VERSION 5.8 ;
BUSBITCHARS "[]" ;
DIVIDERCHAR "/" ;
UNITS
    DATABASE MICRONS 1000 ;
END UNITS

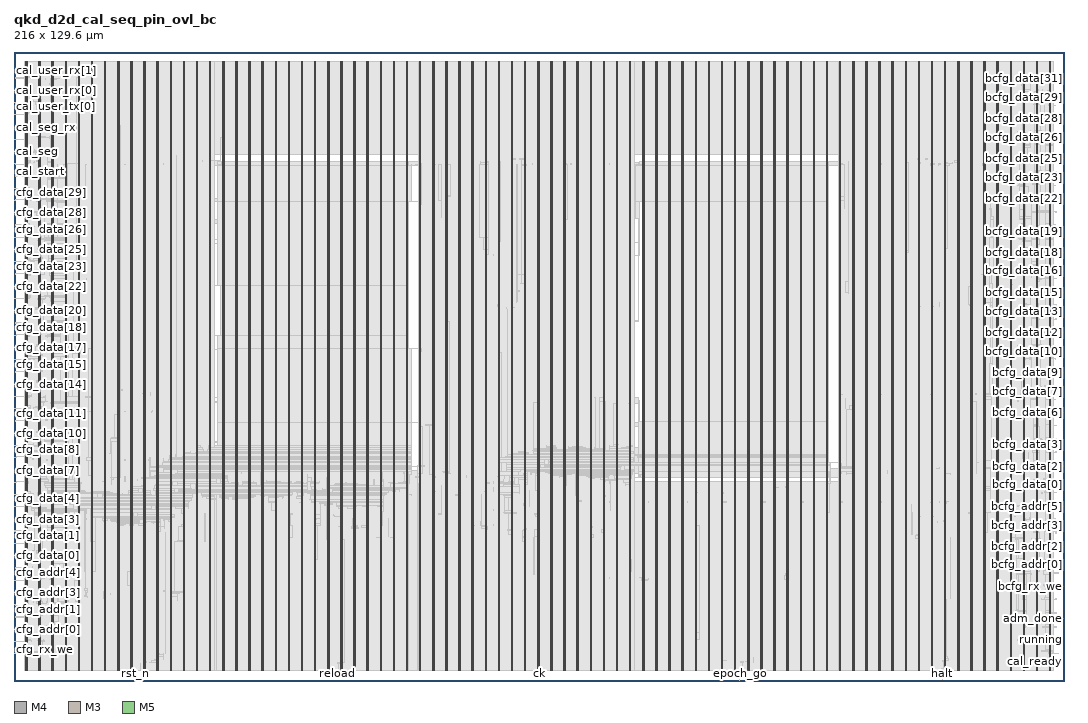
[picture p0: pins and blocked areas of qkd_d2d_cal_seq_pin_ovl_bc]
MACRO qkd_d2d_cal_seq_pin_ovl_bc
  FOREIGN qkd_d2d_cal_seq_pin_ovl_bc 0 0 ;
  CLASS BLOCK ;
  SIZE 216 BY 129.6 ;
  PIN adm_done
    DIRECTION OUTPUT ;
    USE SIGNAL ;
    PORT
      LAYER M4 ;
        RECT  215.808 11.184 216 11.208 ;
    END
  END adm_done
  PIN bcfg_addr[0]
    DIRECTION INPUT ;
    USE SIGNAL ;
    PORT
      LAYER M4 ;
        RECT  215.808 22.224 216 22.248 ;
    END
  END bcfg_addr[0]
  PIN bcfg_addr[1]
    DIRECTION INPUT ;
    USE SIGNAL ;
    PORT
      LAYER M4 ;
        RECT  215.808 24.96 216 24.984 ;
    END
  END bcfg_addr[1]
  PIN bcfg_addr[2]
    DIRECTION INPUT ;
    USE SIGNAL ;
    PORT
      LAYER M4 ;
        RECT  215.808 27.696 216 27.72 ;
    END
  END bcfg_addr[2]
  PIN bcfg_addr[3]
    DIRECTION INPUT ;
    USE SIGNAL ;
    PORT
      LAYER M4 ;
        RECT  215.808 30.432 216 30.456 ;
    END
  END bcfg_addr[3]
  PIN bcfg_addr[4]
    DIRECTION INPUT ;
    USE SIGNAL ;
    PORT
      LAYER M4 ;
        RECT  215.808 33.216 216 33.24 ;
    END
  END bcfg_addr[4]
  PIN bcfg_addr[5]
    DIRECTION INPUT ;
    USE SIGNAL ;
    PORT
      LAYER M4 ;
        RECT  215.808 35.952 216 35.976 ;
    END
  END bcfg_addr[5]
  PIN bcfg_data[0]
    DIRECTION INPUT ;
    USE SIGNAL ;
    PORT
      LAYER M4 ;
        RECT  215.808 38.688 216 38.712 ;
    END
  END bcfg_data[0]
  PIN bcfg_data[10]
    DIRECTION INPUT ;
    USE SIGNAL ;
    PORT
      LAYER M4 ;
        RECT  215.808 66.192 216 66.216 ;
    END
  END bcfg_data[10]
  PIN bcfg_data[11]
    DIRECTION INPUT ;
    USE SIGNAL ;
    PORT
      LAYER M4 ;
        RECT  215.808 68.928 216 68.952 ;
    END
  END bcfg_data[11]
  PIN bcfg_data[12]
    DIRECTION INPUT ;
    USE SIGNAL ;
    PORT
      LAYER M4 ;
        RECT  215.808 71.664 216 71.688 ;
    END
  END bcfg_data[12]
  PIN bcfg_data[13]
    DIRECTION INPUT ;
    USE SIGNAL ;
    PORT
      LAYER M4 ;
        RECT  215.808 74.448 216 74.472 ;
    END
  END bcfg_data[13]
  PIN bcfg_data[14]
    DIRECTION INPUT ;
    USE SIGNAL ;
    PORT
      LAYER M4 ;
        RECT  215.808 77.184 216 77.208 ;
    END
  END bcfg_data[14]
  PIN bcfg_data[15]
    DIRECTION INPUT ;
    USE SIGNAL ;
    PORT
      LAYER M4 ;
        RECT  215.808 79.92 216 79.944 ;
    END
  END bcfg_data[15]
  PIN bcfg_data[16]
    DIRECTION INPUT ;
    USE SIGNAL ;
    PORT
      LAYER M4 ;
        RECT  215.808 82.704 216 82.728 ;
    END
  END bcfg_data[16]
  PIN bcfg_data[17]
    DIRECTION INPUT ;
    USE SIGNAL ;
    PORT
      LAYER M4 ;
        RECT  215.808 85.44 216 85.464 ;
    END
  END bcfg_data[17]
  PIN bcfg_data[18]
    DIRECTION INPUT ;
    USE SIGNAL ;
    PORT
      LAYER M4 ;
        RECT  215.808 88.176 216 88.2 ;
    END
  END bcfg_data[18]
  PIN bcfg_data[19]
    DIRECTION INPUT ;
    USE SIGNAL ;
    PORT
      LAYER M4 ;
        RECT  215.808 90.912 216 90.936 ;
    END
  END bcfg_data[19]
  PIN bcfg_data[1]
    DIRECTION INPUT ;
    USE SIGNAL ;
    PORT
      LAYER M4 ;
        RECT  215.808 41.424 216 41.448 ;
    END
  END bcfg_data[1]
  PIN bcfg_data[20]
    DIRECTION INPUT ;
    USE SIGNAL ;
    PORT
      LAYER M4 ;
        RECT  215.808 93.696 216 93.72 ;
    END
  END bcfg_data[20]
  PIN bcfg_data[21]
    DIRECTION INPUT ;
    USE SIGNAL ;
    PORT
      LAYER M4 ;
        RECT  215.808 96.432 216 96.456 ;
    END
  END bcfg_data[21]
  PIN bcfg_data[22]
    DIRECTION INPUT ;
    USE SIGNAL ;
    PORT
      LAYER M4 ;
        RECT  215.808 99.168 216 99.192 ;
    END
  END bcfg_data[22]
  PIN bcfg_data[23]
    DIRECTION INPUT ;
    USE SIGNAL ;
    PORT
      LAYER M4 ;
        RECT  215.808 101.904 216 101.928 ;
    END
  END bcfg_data[23]
  PIN bcfg_data[24]
    DIRECTION INPUT ;
    USE SIGNAL ;
    PORT
      LAYER M4 ;
        RECT  215.808 104.688 216 104.712 ;
    END
  END bcfg_data[24]
  PIN bcfg_data[25]
    DIRECTION INPUT ;
    USE SIGNAL ;
    PORT
      LAYER M4 ;
        RECT  215.808 107.424 216 107.448 ;
    END
  END bcfg_data[25]
  PIN bcfg_data[26]
    DIRECTION INPUT ;
    USE SIGNAL ;
    PORT
      LAYER M4 ;
        RECT  215.808 110.16 216 110.184 ;
    END
  END bcfg_data[26]
  PIN bcfg_data[27]
    DIRECTION INPUT ;
    USE SIGNAL ;
    PORT
      LAYER M4 ;
        RECT  215.808 112.944 216 112.968 ;
    END
  END bcfg_data[27]
  PIN bcfg_data[28]
    DIRECTION INPUT ;
    USE SIGNAL ;
    PORT
      LAYER M4 ;
        RECT  215.808 115.68 216 115.704 ;
    END
  END bcfg_data[28]
  PIN bcfg_data[29]
    DIRECTION INPUT ;
    USE SIGNAL ;
    PORT
      LAYER M4 ;
        RECT  215.808 118.416 216 118.44 ;
    END
  END bcfg_data[29]
  PIN bcfg_data[2]
    DIRECTION INPUT ;
    USE SIGNAL ;
    PORT
      LAYER M4 ;
        RECT  215.808 44.208 216 44.232 ;
    END
  END bcfg_data[2]
  PIN bcfg_data[30]
    DIRECTION INPUT ;
    USE SIGNAL ;
    PORT
      LAYER M4 ;
        RECT  215.808 121.152 216 121.176 ;
    END
  END bcfg_data[30]
  PIN bcfg_data[31]
    DIRECTION INPUT ;
    USE SIGNAL ;
    PORT
      LAYER M4 ;
        RECT  215.808 123.936 216 123.96 ;
    END
  END bcfg_data[31]
  PIN bcfg_data[3]
    DIRECTION INPUT ;
    USE SIGNAL ;
    PORT
      LAYER M4 ;
        RECT  215.808 46.944 216 46.968 ;
    END
  END bcfg_data[3]
  PIN bcfg_data[4]
    DIRECTION INPUT ;
    USE SIGNAL ;
    PORT
      LAYER M4 ;
        RECT  215.808 49.68 216 49.704 ;
    END
  END bcfg_data[4]
  PIN bcfg_data[5]
    DIRECTION INPUT ;
    USE SIGNAL ;
    PORT
      LAYER M4 ;
        RECT  215.808 52.464 216 52.488 ;
    END
  END bcfg_data[5]
  PIN bcfg_data[6]
    DIRECTION INPUT ;
    USE SIGNAL ;
    PORT
      LAYER M4 ;
        RECT  215.808 55.2 216 55.224 ;
    END
  END bcfg_data[6]
  PIN bcfg_data[7]
    DIRECTION INPUT ;
    USE SIGNAL ;
    PORT
      LAYER M4 ;
        RECT  215.808 57.936 216 57.96 ;
    END
  END bcfg_data[7]
  PIN bcfg_data[8]
    DIRECTION INPUT ;
    USE SIGNAL ;
    PORT
      LAYER M4 ;
        RECT  215.808 60.672 216 60.696 ;
    END
  END bcfg_data[8]
  PIN bcfg_data[9]
    DIRECTION INPUT ;
    USE SIGNAL ;
    PORT
      LAYER M4 ;
        RECT  215.808 63.456 216 63.48 ;
    END
  END bcfg_data[9]
  PIN bcfg_rx_we
    DIRECTION INPUT ;
    USE SIGNAL ;
    PORT
      LAYER M4 ;
        RECT  215.808 19.44 216 19.464 ;
    END
  END bcfg_rx_we
  PIN bcfg_tx_we
    DIRECTION INPUT ;
    USE SIGNAL ;
    PORT
      LAYER M4 ;
        RECT  215.808 16.704 216 16.728 ;
    END
  END bcfg_tx_we
  PIN cal_ready
    DIRECTION OUTPUT ;
    USE SIGNAL ;
    PORT
      LAYER M4 ;
        RECT  215.808 5.712 216 5.736 ;
    END
  END cal_ready
  PIN cal_seg
    DIRECTION OUTPUT ;
    USE SIGNAL ;
    PORT
      LAYER M4 ;
        RECT  0 108.912 0.192 108.936 ;
    END
  END cal_seg
  PIN cal_seg_rx
    DIRECTION OUTPUT ;
    USE SIGNAL ;
    PORT
      LAYER M4 ;
        RECT  0 113.952 0.192 113.976 ;
    END
  END cal_seg_rx
  PIN cal_start
    DIRECTION OUTPUT ;
    USE SIGNAL ;
    PORT
      LAYER M4 ;
        RECT  0 106.416 0.192 106.44 ;
    END
  END cal_start
  PIN cal_start_rx
    DIRECTION OUTPUT ;
    USE SIGNAL ;
    PORT
      LAYER M4 ;
        RECT  0 111.408 0.192 111.432 ;
    END
  END cal_start_rx
  PIN cal_user_rx[0]
    DIRECTION OUTPUT ;
    USE SIGNAL ;
    PORT
      LAYER M4 ;
        RECT  0 121.488 0.192 121.512 ;
    END
  END cal_user_rx[0]
  PIN cal_user_rx[1]
    DIRECTION OUTPUT ;
    USE SIGNAL ;
    PORT
      LAYER M4 ;
        RECT  0 124.032 0.192 124.056 ;
    END
  END cal_user_rx[1]
  PIN cal_user_tx[0]
    DIRECTION OUTPUT ;
    USE SIGNAL ;
    PORT
      LAYER M4 ;
        RECT  0 116.496 0.192 116.52 ;
    END
  END cal_user_tx[0]
  PIN cal_user_tx[1]
    DIRECTION OUTPUT ;
    USE SIGNAL ;
    PORT
      LAYER M4 ;
        RECT  0 118.992 0.192 119.016 ;
    END
  END cal_user_tx[1]
  PIN cfg_addr[0]
    DIRECTION OUTPUT ;
    USE SIGNAL ;
    PORT
      LAYER M4 ;
        RECT  0 10.656 0.192 10.68 ;
    END
  END cfg_addr[0]
  PIN cfg_addr[1]
    DIRECTION OUTPUT ;
    USE SIGNAL ;
    PORT
      LAYER M4 ;
        RECT  0 13.152 0.192 13.176 ;
    END
  END cfg_addr[1]
  PIN cfg_addr[2]
    DIRECTION OUTPUT ;
    USE SIGNAL ;
    PORT
      LAYER M4 ;
        RECT  0 15.696 0.192 15.72 ;
    END
  END cfg_addr[2]
  PIN cfg_addr[3]
    DIRECTION OUTPUT ;
    USE SIGNAL ;
    PORT
      LAYER M4 ;
        RECT  0 18.192 0.192 18.216 ;
    END
  END cfg_addr[3]
  PIN cfg_addr[4]
    DIRECTION OUTPUT ;
    USE SIGNAL ;
    PORT
      LAYER M4 ;
        RECT  0 20.688 0.192 20.712 ;
    END
  END cfg_addr[4]
  PIN cfg_addr[5]
    DIRECTION OUTPUT ;
    USE SIGNAL ;
    PORT
      LAYER M4 ;
        RECT  0 23.232 0.192 23.256 ;
    END
  END cfg_addr[5]
  PIN cfg_data[0]
    DIRECTION OUTPUT ;
    USE SIGNAL ;
    PORT
      LAYER M4 ;
        RECT  0 25.776 0.192 25.8 ;
    END
  END cfg_data[0]
  PIN cfg_data[10]
    DIRECTION OUTPUT ;
    USE SIGNAL ;
    PORT
      LAYER M4 ;
        RECT  0 50.928 0.192 50.952 ;
    END
  END cfg_data[10]
  PIN cfg_data[11]
    DIRECTION OUTPUT ;
    USE SIGNAL ;
    PORT
      LAYER M4 ;
        RECT  0 53.472 0.192 53.496 ;
    END
  END cfg_data[11]
  PIN cfg_data[12]
    DIRECTION OUTPUT ;
    USE SIGNAL ;
    PORT
      LAYER M4 ;
        RECT  0 56.016 0.192 56.04 ;
    END
  END cfg_data[12]
  PIN cfg_data[13]
    DIRECTION OUTPUT ;
    USE SIGNAL ;
    PORT
      LAYER M4 ;
        RECT  0 58.512 0.192 58.536 ;
    END
  END cfg_data[13]
  PIN cfg_data[14]
    DIRECTION OUTPUT ;
    USE SIGNAL ;
    PORT
      LAYER M4 ;
        RECT  0 61.008 0.192 61.032 ;
    END
  END cfg_data[14]
  PIN cfg_data[15]
    DIRECTION OUTPUT ;
    USE SIGNAL ;
    PORT
      LAYER M4 ;
        RECT  0 63.552 0.192 63.576 ;
    END
  END cfg_data[15]
  PIN cfg_data[16]
    DIRECTION OUTPUT ;
    USE SIGNAL ;
    PORT
      LAYER M4 ;
        RECT  0 66.096 0.192 66.12 ;
    END
  END cfg_data[16]
  PIN cfg_data[17]
    DIRECTION OUTPUT ;
    USE SIGNAL ;
    PORT
      LAYER M4 ;
        RECT  0 68.592 0.192 68.616 ;
    END
  END cfg_data[17]
  PIN cfg_data[18]
    DIRECTION OUTPUT ;
    USE SIGNAL ;
    PORT
      LAYER M4 ;
        RECT  0 71.088 0.192 71.112 ;
    END
  END cfg_data[18]
  PIN cfg_data[19]
    DIRECTION OUTPUT ;
    USE SIGNAL ;
    PORT
      LAYER M4 ;
        RECT  0 73.632 0.192 73.656 ;
    END
  END cfg_data[19]
  PIN cfg_data[1]
    DIRECTION OUTPUT ;
    USE SIGNAL ;
    PORT
      LAYER M4 ;
        RECT  0 28.272 0.192 28.296 ;
    END
  END cfg_data[1]
  PIN cfg_data[20]
    DIRECTION OUTPUT ;
    USE SIGNAL ;
    PORT
      LAYER M4 ;
        RECT  0 76.176 0.192 76.2 ;
    END
  END cfg_data[20]
  PIN cfg_data[21]
    DIRECTION OUTPUT ;
    USE SIGNAL ;
    PORT
      LAYER M4 ;
        RECT  0 78.672 0.192 78.696 ;
    END
  END cfg_data[21]
  PIN cfg_data[22]
    DIRECTION OUTPUT ;
    USE SIGNAL ;
    PORT
      LAYER M4 ;
        RECT  0 81.168 0.192 81.192 ;
    END
  END cfg_data[22]
  PIN cfg_data[23]
    DIRECTION OUTPUT ;
    USE SIGNAL ;
    PORT
      LAYER M4 ;
        RECT  0 83.712 0.192 83.736 ;
    END
  END cfg_data[23]
  PIN cfg_data[24]
    DIRECTION OUTPUT ;
    USE SIGNAL ;
    PORT
      LAYER M4 ;
        RECT  0 86.256 0.192 86.28 ;
    END
  END cfg_data[24]
  PIN cfg_data[25]
    DIRECTION OUTPUT ;
    USE SIGNAL ;
    PORT
      LAYER M4 ;
        RECT  0 88.752 0.192 88.776 ;
    END
  END cfg_data[25]
  PIN cfg_data[26]
    DIRECTION OUTPUT ;
    USE SIGNAL ;
    PORT
      LAYER M4 ;
        RECT  0 91.248 0.192 91.272 ;
    END
  END cfg_data[26]
  PIN cfg_data[27]
    DIRECTION OUTPUT ;
    USE SIGNAL ;
    PORT
      LAYER M4 ;
        RECT  0 93.792 0.192 93.816 ;
    END
  END cfg_data[27]
  PIN cfg_data[28]
    DIRECTION OUTPUT ;
    USE SIGNAL ;
    PORT
      LAYER M4 ;
        RECT  0 96.336 0.192 96.36 ;
    END
  END cfg_data[28]
  PIN cfg_data[29]
    DIRECTION OUTPUT ;
    USE SIGNAL ;
    PORT
      LAYER M4 ;
        RECT  0 98.832 0.192 98.856 ;
    END
  END cfg_data[29]
  PIN cfg_data[2]
    DIRECTION OUTPUT ;
    USE SIGNAL ;
    PORT
      LAYER M4 ;
        RECT  0 30.768 0.192 30.792 ;
    END
  END cfg_data[2]
  PIN cfg_data[30]
    DIRECTION OUTPUT ;
    USE SIGNAL ;
    PORT
      LAYER M4 ;
        RECT  0 101.328 0.192 101.352 ;
    END
  END cfg_data[30]
  PIN cfg_data[31]
    DIRECTION OUTPUT ;
    USE SIGNAL ;
    PORT
      LAYER M4 ;
        RECT  0 103.872 0.192 103.896 ;
    END
  END cfg_data[31]
  PIN cfg_data[3]
    DIRECTION OUTPUT ;
    USE SIGNAL ;
    PORT
      LAYER M4 ;
        RECT  0 33.312 0.192 33.336 ;
    END
  END cfg_data[3]
  PIN cfg_data[4]
    DIRECTION OUTPUT ;
    USE SIGNAL ;
    PORT
      LAYER M4 ;
        RECT  0 35.856 0.192 35.88 ;
    END
  END cfg_data[4]
  PIN cfg_data[5]
    DIRECTION OUTPUT ;
    USE SIGNAL ;
    PORT
      LAYER M4 ;
        RECT  0 38.352 0.192 38.376 ;
    END
  END cfg_data[5]
  PIN cfg_data[6]
    DIRECTION OUTPUT ;
    USE SIGNAL ;
    PORT
      LAYER M4 ;
        RECT  0 40.848 0.192 40.872 ;
    END
  END cfg_data[6]
  PIN cfg_data[7]
    DIRECTION OUTPUT ;
    USE SIGNAL ;
    PORT
      LAYER M4 ;
        RECT  0 43.392 0.192 43.416 ;
    END
  END cfg_data[7]
  PIN cfg_data[8]
    DIRECTION OUTPUT ;
    USE SIGNAL ;
    PORT
      LAYER M4 ;
        RECT  0 45.888 0.192 45.912 ;
    END
  END cfg_data[8]
  PIN cfg_data[9]
    DIRECTION OUTPUT ;
    USE SIGNAL ;
    PORT
      LAYER M4 ;
        RECT  0 48.432 0.192 48.456 ;
    END
  END cfg_data[9]
  PIN cfg_rx_we
    DIRECTION OUTPUT ;
    USE SIGNAL ;
    PORT
      LAYER M4 ;
        RECT  0 8.112 0.192 8.136 ;
    END
  END cfg_rx_we
  PIN cfg_tx_we
    DIRECTION OUTPUT ;
    USE SIGNAL ;
    PORT
      LAYER M4 ;
        RECT  0 5.616 0.192 5.64 ;
    END
  END cfg_tx_we
  PIN ck
    DIRECTION INPUT ;
    USE SIGNAL ;
    PORT
      LAYER M3 ;
        RECT  108 0 108.018 0.144 ;
    END
  END ck
  PIN epoch_go
    DIRECTION INPUT ;
    USE SIGNAL ;
    PORT
      LAYER M5 ;
        RECT  149.472 0 149.496 0.192 ;
    END
  END epoch_go
  PIN fault
    DIRECTION OUTPUT ;
    USE SIGNAL ;
    PORT
      LAYER M4 ;
        RECT  215.808 13.968 216 13.992 ;
    END
  END fault
  PIN halt
    DIRECTION INPUT ;
    USE SIGNAL ;
    PORT
      LAYER M3 ;
        RECT  190.944 0 190.962 0.144 ;
    END
  END halt
  PIN reload
    DIRECTION INPUT ;
    USE SIGNAL ;
    PORT
      LAYER M5 ;
        RECT  66.528 0 66.552 0.192 ;
    END
  END reload
  PIN rst_n
    DIRECTION INPUT ;
    USE SIGNAL ;
    PORT
      LAYER M3 ;
        RECT  25.056 0 25.074 0.144 ;
    END
  END rst_n
  PIN running
    DIRECTION OUTPUT ;
    USE SIGNAL ;
    PORT
      LAYER M4 ;
        RECT  215.808 8.448 216 8.472 ;
    END
  END running
  PIN VDD
    DIRECTION INOUT ;
    USE POWER ;
    PORT
      LAYER M5 ;
        RECT  213.192 2.151 213.312 127.449 ;
        RECT  210.492 2.151 210.612 127.449 ;
        RECT  207.792 2.151 207.912 127.449 ;
        RECT  205.092 2.151 205.212 127.449 ;
        RECT  202.392 2.151 202.512 127.449 ;
        RECT  199.692 2.151 199.812 127.449 ;
        RECT  196.992 2.151 197.112 127.449 ;
        RECT  194.292 2.151 194.412 127.449 ;
        RECT  191.592 2.151 191.712 127.449 ;
        RECT  188.892 2.151 189.012 127.449 ;
        RECT  186.192 2.151 186.312 127.449 ;
        RECT  183.492 2.151 183.612 127.449 ;
        RECT  180.792 2.151 180.912 127.449 ;
        RECT  178.092 2.151 178.212 127.449 ;
        RECT  175.392 2.151 175.512 127.449 ;
        RECT  172.692 2.151 172.812 127.449 ;
        RECT  169.992 2.151 170.112 127.449 ;
        RECT  167.292 2.151 167.412 127.449 ;
        RECT  164.592 2.151 164.712 127.449 ;
        RECT  161.892 2.151 162.012 127.449 ;
        RECT  159.192 2.151 159.312 127.449 ;
        RECT  156.492 2.151 156.612 127.449 ;
        RECT  153.792 2.151 153.912 127.449 ;
        RECT  151.092 2.151 151.212 127.449 ;
        RECT  148.392 2.151 148.512 127.449 ;
        RECT  145.692 2.151 145.812 127.449 ;
        RECT  142.992 2.151 143.112 127.449 ;
        RECT  140.292 2.151 140.412 127.449 ;
        RECT  137.592 2.151 137.712 127.449 ;
        RECT  134.892 2.151 135.012 127.449 ;
        RECT  132.192 2.151 132.312 127.449 ;
        RECT  129.492 2.151 129.612 127.449 ;
        RECT  126.792 2.151 126.912 127.449 ;
        RECT  124.092 2.151 124.212 127.449 ;
        RECT  121.392 2.151 121.512 127.449 ;
        RECT  118.692 2.151 118.812 127.449 ;
        RECT  115.992 2.151 116.112 127.449 ;
        RECT  113.292 2.151 113.412 127.449 ;
        RECT  110.592 2.151 110.712 127.449 ;
        RECT  107.892 2.151 108.012 127.449 ;
        RECT  105.192 2.151 105.312 127.449 ;
        RECT  102.492 2.151 102.612 127.449 ;
        RECT  99.792 2.151 99.912 127.449 ;
        RECT  97.092 2.151 97.212 127.449 ;
        RECT  94.392 2.151 94.512 127.449 ;
        RECT  91.692 2.151 91.812 127.449 ;
        RECT  88.992 2.151 89.112 127.449 ;
        RECT  86.292 2.151 86.412 127.449 ;
        RECT  83.592 2.151 83.712 127.449 ;
        RECT  80.892 2.151 81.012 127.449 ;
        RECT  78.192 2.151 78.312 127.449 ;
        RECT  75.492 2.151 75.612 127.449 ;
        RECT  72.792 2.151 72.912 127.449 ;
        RECT  70.092 2.151 70.212 127.449 ;
        RECT  67.392 2.151 67.512 127.449 ;
        RECT  64.692 2.151 64.812 127.449 ;
        RECT  61.992 2.151 62.112 127.449 ;
        RECT  59.292 2.151 59.412 127.449 ;
        RECT  56.592 2.151 56.712 127.449 ;
        RECT  53.892 2.151 54.012 127.449 ;
        RECT  51.192 2.151 51.312 127.449 ;
        RECT  48.492 2.151 48.612 127.449 ;
        RECT  45.792 2.151 45.912 127.449 ;
        RECT  43.092 2.151 43.212 127.449 ;
        RECT  40.392 2.151 40.512 127.449 ;
        RECT  37.692 2.151 37.812 127.449 ;
        RECT  34.992 2.151 35.112 127.449 ;
        RECT  32.292 2.151 32.412 127.449 ;
        RECT  29.592 2.151 29.712 127.449 ;
        RECT  26.892 2.151 27.012 127.449 ;
        RECT  24.192 2.151 24.312 127.449 ;
        RECT  21.492 2.151 21.612 127.449 ;
        RECT  18.792 2.151 18.912 127.449 ;
        RECT  16.092 2.151 16.212 127.449 ;
        RECT  13.392 2.151 13.512 127.449 ;
        RECT  10.692 2.151 10.812 127.449 ;
        RECT  7.992 2.151 8.112 127.449 ;
        RECT  5.292 2.151 5.412 127.449 ;
        RECT  2.592 2.151 2.712 127.449 ;
    END
  END VDD
  PIN VSS
    DIRECTION INOUT ;
    USE GROUND ;
    PORT
      LAYER M5 ;
        RECT  213 2.137 213.12 127.463 ;
        RECT  210.3 2.137 210.42 127.463 ;
        RECT  207.6 2.137 207.72 127.463 ;
        RECT  204.9 2.137 205.02 127.463 ;
        RECT  202.2 2.137 202.32 127.463 ;
        RECT  199.5 2.137 199.62 127.463 ;
        RECT  196.8 2.137 196.92 127.463 ;
        RECT  194.1 2.137 194.22 127.463 ;
        RECT  191.4 2.137 191.52 127.463 ;
        RECT  188.7 2.137 188.82 127.463 ;
        RECT  186 2.137 186.12 127.463 ;
        RECT  183.3 2.137 183.42 127.463 ;
        RECT  180.6 2.137 180.72 127.463 ;
        RECT  177.9 2.137 178.02 127.463 ;
        RECT  175.2 2.137 175.32 127.463 ;
        RECT  172.5 2.137 172.62 127.463 ;
        RECT  169.8 2.137 169.92 127.463 ;
        RECT  167.1 2.137 167.22 127.463 ;
        RECT  164.4 2.137 164.52 127.463 ;
        RECT  161.7 2.137 161.82 127.463 ;
        RECT  159 2.137 159.12 127.463 ;
        RECT  156.3 2.137 156.42 127.463 ;
        RECT  153.6 2.137 153.72 127.463 ;
        RECT  150.9 2.137 151.02 127.463 ;
        RECT  148.2 2.137 148.32 127.463 ;
        RECT  145.5 2.137 145.62 127.463 ;
        RECT  142.8 2.137 142.92 127.463 ;
        RECT  140.1 2.137 140.22 127.463 ;
        RECT  137.4 2.137 137.52 127.463 ;
        RECT  134.7 2.137 134.82 127.463 ;
        RECT  132 2.137 132.12 127.463 ;
        RECT  129.3 2.137 129.42 127.463 ;
        RECT  126.6 2.137 126.72 127.463 ;
        RECT  123.9 2.137 124.02 127.463 ;
        RECT  121.2 2.137 121.32 127.463 ;
        RECT  118.5 2.137 118.62 127.463 ;
        RECT  115.8 2.137 115.92 127.463 ;
        RECT  113.1 2.137 113.22 127.463 ;
        RECT  110.4 2.137 110.52 127.463 ;
        RECT  107.7 2.137 107.82 127.463 ;
        RECT  105 2.137 105.12 127.463 ;
        RECT  102.3 2.137 102.42 127.463 ;
        RECT  99.6 2.137 99.72 127.463 ;
        RECT  96.9 2.137 97.02 127.463 ;
        RECT  94.2 2.137 94.32 127.463 ;
        RECT  91.5 2.137 91.62 127.463 ;
        RECT  88.8 2.137 88.92 127.463 ;
        RECT  86.1 2.137 86.22 127.463 ;
        RECT  83.4 2.137 83.52 127.463 ;
        RECT  80.7 2.137 80.82 127.463 ;
        RECT  78 2.137 78.12 127.463 ;
        RECT  75.3 2.137 75.42 127.463 ;
        RECT  72.6 2.137 72.72 127.463 ;
        RECT  69.9 2.137 70.02 127.463 ;
        RECT  67.2 2.137 67.32 127.463 ;
        RECT  64.5 2.137 64.62 127.463 ;
        RECT  61.8 2.137 61.92 127.463 ;
        RECT  59.1 2.137 59.22 127.463 ;
        RECT  56.4 2.137 56.52 127.463 ;
        RECT  53.7 2.137 53.82 127.463 ;
        RECT  51 2.137 51.12 127.463 ;
        RECT  48.3 2.137 48.42 127.463 ;
        RECT  45.6 2.137 45.72 127.463 ;
        RECT  42.9 2.137 43.02 127.463 ;
        RECT  40.2 2.137 40.32 127.463 ;
        RECT  37.5 2.137 37.62 127.463 ;
        RECT  34.8 2.137 34.92 127.463 ;
        RECT  32.1 2.137 32.22 127.463 ;
        RECT  29.4 2.137 29.52 127.463 ;
        RECT  26.7 2.137 26.82 127.463 ;
        RECT  24 2.137 24.12 127.463 ;
        RECT  21.3 2.137 21.42 127.463 ;
        RECT  18.6 2.137 18.72 127.463 ;
        RECT  15.9 2.137 16.02 127.463 ;
        RECT  13.2 2.137 13.32 127.463 ;
        RECT  10.5 2.137 10.62 127.463 ;
        RECT  7.8 2.137 7.92 127.463 ;
        RECT  5.1 2.137 5.22 127.463 ;
        RECT  2.4 2.137 2.52 127.463 ;
    END
  END VSS
  OBS
    LAYER RVTN ;
     RECT  2.16 2.16 213.84 2.295 ;
     RECT  2.16 2.565 213.84 2.835 ;
     RECT  2.16 3.105 213.84 3.375 ;
     RECT  2.16 3.645 213.84 3.915 ;
     RECT  2.16 4.185 213.84 4.455 ;
     RECT  2.16 4.725 213.84 4.995 ;
     RECT  2.16 5.265 213.84 5.535 ;
     RECT  2.16 5.805 213.84 6.075 ;
     RECT  2.16 6.345 213.84 6.615 ;
     RECT  2.16 6.885 213.84 7.155 ;
     RECT  2.16 7.425 213.84 7.695 ;
     RECT  2.16 7.965 213.84 8.235 ;
     RECT  2.16 8.505 213.84 8.775 ;
     RECT  2.16 9.045 213.84 9.315 ;
     RECT  2.16 9.585 213.84 9.855 ;
     RECT  2.16 10.125 213.84 10.395 ;
     RECT  2.16 10.665 213.84 10.935 ;
     RECT  2.16 11.205 213.84 11.475 ;
     RECT  2.16 11.745 213.84 12.015 ;
     RECT  2.16 12.285 213.84 12.555 ;
     RECT  2.16 12.825 213.84 13.095 ;
     RECT  2.16 13.365 213.84 13.635 ;
     RECT  2.16 13.905 213.84 14.175 ;
     RECT  2.16 14.445 213.84 14.715 ;
     RECT  2.16 14.985 213.84 15.255 ;
     RECT  2.16 15.525 213.84 15.795 ;
     RECT  2.16 16.065 213.84 16.335 ;
     RECT  2.16 16.605 213.84 16.875 ;
     RECT  2.16 17.145 213.84 17.415 ;
     RECT  2.16 17.685 213.84 17.955 ;
     RECT  2.16 18.225 213.84 18.495 ;
     RECT  2.16 18.765 213.84 19.035 ;
     RECT  2.16 19.305 213.84 19.575 ;
     RECT  2.16 19.845 213.84 20.115 ;
     RECT  2.16 20.385 213.84 20.655 ;
     RECT  2.16 20.925 213.84 21.195 ;
     RECT  2.16 21.465 213.84 21.735 ;
     RECT  2.16 22.005 213.84 22.275 ;
     RECT  2.16 22.545 213.84 22.815 ;
     RECT  2.16 23.085 213.84 23.355 ;
     RECT  2.16 23.625 213.84 23.895 ;
     RECT  2.16 24.165 213.84 24.435 ;
     RECT  2.16 24.705 213.84 24.975 ;
     RECT  2.16 25.245 213.84 25.515 ;
     RECT  2.16 25.785 213.84 26.055 ;
     RECT  2.16 26.325 213.84 26.595 ;
     RECT  2.16 26.865 213.84 27.135 ;
     RECT  2.16 27.405 213.84 27.675 ;
     RECT  2.16 27.945 213.84 28.215 ;
     RECT  2.16 28.485 213.84 28.755 ;
     RECT  2.16 29.025 213.84 29.295 ;
     RECT  2.16 29.565 213.84 29.835 ;
     RECT  2.16 30.105 213.84 30.375 ;
     RECT  2.16 30.645 213.84 30.915 ;
     RECT  2.16 31.185 213.84 31.455 ;
     RECT  2.16 31.725 213.84 31.995 ;
     RECT  2.16 32.265 213.84 32.535 ;
     RECT  2.16 32.805 213.84 33.075 ;
     RECT  2.16 33.345 213.84 33.615 ;
     RECT  2.16 33.885 213.84 34.155 ;
     RECT  2.16 34.425 213.84 34.695 ;
     RECT  2.16 34.965 213.84 35.235 ;
     RECT  2.16 35.505 213.84 35.775 ;
     RECT  2.16 36.045 213.84 36.315 ;
     RECT  2.16 36.585 213.84 36.855 ;
     RECT  2.16 37.125 213.84 37.395 ;
     RECT  2.16 37.665 213.84 37.935 ;
     RECT  2.16 38.205 213.84 38.475 ;
     RECT  2.16 38.745 213.84 39.015 ;
     RECT  2.16 39.285 213.84 39.555 ;
     RECT  2.16 39.825 213.84 40.095 ;
     RECT  2.16 40.365 213.84 40.635 ;
     RECT  2.16 40.905 213.84 41.04 ;
     RECT  2.16 41.04 41.148 41.175 ;
     RECT  83.268 41.04 127.548 41.175 ;
     RECT  169.668 41.04 213.84 41.175 ;
     RECT  2.16 41.445 41.148 41.715 ;
     RECT  83.268 41.445 127.548 41.715 ;
     RECT  169.668 41.445 213.84 41.715 ;
     RECT  2.16 41.985 41.148 42.255 ;
     RECT  83.268 41.985 127.548 42.255 ;
     RECT  169.668 41.985 213.84 42.255 ;
     RECT  2.16 42.525 41.148 42.795 ;
     RECT  83.268 42.525 127.548 42.795 ;
     RECT  169.668 42.525 213.84 42.795 ;
     RECT  2.16 43.065 41.148 43.335 ;
     RECT  83.268 43.065 127.548 43.335 ;
     RECT  169.668 43.065 213.84 43.335 ;
     RECT  2.16 43.605 41.148 43.875 ;
     RECT  83.268 43.605 127.548 43.875 ;
     RECT  169.668 43.605 213.84 43.875 ;
     RECT  2.16 44.145 41.148 44.415 ;
     RECT  83.268 44.145 127.548 44.415 ;
     RECT  169.668 44.145 213.84 44.415 ;
     RECT  2.16 44.685 41.148 44.955 ;
     RECT  83.268 44.685 127.548 44.955 ;
     RECT  169.668 44.685 213.84 44.955 ;
     RECT  2.16 45.225 41.148 45.495 ;
     RECT  83.268 45.225 127.548 45.495 ;
     RECT  169.668 45.225 213.84 45.495 ;
     RECT  2.16 45.765 41.148 46.035 ;
     RECT  83.268 45.765 127.548 46.035 ;
     RECT  169.668 45.765 213.84 46.035 ;
     RECT  2.16 46.305 41.148 46.575 ;
     RECT  83.268 46.305 127.548 46.575 ;
     RECT  169.668 46.305 213.84 46.575 ;
     RECT  2.16 46.845 41.148 47.115 ;
     RECT  83.268 46.845 127.548 47.115 ;
     RECT  169.668 46.845 213.84 47.115 ;
     RECT  2.16 47.385 41.148 47.655 ;
     RECT  83.268 47.385 127.548 47.655 ;
     RECT  169.668 47.385 213.84 47.655 ;
     RECT  2.16 47.925 41.148 48.195 ;
     RECT  83.268 47.925 127.548 48.195 ;
     RECT  169.668 47.925 213.84 48.195 ;
     RECT  2.16 48.465 41.148 48.735 ;
     RECT  83.268 48.465 127.548 48.735 ;
     RECT  169.668 48.465 213.84 48.735 ;
     RECT  2.16 49.005 41.148 49.275 ;
     RECT  83.268 49.005 127.548 49.275 ;
     RECT  169.668 49.005 213.84 49.275 ;
     RECT  2.16 49.545 41.148 49.815 ;
     RECT  83.268 49.545 127.548 49.815 ;
     RECT  169.668 49.545 213.84 49.815 ;
     RECT  2.16 50.085 41.148 50.355 ;
     RECT  83.268 50.085 127.548 50.355 ;
     RECT  169.668 50.085 213.84 50.355 ;
     RECT  2.16 50.625 41.148 50.895 ;
     RECT  83.268 50.625 127.548 50.895 ;
     RECT  169.668 50.625 213.84 50.895 ;
     RECT  2.16 51.165 41.148 51.435 ;
     RECT  83.268 51.165 127.548 51.435 ;
     RECT  169.668 51.165 213.84 51.435 ;
     RECT  2.16 51.705 41.148 51.975 ;
     RECT  83.268 51.705 127.548 51.975 ;
     RECT  169.668 51.705 213.84 51.975 ;
     RECT  2.16 52.245 41.148 52.515 ;
     RECT  83.268 52.245 127.548 52.515 ;
     RECT  169.668 52.245 213.84 52.515 ;
     RECT  2.16 52.785 41.148 53.055 ;
     RECT  83.268 52.785 127.548 53.055 ;
     RECT  169.668 52.785 213.84 53.055 ;
     RECT  2.16 53.325 41.148 53.595 ;
     RECT  83.268 53.325 127.548 53.595 ;
     RECT  169.668 53.325 213.84 53.595 ;
     RECT  2.16 53.865 41.148 54.135 ;
     RECT  83.268 53.865 127.548 54.135 ;
     RECT  169.668 53.865 213.84 54.135 ;
     RECT  2.16 54.405 41.148 54.675 ;
     RECT  83.268 54.405 127.548 54.675 ;
     RECT  169.668 54.405 213.84 54.675 ;
     RECT  2.16 54.945 41.148 55.215 ;
     RECT  83.268 54.945 127.548 55.215 ;
     RECT  169.668 54.945 213.84 55.215 ;
     RECT  2.16 55.485 41.148 55.755 ;
     RECT  83.268 55.485 127.548 55.755 ;
     RECT  169.668 55.485 213.84 55.755 ;
     RECT  2.16 56.025 41.148 56.295 ;
     RECT  83.268 56.025 127.548 56.295 ;
     RECT  169.668 56.025 213.84 56.295 ;
     RECT  2.16 56.565 41.148 56.835 ;
     RECT  83.268 56.565 127.548 56.835 ;
     RECT  169.668 56.565 213.84 56.835 ;
     RECT  2.16 57.105 41.148 57.375 ;
     RECT  83.268 57.105 127.548 57.375 ;
     RECT  169.668 57.105 213.84 57.375 ;
     RECT  2.16 57.645 41.148 57.915 ;
     RECT  83.268 57.645 127.548 57.915 ;
     RECT  169.668 57.645 213.84 57.915 ;
     RECT  2.16 58.185 41.148 58.455 ;
     RECT  83.268 58.185 127.548 58.455 ;
     RECT  169.668 58.185 213.84 58.455 ;
     RECT  2.16 58.725 41.148 58.995 ;
     RECT  83.268 58.725 127.548 58.995 ;
     RECT  169.668 58.725 213.84 58.995 ;
     RECT  2.16 59.265 41.148 59.535 ;
     RECT  83.268 59.265 127.548 59.535 ;
     RECT  169.668 59.265 213.84 59.535 ;
     RECT  2.16 59.805 41.148 60.075 ;
     RECT  83.268 59.805 127.548 60.075 ;
     RECT  169.668 59.805 213.84 60.075 ;
     RECT  2.16 60.345 41.148 60.615 ;
     RECT  83.268 60.345 127.548 60.615 ;
     RECT  169.668 60.345 213.84 60.615 ;
     RECT  2.16 60.885 41.148 61.155 ;
     RECT  83.268 60.885 127.548 61.155 ;
     RECT  169.668 60.885 213.84 61.155 ;
     RECT  2.16 61.425 41.148 61.695 ;
     RECT  83.268 61.425 127.548 61.695 ;
     RECT  169.668 61.425 213.84 61.695 ;
     RECT  2.16 61.965 41.148 62.235 ;
     RECT  83.268 61.965 127.548 62.235 ;
     RECT  169.668 61.965 213.84 62.235 ;
     RECT  2.16 62.505 41.148 62.775 ;
     RECT  83.268 62.505 127.548 62.775 ;
     RECT  169.668 62.505 213.84 62.775 ;
     RECT  2.16 63.045 41.148 63.315 ;
     RECT  83.268 63.045 127.548 63.315 ;
     RECT  169.668 63.045 213.84 63.315 ;
     RECT  2.16 63.585 41.148 63.855 ;
     RECT  83.268 63.585 127.548 63.855 ;
     RECT  169.668 63.585 213.84 63.855 ;
     RECT  2.16 64.125 41.148 64.395 ;
     RECT  83.268 64.125 127.548 64.395 ;
     RECT  169.668 64.125 213.84 64.395 ;
     RECT  2.16 64.665 41.148 64.935 ;
     RECT  83.268 64.665 127.548 64.935 ;
     RECT  169.668 64.665 213.84 64.935 ;
     RECT  2.16 65.205 41.148 65.475 ;
     RECT  83.268 65.205 127.548 65.475 ;
     RECT  169.668 65.205 213.84 65.475 ;
     RECT  2.16 65.745 41.148 66.015 ;
     RECT  83.268 65.745 127.548 66.015 ;
     RECT  169.668 65.745 213.84 66.015 ;
     RECT  2.16 66.285 41.148 66.555 ;
     RECT  83.268 66.285 127.548 66.555 ;
     RECT  169.668 66.285 213.84 66.555 ;
     RECT  2.16 66.825 41.148 67.095 ;
     RECT  83.268 66.825 127.548 67.095 ;
     RECT  169.668 66.825 213.84 67.095 ;
     RECT  2.16 67.365 41.148 67.635 ;
     RECT  83.268 67.365 127.548 67.635 ;
     RECT  169.668 67.365 213.84 67.635 ;
     RECT  2.16 67.905 41.148 68.175 ;
     RECT  83.268 67.905 127.548 68.175 ;
     RECT  169.668 67.905 213.84 68.175 ;
     RECT  2.16 68.445 41.148 68.715 ;
     RECT  83.268 68.445 127.548 68.715 ;
     RECT  169.668 68.445 213.84 68.715 ;
     RECT  2.16 68.985 41.148 69.255 ;
     RECT  83.268 68.985 127.548 69.255 ;
     RECT  169.668 68.985 213.84 69.255 ;
     RECT  2.16 69.525 41.148 69.795 ;
     RECT  83.268 69.525 127.548 69.795 ;
     RECT  169.668 69.525 213.84 69.795 ;
     RECT  2.16 70.065 41.148 70.335 ;
     RECT  83.268 70.065 127.548 70.335 ;
     RECT  169.668 70.065 213.84 70.335 ;
     RECT  2.16 70.605 41.148 70.875 ;
     RECT  83.268 70.605 127.548 70.875 ;
     RECT  169.668 70.605 213.84 70.875 ;
     RECT  2.16 71.145 41.148 71.415 ;
     RECT  83.268 71.145 127.548 71.415 ;
     RECT  169.668 71.145 213.84 71.415 ;
     RECT  2.16 71.685 41.148 71.955 ;
     RECT  83.268 71.685 127.548 71.955 ;
     RECT  169.668 71.685 213.84 71.955 ;
     RECT  2.16 72.225 41.148 72.495 ;
     RECT  83.268 72.225 127.548 72.495 ;
     RECT  169.668 72.225 213.84 72.495 ;
     RECT  2.16 72.765 41.148 73.035 ;
     RECT  83.268 72.765 127.548 73.035 ;
     RECT  169.668 72.765 213.84 73.035 ;
     RECT  2.16 73.305 41.148 73.575 ;
     RECT  83.268 73.305 127.548 73.575 ;
     RECT  169.668 73.305 213.84 73.575 ;
     RECT  2.16 73.845 41.148 74.115 ;
     RECT  83.268 73.845 127.548 74.115 ;
     RECT  169.668 73.845 213.84 74.115 ;
     RECT  2.16 74.385 41.148 74.655 ;
     RECT  83.268 74.385 127.548 74.655 ;
     RECT  169.668 74.385 213.84 74.655 ;
     RECT  2.16 74.925 41.148 75.195 ;
     RECT  83.268 74.925 127.548 75.195 ;
     RECT  169.668 74.925 213.84 75.195 ;
     RECT  2.16 75.465 41.148 75.735 ;
     RECT  83.268 75.465 127.548 75.735 ;
     RECT  169.668 75.465 213.84 75.735 ;
     RECT  2.16 76.005 41.148 76.275 ;
     RECT  83.268 76.005 127.548 76.275 ;
     RECT  169.668 76.005 213.84 76.275 ;
     RECT  2.16 76.545 41.148 76.815 ;
     RECT  83.268 76.545 127.548 76.815 ;
     RECT  169.668 76.545 213.84 76.815 ;
     RECT  2.16 77.085 41.148 77.355 ;
     RECT  83.268 77.085 127.548 77.355 ;
     RECT  169.668 77.085 213.84 77.355 ;
     RECT  2.16 77.625 41.148 77.895 ;
     RECT  83.268 77.625 127.548 77.895 ;
     RECT  169.668 77.625 213.84 77.895 ;
     RECT  2.16 78.165 41.148 78.435 ;
     RECT  83.268 78.165 127.548 78.435 ;
     RECT  169.668 78.165 213.84 78.435 ;
     RECT  2.16 78.705 41.148 78.975 ;
     RECT  83.268 78.705 127.548 78.975 ;
     RECT  169.668 78.705 213.84 78.975 ;
     RECT  2.16 79.245 41.148 79.515 ;
     RECT  83.268 79.245 127.548 79.515 ;
     RECT  169.668 79.245 213.84 79.515 ;
     RECT  2.16 79.785 41.148 80.055 ;
     RECT  83.268 79.785 127.548 80.055 ;
     RECT  169.668 79.785 213.84 80.055 ;
     RECT  2.16 80.325 41.148 80.595 ;
     RECT  83.268 80.325 127.548 80.595 ;
     RECT  169.668 80.325 213.84 80.595 ;
     RECT  2.16 80.865 41.148 81.135 ;
     RECT  83.268 80.865 127.548 81.135 ;
     RECT  169.668 80.865 213.84 81.135 ;
     RECT  2.16 81.405 41.148 81.675 ;
     RECT  83.268 81.405 127.548 81.675 ;
     RECT  169.668 81.405 213.84 81.675 ;
     RECT  2.16 81.945 41.148 82.215 ;
     RECT  83.268 81.945 127.548 82.215 ;
     RECT  169.668 81.945 213.84 82.215 ;
     RECT  2.16 82.485 41.148 82.755 ;
     RECT  83.268 82.485 127.548 82.755 ;
     RECT  169.668 82.485 213.84 82.755 ;
     RECT  2.16 83.025 41.148 83.295 ;
     RECT  83.268 83.025 127.548 83.295 ;
     RECT  169.668 83.025 213.84 83.295 ;
     RECT  2.16 83.565 41.148 83.835 ;
     RECT  83.268 83.565 127.548 83.835 ;
     RECT  169.668 83.565 213.84 83.835 ;
     RECT  2.16 84.105 41.148 84.375 ;
     RECT  83.268 84.105 127.548 84.375 ;
     RECT  169.668 84.105 213.84 84.375 ;
     RECT  2.16 84.645 41.148 84.915 ;
     RECT  83.268 84.645 127.548 84.915 ;
     RECT  169.668 84.645 213.84 84.915 ;
     RECT  2.16 85.185 41.148 85.455 ;
     RECT  83.268 85.185 127.548 85.455 ;
     RECT  169.668 85.185 213.84 85.455 ;
     RECT  2.16 85.725 41.148 85.995 ;
     RECT  83.268 85.725 127.548 85.995 ;
     RECT  169.668 85.725 213.84 85.995 ;
     RECT  2.16 86.265 41.148 86.535 ;
     RECT  83.268 86.265 127.548 86.535 ;
     RECT  169.668 86.265 213.84 86.535 ;
     RECT  2.16 86.805 41.148 87.075 ;
     RECT  83.268 86.805 127.548 87.075 ;
     RECT  169.668 86.805 213.84 87.075 ;
     RECT  2.16 87.345 41.148 87.615 ;
     RECT  83.268 87.345 127.548 87.615 ;
     RECT  169.668 87.345 213.84 87.615 ;
     RECT  2.16 87.885 41.148 88.155 ;
     RECT  83.268 87.885 127.548 88.155 ;
     RECT  169.668 87.885 213.84 88.155 ;
     RECT  2.16 88.425 41.148 88.695 ;
     RECT  83.268 88.425 127.548 88.695 ;
     RECT  169.668 88.425 213.84 88.695 ;
     RECT  2.16 88.965 41.148 89.235 ;
     RECT  83.268 88.965 127.548 89.235 ;
     RECT  169.668 88.965 213.84 89.235 ;
     RECT  2.16 89.505 41.148 89.775 ;
     RECT  83.268 89.505 127.548 89.775 ;
     RECT  169.668 89.505 213.84 89.775 ;
     RECT  2.16 90.045 41.148 90.315 ;
     RECT  83.268 90.045 127.548 90.315 ;
     RECT  169.668 90.045 213.84 90.315 ;
     RECT  2.16 90.585 41.148 90.855 ;
     RECT  83.268 90.585 127.548 90.855 ;
     RECT  169.668 90.585 213.84 90.855 ;
     RECT  2.16 91.125 41.148 91.395 ;
     RECT  83.268 91.125 127.548 91.395 ;
     RECT  169.668 91.125 213.84 91.395 ;
     RECT  2.16 91.665 41.148 91.935 ;
     RECT  83.268 91.665 127.548 91.935 ;
     RECT  169.668 91.665 213.84 91.935 ;
     RECT  2.16 92.205 41.148 92.475 ;
     RECT  83.268 92.205 127.548 92.475 ;
     RECT  169.668 92.205 213.84 92.475 ;
     RECT  2.16 92.745 41.148 93.015 ;
     RECT  83.268 92.745 127.548 93.015 ;
     RECT  169.668 92.745 213.84 93.015 ;
     RECT  2.16 93.285 41.148 93.555 ;
     RECT  83.268 93.285 127.548 93.555 ;
     RECT  169.668 93.285 213.84 93.555 ;
     RECT  2.16 93.825 41.148 94.095 ;
     RECT  83.268 93.825 127.548 94.095 ;
     RECT  169.668 93.825 213.84 94.095 ;
     RECT  2.16 94.365 41.148 94.635 ;
     RECT  83.268 94.365 127.548 94.635 ;
     RECT  169.668 94.365 213.84 94.635 ;
     RECT  2.16 94.905 41.148 95.175 ;
     RECT  83.268 94.905 127.548 95.175 ;
     RECT  169.668 94.905 213.84 95.175 ;
     RECT  2.16 95.445 41.148 95.715 ;
     RECT  83.268 95.445 127.548 95.715 ;
     RECT  169.668 95.445 213.84 95.715 ;
     RECT  2.16 95.985 41.148 96.255 ;
     RECT  83.268 95.985 127.548 96.255 ;
     RECT  169.668 95.985 213.84 96.255 ;
     RECT  2.16 96.525 41.148 96.795 ;
     RECT  83.268 96.525 127.548 96.795 ;
     RECT  169.668 96.525 213.84 96.795 ;
     RECT  2.16 97.065 41.148 97.335 ;
     RECT  83.268 97.065 127.548 97.335 ;
     RECT  169.668 97.065 213.84 97.335 ;
     RECT  2.16 97.605 41.148 97.875 ;
     RECT  83.268 97.605 127.548 97.875 ;
     RECT  169.668 97.605 213.84 97.875 ;
     RECT  2.16 98.145 41.148 98.415 ;
     RECT  83.268 98.145 127.548 98.415 ;
     RECT  169.668 98.145 213.84 98.415 ;
     RECT  2.16 98.685 41.148 98.955 ;
     RECT  83.268 98.685 127.548 98.955 ;
     RECT  169.668 98.685 213.84 98.955 ;
     RECT  2.16 99.225 41.148 99.495 ;
     RECT  83.268 99.225 127.548 99.495 ;
     RECT  169.668 99.225 213.84 99.495 ;
     RECT  2.16 99.765 41.148 100.035 ;
     RECT  83.268 99.765 127.548 100.035 ;
     RECT  169.668 99.765 213.84 100.035 ;
     RECT  2.16 100.305 41.148 100.575 ;
     RECT  83.268 100.305 127.548 100.575 ;
     RECT  169.668 100.305 213.84 100.575 ;
     RECT  2.16 100.845 41.148 101.115 ;
     RECT  83.268 100.845 127.548 101.115 ;
     RECT  169.668 100.845 213.84 101.115 ;
     RECT  2.16 101.385 41.148 101.655 ;
     RECT  83.268 101.385 127.548 101.655 ;
     RECT  169.668 101.385 213.84 101.655 ;
     RECT  2.16 101.925 41.148 102.195 ;
     RECT  83.268 101.925 127.548 102.195 ;
     RECT  169.668 101.925 213.84 102.195 ;
     RECT  2.16 102.465 41.148 102.735 ;
     RECT  83.268 102.465 127.548 102.735 ;
     RECT  169.668 102.465 213.84 102.735 ;
     RECT  2.16 103.005 41.148 103.275 ;
     RECT  83.268 103.005 127.548 103.275 ;
     RECT  169.668 103.005 213.84 103.275 ;
     RECT  2.16 103.545 41.148 103.815 ;
     RECT  83.268 103.545 127.548 103.815 ;
     RECT  169.668 103.545 213.84 103.815 ;
     RECT  2.16 104.085 41.148 104.355 ;
     RECT  83.268 104.085 127.548 104.355 ;
     RECT  169.668 104.085 213.84 104.355 ;
     RECT  2.16 104.625 41.148 104.895 ;
     RECT  83.268 104.625 127.548 104.895 ;
     RECT  169.668 104.625 213.84 104.895 ;
     RECT  2.16 105.165 41.148 105.435 ;
     RECT  83.268 105.165 127.548 105.435 ;
     RECT  169.668 105.165 213.84 105.435 ;
     RECT  2.16 105.705 41.148 105.975 ;
     RECT  83.268 105.705 127.548 105.975 ;
     RECT  169.668 105.705 213.84 105.975 ;
     RECT  2.16 106.245 41.148 106.515 ;
     RECT  83.268 106.245 127.548 106.515 ;
     RECT  169.668 106.245 213.84 106.515 ;
     RECT  2.16 106.785 41.148 107.055 ;
     RECT  83.268 106.785 127.548 107.055 ;
     RECT  169.668 106.785 213.84 107.055 ;
     RECT  2.16 107.325 41.148 107.595 ;
     RECT  83.268 107.325 127.548 107.595 ;
     RECT  169.668 107.325 213.84 107.595 ;
     RECT  2.16 107.865 41.148 108.135 ;
     RECT  83.268 107.865 127.548 108.135 ;
     RECT  169.668 107.865 213.84 108.135 ;
     RECT  2.16 108.405 213.84 108.675 ;
     RECT  2.16 108.945 213.84 109.215 ;
     RECT  2.16 109.485 213.84 109.755 ;
     RECT  2.16 110.025 213.84 110.295 ;
     RECT  2.16 110.565 213.84 110.835 ;
     RECT  2.16 111.105 213.84 111.375 ;
     RECT  2.16 111.645 213.84 111.915 ;
     RECT  2.16 112.185 213.84 112.455 ;
     RECT  2.16 112.725 213.84 112.995 ;
     RECT  2.16 113.265 213.84 113.535 ;
     RECT  2.16 113.805 213.84 114.075 ;
     RECT  2.16 114.345 213.84 114.615 ;
     RECT  2.16 114.885 213.84 115.155 ;
     RECT  2.16 115.425 213.84 115.695 ;
     RECT  2.16 115.965 213.84 116.235 ;
     RECT  2.16 116.505 213.84 116.775 ;
     RECT  2.16 117.045 213.84 117.315 ;
     RECT  2.16 117.585 213.84 117.855 ;
     RECT  2.16 118.125 213.84 118.395 ;
     RECT  2.16 118.665 213.84 118.935 ;
     RECT  2.16 119.205 213.84 119.475 ;
     RECT  2.16 119.745 213.84 120.015 ;
     RECT  2.16 120.285 213.84 120.555 ;
     RECT  2.16 120.825 213.84 121.095 ;
     RECT  2.16 121.365 213.84 121.635 ;
     RECT  2.16 121.905 213.84 122.175 ;
     RECT  2.16 122.445 213.84 122.715 ;
     RECT  2.16 122.985 213.84 123.255 ;
     RECT  2.16 123.525 213.84 123.795 ;
     RECT  2.16 124.065 213.84 124.335 ;
     RECT  2.16 124.605 213.84 124.875 ;
     RECT  2.16 125.145 213.84 125.415 ;
     RECT  2.16 125.685 213.84 125.955 ;
     RECT  2.16 126.225 213.84 126.495 ;
     RECT  2.16 126.765 213.84 127.035 ;
     RECT  2.16 127.305 213.84 127.44 ;
    LAYER RVTP ;
     RECT  2.16 2.295 213.84 2.565 ;
     RECT  2.16 2.835 213.84 3.105 ;
     RECT  2.16 3.375 213.84 3.645 ;
     RECT  2.16 3.915 213.84 4.185 ;
     RECT  2.16 4.455 213.84 4.725 ;
     RECT  2.16 4.995 213.84 5.265 ;
     RECT  2.16 5.535 213.84 5.805 ;
     RECT  2.16 6.075 213.84 6.345 ;
     RECT  2.16 6.615 213.84 6.885 ;
     RECT  2.16 7.155 213.84 7.425 ;
     RECT  2.16 7.695 213.84 7.965 ;
     RECT  2.16 8.235 213.84 8.505 ;
     RECT  2.16 8.775 213.84 9.045 ;
     RECT  2.16 9.315 213.84 9.585 ;
     RECT  2.16 9.855 213.84 10.125 ;
     RECT  2.16 10.395 213.84 10.665 ;
     RECT  2.16 10.935 213.84 11.205 ;
     RECT  2.16 11.475 213.84 11.745 ;
     RECT  2.16 12.015 213.84 12.285 ;
     RECT  2.16 12.555 213.84 12.825 ;
     RECT  2.16 13.095 213.84 13.365 ;
     RECT  2.16 13.635 213.84 13.905 ;
     RECT  2.16 14.175 213.84 14.445 ;
     RECT  2.16 14.715 213.84 14.985 ;
     RECT  2.16 15.255 213.84 15.525 ;
     RECT  2.16 15.795 213.84 16.065 ;
     RECT  2.16 16.335 213.84 16.605 ;
     RECT  2.16 16.875 213.84 17.145 ;
     RECT  2.16 17.415 213.84 17.685 ;
     RECT  2.16 17.955 213.84 18.225 ;
     RECT  2.16 18.495 213.84 18.765 ;
     RECT  2.16 19.035 213.84 19.305 ;
     RECT  2.16 19.575 213.84 19.845 ;
     RECT  2.16 20.115 213.84 20.385 ;
     RECT  2.16 20.655 213.84 20.925 ;
     RECT  2.16 21.195 213.84 21.465 ;
     RECT  2.16 21.735 213.84 22.005 ;
     RECT  2.16 22.275 213.84 22.545 ;
     RECT  2.16 22.815 213.84 23.085 ;
     RECT  2.16 23.355 213.84 23.625 ;
     RECT  2.16 23.895 213.84 24.165 ;
     RECT  2.16 24.435 213.84 24.705 ;
     RECT  2.16 24.975 213.84 25.245 ;
     RECT  2.16 25.515 213.84 25.785 ;
     RECT  2.16 26.055 213.84 26.325 ;
     RECT  2.16 26.595 213.84 26.865 ;
     RECT  2.16 27.135 213.84 27.405 ;
     RECT  2.16 27.675 213.84 27.945 ;
     RECT  2.16 28.215 213.84 28.485 ;
     RECT  2.16 28.755 213.84 29.025 ;
     RECT  2.16 29.295 213.84 29.565 ;
     RECT  2.16 29.835 213.84 30.105 ;
     RECT  2.16 30.375 213.84 30.645 ;
     RECT  2.16 30.915 213.84 31.185 ;
     RECT  2.16 31.455 213.84 31.725 ;
     RECT  2.16 31.995 213.84 32.265 ;
     RECT  2.16 32.535 213.84 32.805 ;
     RECT  2.16 33.075 213.84 33.345 ;
     RECT  2.16 33.615 213.84 33.885 ;
     RECT  2.16 34.155 213.84 34.425 ;
     RECT  2.16 34.695 213.84 34.965 ;
     RECT  2.16 35.235 213.84 35.505 ;
     RECT  2.16 35.775 213.84 36.045 ;
     RECT  2.16 36.315 213.84 36.585 ;
     RECT  2.16 36.855 213.84 37.125 ;
     RECT  2.16 37.395 213.84 37.665 ;
     RECT  2.16 37.935 213.84 38.205 ;
     RECT  2.16 38.475 213.84 38.745 ;
     RECT  2.16 39.015 213.84 39.285 ;
     RECT  2.16 39.555 213.84 39.825 ;
     RECT  2.16 40.095 213.84 40.365 ;
     RECT  2.16 40.635 213.84 40.905 ;
     RECT  2.16 41.175 41.148 41.445 ;
     RECT  83.268 41.175 127.548 41.445 ;
     RECT  169.668 41.175 213.84 41.445 ;
     RECT  2.16 41.715 41.148 41.985 ;
     RECT  83.268 41.715 127.548 41.985 ;
     RECT  169.668 41.715 213.84 41.985 ;
     RECT  2.16 42.255 41.148 42.525 ;
     RECT  83.268 42.255 127.548 42.525 ;
     RECT  169.668 42.255 213.84 42.525 ;
     RECT  2.16 42.795 41.148 43.065 ;
     RECT  83.268 42.795 127.548 43.065 ;
     RECT  169.668 42.795 213.84 43.065 ;
     RECT  2.16 43.335 41.148 43.605 ;
     RECT  83.268 43.335 127.548 43.605 ;
     RECT  169.668 43.335 213.84 43.605 ;
     RECT  2.16 43.875 41.148 44.145 ;
     RECT  83.268 43.875 127.548 44.145 ;
     RECT  169.668 43.875 213.84 44.145 ;
     RECT  2.16 44.415 41.148 44.685 ;
     RECT  83.268 44.415 127.548 44.685 ;
     RECT  169.668 44.415 213.84 44.685 ;
     RECT  2.16 44.955 41.148 45.225 ;
     RECT  83.268 44.955 127.548 45.225 ;
     RECT  169.668 44.955 213.84 45.225 ;
     RECT  2.16 45.495 41.148 45.765 ;
     RECT  83.268 45.495 127.548 45.765 ;
     RECT  169.668 45.495 213.84 45.765 ;
     RECT  2.16 46.035 41.148 46.305 ;
     RECT  83.268 46.035 127.548 46.305 ;
     RECT  169.668 46.035 213.84 46.305 ;
     RECT  2.16 46.575 41.148 46.845 ;
     RECT  83.268 46.575 127.548 46.845 ;
     RECT  169.668 46.575 213.84 46.845 ;
     RECT  2.16 47.115 41.148 47.385 ;
     RECT  83.268 47.115 127.548 47.385 ;
     RECT  169.668 47.115 213.84 47.385 ;
     RECT  2.16 47.655 41.148 47.925 ;
     RECT  83.268 47.655 127.548 47.925 ;
     RECT  169.668 47.655 213.84 47.925 ;
     RECT  2.16 48.195 41.148 48.465 ;
     RECT  83.268 48.195 127.548 48.465 ;
     RECT  169.668 48.195 213.84 48.465 ;
     RECT  2.16 48.735 41.148 49.005 ;
     RECT  83.268 48.735 127.548 49.005 ;
     RECT  169.668 48.735 213.84 49.005 ;
     RECT  2.16 49.275 41.148 49.545 ;
     RECT  83.268 49.275 127.548 49.545 ;
     RECT  169.668 49.275 213.84 49.545 ;
     RECT  2.16 49.815 41.148 50.085 ;
     RECT  83.268 49.815 127.548 50.085 ;
     RECT  169.668 49.815 213.84 50.085 ;
     RECT  2.16 50.355 41.148 50.625 ;
     RECT  83.268 50.355 127.548 50.625 ;
     RECT  169.668 50.355 213.84 50.625 ;
     RECT  2.16 50.895 41.148 51.165 ;
     RECT  83.268 50.895 127.548 51.165 ;
     RECT  169.668 50.895 213.84 51.165 ;
     RECT  2.16 51.435 41.148 51.705 ;
     RECT  83.268 51.435 127.548 51.705 ;
     RECT  169.668 51.435 213.84 51.705 ;
     RECT  2.16 51.975 41.148 52.245 ;
     RECT  83.268 51.975 127.548 52.245 ;
     RECT  169.668 51.975 213.84 52.245 ;
     RECT  2.16 52.515 41.148 52.785 ;
     RECT  83.268 52.515 127.548 52.785 ;
     RECT  169.668 52.515 213.84 52.785 ;
     RECT  2.16 53.055 41.148 53.325 ;
     RECT  83.268 53.055 127.548 53.325 ;
     RECT  169.668 53.055 213.84 53.325 ;
     RECT  2.16 53.595 41.148 53.865 ;
     RECT  83.268 53.595 127.548 53.865 ;
     RECT  169.668 53.595 213.84 53.865 ;
     RECT  2.16 54.135 41.148 54.405 ;
     RECT  83.268 54.135 127.548 54.405 ;
     RECT  169.668 54.135 213.84 54.405 ;
     RECT  2.16 54.675 41.148 54.945 ;
     RECT  83.268 54.675 127.548 54.945 ;
     RECT  169.668 54.675 213.84 54.945 ;
     RECT  2.16 55.215 41.148 55.485 ;
     RECT  83.268 55.215 127.548 55.485 ;
     RECT  169.668 55.215 213.84 55.485 ;
     RECT  2.16 55.755 41.148 56.025 ;
     RECT  83.268 55.755 127.548 56.025 ;
     RECT  169.668 55.755 213.84 56.025 ;
     RECT  2.16 56.295 41.148 56.565 ;
     RECT  83.268 56.295 127.548 56.565 ;
     RECT  169.668 56.295 213.84 56.565 ;
     RECT  2.16 56.835 41.148 57.105 ;
     RECT  83.268 56.835 127.548 57.105 ;
     RECT  169.668 56.835 213.84 57.105 ;
     RECT  2.16 57.375 41.148 57.645 ;
     RECT  83.268 57.375 127.548 57.645 ;
     RECT  169.668 57.375 213.84 57.645 ;
     RECT  2.16 57.915 41.148 58.185 ;
     RECT  83.268 57.915 127.548 58.185 ;
     RECT  169.668 57.915 213.84 58.185 ;
     RECT  2.16 58.455 41.148 58.725 ;
     RECT  83.268 58.455 127.548 58.725 ;
     RECT  169.668 58.455 213.84 58.725 ;
     RECT  2.16 58.995 41.148 59.265 ;
     RECT  83.268 58.995 127.548 59.265 ;
     RECT  169.668 58.995 213.84 59.265 ;
     RECT  2.16 59.535 41.148 59.805 ;
     RECT  83.268 59.535 127.548 59.805 ;
     RECT  169.668 59.535 213.84 59.805 ;
     RECT  2.16 60.075 41.148 60.345 ;
     RECT  83.268 60.075 127.548 60.345 ;
     RECT  169.668 60.075 213.84 60.345 ;
     RECT  2.16 60.615 41.148 60.885 ;
     RECT  83.268 60.615 127.548 60.885 ;
     RECT  169.668 60.615 213.84 60.885 ;
     RECT  2.16 61.155 41.148 61.425 ;
     RECT  83.268 61.155 127.548 61.425 ;
     RECT  169.668 61.155 213.84 61.425 ;
     RECT  2.16 61.695 41.148 61.965 ;
     RECT  83.268 61.695 127.548 61.965 ;
     RECT  169.668 61.695 213.84 61.965 ;
     RECT  2.16 62.235 41.148 62.505 ;
     RECT  83.268 62.235 127.548 62.505 ;
     RECT  169.668 62.235 213.84 62.505 ;
     RECT  2.16 62.775 41.148 63.045 ;
     RECT  83.268 62.775 127.548 63.045 ;
     RECT  169.668 62.775 213.84 63.045 ;
     RECT  2.16 63.315 41.148 63.585 ;
     RECT  83.268 63.315 127.548 63.585 ;
     RECT  169.668 63.315 213.84 63.585 ;
     RECT  2.16 63.855 41.148 64.125 ;
     RECT  83.268 63.855 127.548 64.125 ;
     RECT  169.668 63.855 213.84 64.125 ;
     RECT  2.16 64.395 41.148 64.665 ;
     RECT  83.268 64.395 127.548 64.665 ;
     RECT  169.668 64.395 213.84 64.665 ;
     RECT  2.16 64.935 41.148 65.205 ;
     RECT  83.268 64.935 127.548 65.205 ;
     RECT  169.668 64.935 213.84 65.205 ;
     RECT  2.16 65.475 41.148 65.745 ;
     RECT  83.268 65.475 127.548 65.745 ;
     RECT  169.668 65.475 213.84 65.745 ;
     RECT  2.16 66.015 41.148 66.285 ;
     RECT  83.268 66.015 127.548 66.285 ;
     RECT  169.668 66.015 213.84 66.285 ;
     RECT  2.16 66.555 41.148 66.825 ;
     RECT  83.268 66.555 127.548 66.825 ;
     RECT  169.668 66.555 213.84 66.825 ;
     RECT  2.16 67.095 41.148 67.365 ;
     RECT  83.268 67.095 127.548 67.365 ;
     RECT  169.668 67.095 213.84 67.365 ;
     RECT  2.16 67.635 41.148 67.905 ;
     RECT  83.268 67.635 127.548 67.905 ;
     RECT  169.668 67.635 213.84 67.905 ;
     RECT  2.16 68.175 41.148 68.445 ;
     RECT  83.268 68.175 127.548 68.445 ;
     RECT  169.668 68.175 213.84 68.445 ;
     RECT  2.16 68.715 41.148 68.985 ;
     RECT  83.268 68.715 127.548 68.985 ;
     RECT  169.668 68.715 213.84 68.985 ;
     RECT  2.16 69.255 41.148 69.525 ;
     RECT  83.268 69.255 127.548 69.525 ;
     RECT  169.668 69.255 213.84 69.525 ;
     RECT  2.16 69.795 41.148 70.065 ;
     RECT  83.268 69.795 127.548 70.065 ;
     RECT  169.668 69.795 213.84 70.065 ;
     RECT  2.16 70.335 41.148 70.605 ;
     RECT  83.268 70.335 127.548 70.605 ;
     RECT  169.668 70.335 213.84 70.605 ;
     RECT  2.16 70.875 41.148 71.145 ;
     RECT  83.268 70.875 127.548 71.145 ;
     RECT  169.668 70.875 213.84 71.145 ;
     RECT  2.16 71.415 41.148 71.685 ;
     RECT  83.268 71.415 127.548 71.685 ;
     RECT  169.668 71.415 213.84 71.685 ;
     RECT  2.16 71.955 41.148 72.225 ;
     RECT  83.268 71.955 127.548 72.225 ;
     RECT  169.668 71.955 213.84 72.225 ;
     RECT  2.16 72.495 41.148 72.765 ;
     RECT  83.268 72.495 127.548 72.765 ;
     RECT  169.668 72.495 213.84 72.765 ;
     RECT  2.16 73.035 41.148 73.305 ;
     RECT  83.268 73.035 127.548 73.305 ;
     RECT  169.668 73.035 213.84 73.305 ;
     RECT  2.16 73.575 41.148 73.845 ;
     RECT  83.268 73.575 127.548 73.845 ;
     RECT  169.668 73.575 213.84 73.845 ;
     RECT  2.16 74.115 41.148 74.385 ;
     RECT  83.268 74.115 127.548 74.385 ;
     RECT  169.668 74.115 213.84 74.385 ;
     RECT  2.16 74.655 41.148 74.925 ;
     RECT  83.268 74.655 127.548 74.925 ;
     RECT  169.668 74.655 213.84 74.925 ;
     RECT  2.16 75.195 41.148 75.465 ;
     RECT  83.268 75.195 127.548 75.465 ;
     RECT  169.668 75.195 213.84 75.465 ;
     RECT  2.16 75.735 41.148 76.005 ;
     RECT  83.268 75.735 127.548 76.005 ;
     RECT  169.668 75.735 213.84 76.005 ;
     RECT  2.16 76.275 41.148 76.545 ;
     RECT  83.268 76.275 127.548 76.545 ;
     RECT  169.668 76.275 213.84 76.545 ;
     RECT  2.16 76.815 41.148 77.085 ;
     RECT  83.268 76.815 127.548 77.085 ;
     RECT  169.668 76.815 213.84 77.085 ;
     RECT  2.16 77.355 41.148 77.625 ;
     RECT  83.268 77.355 127.548 77.625 ;
     RECT  169.668 77.355 213.84 77.625 ;
     RECT  2.16 77.895 41.148 78.165 ;
     RECT  83.268 77.895 127.548 78.165 ;
     RECT  169.668 77.895 213.84 78.165 ;
     RECT  2.16 78.435 41.148 78.705 ;
     RECT  83.268 78.435 127.548 78.705 ;
     RECT  169.668 78.435 213.84 78.705 ;
     RECT  2.16 78.975 41.148 79.245 ;
     RECT  83.268 78.975 127.548 79.245 ;
     RECT  169.668 78.975 213.84 79.245 ;
     RECT  2.16 79.515 41.148 79.785 ;
     RECT  83.268 79.515 127.548 79.785 ;
     RECT  169.668 79.515 213.84 79.785 ;
     RECT  2.16 80.055 41.148 80.325 ;
     RECT  83.268 80.055 127.548 80.325 ;
     RECT  169.668 80.055 213.84 80.325 ;
     RECT  2.16 80.595 41.148 80.865 ;
     RECT  83.268 80.595 127.548 80.865 ;
     RECT  169.668 80.595 213.84 80.865 ;
     RECT  2.16 81.135 41.148 81.405 ;
     RECT  83.268 81.135 127.548 81.405 ;
     RECT  169.668 81.135 213.84 81.405 ;
     RECT  2.16 81.675 41.148 81.945 ;
     RECT  83.268 81.675 127.548 81.945 ;
     RECT  169.668 81.675 213.84 81.945 ;
     RECT  2.16 82.215 41.148 82.485 ;
     RECT  83.268 82.215 127.548 82.485 ;
     RECT  169.668 82.215 213.84 82.485 ;
     RECT  2.16 82.755 41.148 83.025 ;
     RECT  83.268 82.755 127.548 83.025 ;
     RECT  169.668 82.755 213.84 83.025 ;
     RECT  2.16 83.295 41.148 83.565 ;
     RECT  83.268 83.295 127.548 83.565 ;
     RECT  169.668 83.295 213.84 83.565 ;
     RECT  2.16 83.835 41.148 84.105 ;
     RECT  83.268 83.835 127.548 84.105 ;
     RECT  169.668 83.835 213.84 84.105 ;
     RECT  2.16 84.375 41.148 84.645 ;
     RECT  83.268 84.375 127.548 84.645 ;
     RECT  169.668 84.375 213.84 84.645 ;
     RECT  2.16 84.915 41.148 85.185 ;
     RECT  83.268 84.915 127.548 85.185 ;
     RECT  169.668 84.915 213.84 85.185 ;
     RECT  2.16 85.455 41.148 85.725 ;
     RECT  83.268 85.455 127.548 85.725 ;
     RECT  169.668 85.455 213.84 85.725 ;
     RECT  2.16 85.995 41.148 86.265 ;
     RECT  83.268 85.995 127.548 86.265 ;
     RECT  169.668 85.995 213.84 86.265 ;
     RECT  2.16 86.535 41.148 86.805 ;
     RECT  83.268 86.535 127.548 86.805 ;
     RECT  169.668 86.535 213.84 86.805 ;
     RECT  2.16 87.075 41.148 87.345 ;
     RECT  83.268 87.075 127.548 87.345 ;
     RECT  169.668 87.075 213.84 87.345 ;
     RECT  2.16 87.615 41.148 87.885 ;
     RECT  83.268 87.615 127.548 87.885 ;
     RECT  169.668 87.615 213.84 87.885 ;
     RECT  2.16 88.155 41.148 88.425 ;
     RECT  83.268 88.155 127.548 88.425 ;
     RECT  169.668 88.155 213.84 88.425 ;
     RECT  2.16 88.695 41.148 88.965 ;
     RECT  83.268 88.695 127.548 88.965 ;
     RECT  169.668 88.695 213.84 88.965 ;
     RECT  2.16 89.235 41.148 89.505 ;
     RECT  83.268 89.235 127.548 89.505 ;
     RECT  169.668 89.235 213.84 89.505 ;
     RECT  2.16 89.775 41.148 90.045 ;
     RECT  83.268 89.775 127.548 90.045 ;
     RECT  169.668 89.775 213.84 90.045 ;
     RECT  2.16 90.315 41.148 90.585 ;
     RECT  83.268 90.315 127.548 90.585 ;
     RECT  169.668 90.315 213.84 90.585 ;
     RECT  2.16 90.855 41.148 91.125 ;
     RECT  83.268 90.855 127.548 91.125 ;
     RECT  169.668 90.855 213.84 91.125 ;
     RECT  2.16 91.395 41.148 91.665 ;
     RECT  83.268 91.395 127.548 91.665 ;
     RECT  169.668 91.395 213.84 91.665 ;
     RECT  2.16 91.935 41.148 92.205 ;
     RECT  83.268 91.935 127.548 92.205 ;
     RECT  169.668 91.935 213.84 92.205 ;
     RECT  2.16 92.475 41.148 92.745 ;
     RECT  83.268 92.475 127.548 92.745 ;
     RECT  169.668 92.475 213.84 92.745 ;
     RECT  2.16 93.015 41.148 93.285 ;
     RECT  83.268 93.015 127.548 93.285 ;
     RECT  169.668 93.015 213.84 93.285 ;
     RECT  2.16 93.555 41.148 93.825 ;
     RECT  83.268 93.555 127.548 93.825 ;
     RECT  169.668 93.555 213.84 93.825 ;
     RECT  2.16 94.095 41.148 94.365 ;
     RECT  83.268 94.095 127.548 94.365 ;
     RECT  169.668 94.095 213.84 94.365 ;
     RECT  2.16 94.635 41.148 94.905 ;
     RECT  83.268 94.635 127.548 94.905 ;
     RECT  169.668 94.635 213.84 94.905 ;
     RECT  2.16 95.175 41.148 95.445 ;
     RECT  83.268 95.175 127.548 95.445 ;
     RECT  169.668 95.175 213.84 95.445 ;
     RECT  2.16 95.715 41.148 95.985 ;
     RECT  83.268 95.715 127.548 95.985 ;
     RECT  169.668 95.715 213.84 95.985 ;
     RECT  2.16 96.255 41.148 96.525 ;
     RECT  83.268 96.255 127.548 96.525 ;
     RECT  169.668 96.255 213.84 96.525 ;
     RECT  2.16 96.795 41.148 97.065 ;
     RECT  83.268 96.795 127.548 97.065 ;
     RECT  169.668 96.795 213.84 97.065 ;
     RECT  2.16 97.335 41.148 97.605 ;
     RECT  83.268 97.335 127.548 97.605 ;
     RECT  169.668 97.335 213.84 97.605 ;
     RECT  2.16 97.875 41.148 98.145 ;
     RECT  83.268 97.875 127.548 98.145 ;
     RECT  169.668 97.875 213.84 98.145 ;
     RECT  2.16 98.415 41.148 98.685 ;
     RECT  83.268 98.415 127.548 98.685 ;
     RECT  169.668 98.415 213.84 98.685 ;
     RECT  2.16 98.955 41.148 99.225 ;
     RECT  83.268 98.955 127.548 99.225 ;
     RECT  169.668 98.955 213.84 99.225 ;
     RECT  2.16 99.495 41.148 99.765 ;
     RECT  83.268 99.495 127.548 99.765 ;
     RECT  169.668 99.495 213.84 99.765 ;
     RECT  2.16 100.035 41.148 100.305 ;
     RECT  83.268 100.035 127.548 100.305 ;
     RECT  169.668 100.035 213.84 100.305 ;
     RECT  2.16 100.575 41.148 100.845 ;
     RECT  83.268 100.575 127.548 100.845 ;
     RECT  169.668 100.575 213.84 100.845 ;
     RECT  2.16 101.115 41.148 101.385 ;
     RECT  83.268 101.115 127.548 101.385 ;
     RECT  169.668 101.115 213.84 101.385 ;
     RECT  2.16 101.655 41.148 101.925 ;
     RECT  83.268 101.655 127.548 101.925 ;
     RECT  169.668 101.655 213.84 101.925 ;
     RECT  2.16 102.195 41.148 102.465 ;
     RECT  83.268 102.195 127.548 102.465 ;
     RECT  169.668 102.195 213.84 102.465 ;
     RECT  2.16 102.735 41.148 103.005 ;
     RECT  83.268 102.735 127.548 103.005 ;
     RECT  169.668 102.735 213.84 103.005 ;
     RECT  2.16 103.275 41.148 103.545 ;
     RECT  83.268 103.275 127.548 103.545 ;
     RECT  169.668 103.275 213.84 103.545 ;
     RECT  2.16 103.815 41.148 104.085 ;
     RECT  83.268 103.815 127.548 104.085 ;
     RECT  169.668 103.815 213.84 104.085 ;
     RECT  2.16 104.355 41.148 104.625 ;
     RECT  83.268 104.355 127.548 104.625 ;
     RECT  169.668 104.355 213.84 104.625 ;
     RECT  2.16 104.895 41.148 105.165 ;
     RECT  83.268 104.895 127.548 105.165 ;
     RECT  169.668 104.895 213.84 105.165 ;
     RECT  2.16 105.435 41.148 105.705 ;
     RECT  83.268 105.435 127.548 105.705 ;
     RECT  169.668 105.435 213.84 105.705 ;
     RECT  2.16 105.975 41.148 106.245 ;
     RECT  83.268 105.975 127.548 106.245 ;
     RECT  169.668 105.975 213.84 106.245 ;
     RECT  2.16 106.515 41.148 106.785 ;
     RECT  83.268 106.515 127.548 106.785 ;
     RECT  169.668 106.515 213.84 106.785 ;
     RECT  2.16 107.055 41.148 107.325 ;
     RECT  83.268 107.055 127.548 107.325 ;
     RECT  169.668 107.055 213.84 107.325 ;
     RECT  2.16 107.595 41.148 107.865 ;
     RECT  83.268 107.595 127.548 107.865 ;
     RECT  169.668 107.595 213.84 107.865 ;
     RECT  2.16 108.135 41.148 108.27 ;
     RECT  83.268 108.135 127.548 108.27 ;
     RECT  169.668 108.135 213.84 108.27 ;
     RECT  2.16 108.27 213.84 108.405 ;
     RECT  2.16 108.675 213.84 108.945 ;
     RECT  2.16 109.215 213.84 109.485 ;
     RECT  2.16 109.755 213.84 110.025 ;
     RECT  2.16 110.295 213.84 110.565 ;
     RECT  2.16 110.835 213.84 111.105 ;
     RECT  2.16 111.375 213.84 111.645 ;
     RECT  2.16 111.915 213.84 112.185 ;
     RECT  2.16 112.455 213.84 112.725 ;
     RECT  2.16 112.995 213.84 113.265 ;
     RECT  2.16 113.535 213.84 113.805 ;
     RECT  2.16 114.075 213.84 114.345 ;
     RECT  2.16 114.615 213.84 114.885 ;
     RECT  2.16 115.155 213.84 115.425 ;
     RECT  2.16 115.695 213.84 115.965 ;
     RECT  2.16 116.235 213.84 116.505 ;
     RECT  2.16 116.775 213.84 117.045 ;
     RECT  2.16 117.315 213.84 117.585 ;
     RECT  2.16 117.855 213.84 118.125 ;
     RECT  2.16 118.395 213.84 118.665 ;
     RECT  2.16 118.935 213.84 119.205 ;
     RECT  2.16 119.475 213.84 119.745 ;
     RECT  2.16 120.015 213.84 120.285 ;
     RECT  2.16 120.555 213.84 120.825 ;
     RECT  2.16 121.095 213.84 121.365 ;
     RECT  2.16 121.635 213.84 121.905 ;
     RECT  2.16 122.175 213.84 122.445 ;
     RECT  2.16 122.715 213.84 122.985 ;
     RECT  2.16 123.255 213.84 123.525 ;
     RECT  2.16 123.795 213.84 124.065 ;
     RECT  2.16 124.335 213.84 124.605 ;
     RECT  2.16 124.875 213.84 125.145 ;
     RECT  2.16 125.415 213.84 125.685 ;
     RECT  2.16 125.955 213.84 126.225 ;
     RECT  2.16 126.495 213.84 126.765 ;
     RECT  2.16 127.035 213.84 127.305 ;
    LAYER M1 ;
     RECT  2.16 2.151 213.84 41.049 ;
     RECT  43.2 43.2 81.216 106.11 ;
     RECT  129.6 43.2 167.616 106.11 ;
     RECT  2.16 41.049 41.148 108.261 ;
     RECT  83.268 41.049 127.548 108.261 ;
     RECT  169.668 41.049 213.84 108.261 ;
     RECT  2.16 108.261 213.84 127.449 ;
    LAYER M2 ;
     RECT  0.211 5.616 2.16 5.634 ;
     RECT  0.211 10.476 2.16 10.494 ;
     RECT  0.211 15.606 2.16 15.624 ;
     RECT  0.211 18.036 2.16 18.054 ;
     RECT  0.211 20.736 2.16 20.754 ;
     RECT  0.211 23.256 2.16 23.274 ;
     RECT  0.535 25.866 2.16 25.884 ;
     RECT  0.211 28.296 2.16 28.314 ;
     RECT  1.723 30.726 2.16 30.744 ;
     RECT  0.211 33.426 2.16 33.444 ;
     RECT  0.535 40.986 2.16 41.004 ;
     RECT  0.535 46.116 2.16 46.134 ;
     RECT  0.211 50.976 2.16 50.994 ;
     RECT  0.211 53.496 2.16 53.514 ;
     RECT  1.723 55.836 2.16 55.854 ;
     RECT  1.723 60.966 2.16 60.984 ;
     RECT  0.211 63.666 2.16 63.684 ;
     RECT  0.535 66.096 2.16 66.114 ;
     RECT  0.535 68.796 2.16 68.814 ;
     RECT  0.535 71.226 2.16 71.244 ;
     RECT  0.211 76.086 2.16 76.104 ;
     RECT  0.211 81.216 2.16 81.234 ;
     RECT  0.211 83.736 2.16 83.754 ;
     RECT  0.211 86.346 2.16 86.364 ;
     RECT  0.211 88.776 2.16 88.794 ;
     RECT  0.211 93.906 2.16 93.924 ;
     RECT  0.211 99.036 2.16 99.054 ;
     RECT  0.211 101.286 2.16 101.304 ;
     RECT  0.211 106.326 2.16 106.344 ;
     RECT  0.535 109.224 2.16 109.242 ;
     RECT  0.211 111.456 2.16 111.474 ;
     RECT  0.211 113.886 2.16 113.904 ;
     RECT  0.211 118.746 2.16 118.764 ;
     RECT  1.723 121.176 2.16 121.194 ;
     RECT  2.16 2.151 41.148 127.449 ;
     RECT  41.148 2.151 41.315 49.23 ;
     RECT  41.315 2.151 41.567 48.294 ;
     RECT  41.148 71.082 41.891 71.1 ;
     RECT  41.148 81.342 41.891 81.36 ;
     RECT  41.148 68.256 41.927 68.274 ;
     RECT  41.148 58.356 41.963 58.374 ;
     RECT  41.148 89.982 41.963 90 ;
     RECT  41.148 57.276 41.999 57.438 ;
     RECT  41.148 90.864 42.035 90.882 ;
     RECT  41.999 57.276 42.071 57.294 ;
     RECT  41.148 106.146 42.503 107.118 ;
     RECT  42.503 106.146 42.511 106.884 ;
     RECT  42.511 106.101 42.619 106.884 ;
     RECT  41.567 2.151 43.2 48.114 ;
     RECT  41.315 49.086 43.2 49.23 ;
     RECT  41.148 94.104 43.2 94.86 ;
     RECT  41.148 98.586 43.2 99.18 ;
     RECT  42.619 106.02 43.2 106.884 ;
     RECT  43.2 2.151 81.216 106.884 ;
     RECT  81.216 44.154 82.903 44.172 ;
     RECT  81.216 2.151 83.011 43.29 ;
     RECT  82.903 44.154 83.011 44.244 ;
     RECT  83.011 2.151 83.268 44.244 ;
     RECT  81.216 53.226 83.268 53.244 ;
     RECT  81.216 68.418 83.268 68.436 ;
     RECT  81.216 98.586 83.268 98.604 ;
     RECT  81.216 106.146 83.268 106.884 ;
     RECT  41.148 108.261 83.268 127.449 ;
     RECT  83.268 2.151 127.548 127.449 ;
     RECT  127.548 42.606 127.679 48.114 ;
     RECT  127.548 95.112 127.967 95.13 ;
     RECT  127.548 41.796 128.515 41.814 ;
     RECT  127.679 42.606 128.515 47.988 ;
     RECT  127.548 106.146 128.515 106.614 ;
     RECT  127.548 57.042 128.543 58.284 ;
     RECT  127.548 74.052 128.543 74.07 ;
     RECT  128.543 57.042 128.579 57.6 ;
     RECT  128.515 106.146 128.587 106.659 ;
     RECT  128.579 57.582 128.615 57.6 ;
     RECT  127.548 87.552 128.615 87.57 ;
     RECT  128.587 106.146 128.623 106.74 ;
     RECT  127.548 90.252 128.687 90.27 ;
     RECT  128.515 41.796 128.831 47.988 ;
     RECT  128.831 41.796 129.6 44.244 ;
     RECT  128.831 45.27 129.6 47.988 ;
     RECT  127.548 52.326 129.6 53.28 ;
     RECT  127.548 98.586 129.6 98.604 ;
     RECT  128.623 106.146 129.6 106.776 ;
     RECT  129.6 41.796 167.616 106.776 ;
     RECT  127.548 2.151 169.668 41.049 ;
     RECT  167.616 41.796 169.668 43.704 ;
     RECT  167.616 44.856 169.668 44.874 ;
     RECT  167.616 106.146 169.668 106.776 ;
     RECT  127.548 108.261 169.668 127.449 ;
     RECT  169.668 2.151 213.84 127.449 ;
     RECT  213.84 19.548 214.259 19.566 ;
     RECT  213.84 33.318 214.259 33.336 ;
     RECT  213.84 36.018 214.259 36.036 ;
     RECT  213.84 63.558 214.259 63.576 ;
     RECT  213.84 66.258 214.259 66.276 ;
     RECT  213.84 68.958 214.259 68.976 ;
     RECT  213.84 93.798 214.259 93.816 ;
     RECT  213.84 121.338 214.259 121.356 ;
     RECT  213.84 124.038 214.259 124.056 ;
     RECT  213.84 41.418 214.331 41.436 ;
     RECT  213.84 57.924 214.331 57.942 ;
     RECT  213.84 101.898 214.331 101.916 ;
     RECT  213.84 107.568 214.331 107.586 ;
     RECT  213.84 112.968 214.331 112.986 ;
     RECT  213.84 118.404 214.331 118.422 ;
     RECT  213.84 8.442 214.367 8.46 ;
     RECT  213.84 11.106 214.367 11.124 ;
     RECT  213.84 13.986 214.367 14.004 ;
     RECT  213.84 16.848 214.367 16.866 ;
     RECT  213.84 27.72 214.367 27.738 ;
     RECT  213.84 30.69 214.367 30.708 ;
     RECT  213.84 38.718 214.367 38.736 ;
     RECT  213.84 44.388 214.367 44.406 ;
     RECT  213.84 47.088 214.367 47.106 ;
     RECT  213.84 49.86 214.367 49.878 ;
     RECT  213.84 52.56 214.367 52.578 ;
     RECT  213.84 55.26 214.367 55.278 ;
     RECT  213.84 71.73 214.367 71.748 ;
     RECT  213.84 74.43 214.367 74.448 ;
     RECT  213.84 77.4 214.367 77.418 ;
     RECT  213.84 82.8 214.367 82.818 ;
     RECT  213.84 85.428 214.367 85.446 ;
     RECT  213.84 88.164 214.367 88.182 ;
     RECT  213.84 96.498 214.367 96.516 ;
     RECT  213.84 104.868 214.367 104.886 ;
     RECT  213.84 115.668 214.367 115.686 ;
     RECT  213.84 5.616 214.907 5.634 ;
     RECT  213.84 22.212 214.907 22.23 ;
     RECT  213.84 99.162 214.907 99.18 ;
    LAYER M3 ;
     RECT  108 0.108 108.018 0.173 ;
     RECT  190.944 0.108 190.962 2.143 ;
     RECT  25.056 0.108 25.074 2.255 ;
     RECT  66.276 1.723 66.294 2.255 ;
     RECT  149.22 0.187 149.238 2.255 ;
     RECT  67.215 2.143 67.305 2.371 ;
     RECT  190.944 2.143 191.505 2.371 ;
     RECT  2.415 2.143 2.505 2.413 ;
     RECT  5.115 2.143 5.205 2.413 ;
     RECT  7.815 2.143 7.905 2.413 ;
     RECT  10.515 2.143 10.605 2.413 ;
     RECT  13.215 2.143 13.305 2.413 ;
     RECT  15.915 2.143 16.005 2.413 ;
     RECT  18.615 2.143 18.705 2.413 ;
     RECT  21.315 2.143 21.405 2.413 ;
     RECT  24.015 2.143 24.105 2.413 ;
     RECT  26.715 2.143 26.805 2.413 ;
     RECT  29.415 2.143 29.505 2.413 ;
     RECT  32.115 2.143 32.205 2.413 ;
     RECT  34.815 2.143 34.905 2.413 ;
     RECT  37.515 2.143 37.605 2.413 ;
     RECT  40.215 2.143 40.305 2.413 ;
     RECT  42.915 2.143 43.005 2.413 ;
     RECT  45.615 2.143 45.705 2.413 ;
     RECT  48.315 2.143 48.405 2.413 ;
     RECT  51.015 2.143 51.105 2.413 ;
     RECT  53.715 2.143 53.805 2.413 ;
     RECT  56.415 2.143 56.505 2.413 ;
     RECT  59.115 2.143 59.205 2.413 ;
     RECT  61.815 2.143 61.905 2.413 ;
     RECT  64.515 2.143 64.605 2.413 ;
     RECT  66.78 2.371 67.305 2.413 ;
     RECT  69.915 2.143 70.005 2.413 ;
     RECT  72.615 2.143 72.705 2.413 ;
     RECT  75.315 2.143 75.405 2.413 ;
     RECT  78.015 2.143 78.105 2.413 ;
     RECT  80.715 2.143 80.805 2.413 ;
     RECT  83.415 2.143 83.505 2.413 ;
     RECT  86.115 2.143 86.205 2.413 ;
     RECT  88.815 2.143 88.905 2.413 ;
     RECT  91.515 2.143 91.605 2.413 ;
     RECT  94.215 2.143 94.305 2.413 ;
     RECT  96.915 2.143 97.005 2.413 ;
     RECT  99.615 2.143 99.705 2.413 ;
     RECT  102.315 2.143 102.405 2.413 ;
     RECT  105.015 2.143 105.105 2.413 ;
     RECT  107.715 2.143 107.805 2.413 ;
     RECT  110.415 2.143 110.505 2.413 ;
     RECT  113.115 2.143 113.205 2.413 ;
     RECT  115.815 2.143 115.905 2.413 ;
     RECT  118.515 2.143 118.605 2.413 ;
     RECT  121.215 2.143 121.305 2.413 ;
     RECT  123.915 2.143 124.005 2.413 ;
     RECT  126.615 2.143 126.705 2.413 ;
     RECT  129.315 2.143 129.405 2.413 ;
     RECT  132.015 2.143 132.105 2.413 ;
     RECT  134.715 2.143 134.805 2.413 ;
     RECT  137.415 2.143 137.505 2.413 ;
     RECT  140.115 2.143 140.205 2.413 ;
     RECT  142.815 2.143 142.905 2.413 ;
     RECT  145.515 2.143 145.605 2.413 ;
     RECT  148.215 2.143 148.305 2.413 ;
     RECT  150.915 2.143 151.005 2.413 ;
     RECT  153.615 2.143 153.705 2.413 ;
     RECT  156.315 2.143 156.405 2.413 ;
     RECT  159.015 2.143 159.105 2.413 ;
     RECT  161.715 2.143 161.805 2.413 ;
     RECT  164.415 2.143 164.505 2.413 ;
     RECT  167.115 2.143 167.205 2.413 ;
     RECT  169.815 2.143 169.905 2.413 ;
     RECT  172.515 2.143 172.605 2.413 ;
     RECT  175.215 2.143 175.305 2.413 ;
     RECT  177.915 2.143 178.005 2.413 ;
     RECT  180.615 2.143 180.705 2.413 ;
     RECT  183.315 2.143 183.405 2.413 ;
     RECT  186.015 2.143 186.105 2.413 ;
     RECT  188.715 2.143 188.805 2.413 ;
     RECT  190.872 2.371 191.505 2.413 ;
     RECT  194.115 2.143 194.205 2.413 ;
     RECT  196.815 2.143 196.905 2.413 ;
     RECT  199.515 2.143 199.605 2.413 ;
     RECT  202.215 2.143 202.305 2.413 ;
     RECT  204.915 2.143 205.005 2.413 ;
     RECT  207.615 2.143 207.705 2.413 ;
     RECT  210.315 2.143 210.405 2.413 ;
     RECT  213.015 2.143 213.105 2.413 ;
     RECT  190.872 2.413 191.697 2.489 ;
     RECT  149.832 2.371 149.85 3.181 ;
     RECT  25.956 2.263 25.974 3.569 ;
     RECT  66.78 2.413 67.497 3.613 ;
     RECT  66.78 3.613 67.554 3.649 ;
     RECT  26.715 2.413 26.997 3.685 ;
     RECT  26.715 3.685 27.054 3.721 ;
     RECT  29.415 2.413 29.697 3.721 ;
     RECT  66.6 3.649 67.554 3.721 ;
     RECT  149.832 3.181 149.958 3.721 ;
     RECT  66.6 3.721 67.914 3.725 ;
     RECT  25.812 3.721 25.83 3.773 ;
     RECT  26.676 3.721 27.198 3.875 ;
     RECT  27.972 3.721 29.697 3.875 ;
     RECT  149.508 3.721 150.138 3.947 ;
     RECT  150.915 2.413 151.197 3.955 ;
     RECT  149.58 3.947 149.598 4.019 ;
     RECT  191.196 2.489 191.697 4.081 ;
     RECT  26.715 3.875 27.198 4.109 ;
     RECT  150.408 3.955 151.197 4.109 ;
     RECT  145.515 2.413 145.797 4.117 ;
     RECT  191.052 4.081 191.697 4.117 ;
     RECT  26.715 4.109 27.09 4.145 ;
     RECT  28.26 3.875 29.697 4.145 ;
     RECT  191.052 4.117 191.79 4.157 ;
     RECT  150.84 4.109 151.197 4.181 ;
     RECT  191.415 4.157 191.79 4.261 ;
     RECT  145.515 4.117 146.502 4.289 ;
     RECT  28.98 4.145 29.697 4.415 ;
     RECT  191.415 4.261 192.33 4.721 ;
     RECT  152.208 3.721 152.226 4.919 ;
     RECT  29.304 4.415 29.697 5.063 ;
     RECT  29.415 5.063 29.697 5.071 ;
     RECT  30.744 4.351 30.762 5.071 ;
     RECT  28.548 5.035 28.566 5.117 ;
     RECT  191.415 4.721 191.934 5.117 ;
     RECT  29.415 5.071 30.762 5.459 ;
     RECT  2.415 2.413 2.697 5.575 ;
     RECT  213.015 2.413 213.297 5.575 ;
     RECT  30.672 5.459 30.762 5.603 ;
     RECT  0.216 5.611 0.234 5.648 ;
     RECT  29.415 5.459 29.862 5.693 ;
     RECT  213.015 5.575 213.642 5.701 ;
     RECT  2.304 5.575 2.697 5.729 ;
     RECT  2.34 5.729 2.697 5.737 ;
     RECT  214.884 5.611 214.902 5.741 ;
     RECT  4.068 5.737 4.086 5.773 ;
     RECT  2.34 5.737 3.294 5.881 ;
     RECT  4.068 5.773 4.23 5.881 ;
     RECT  5.115 2.413 5.397 5.881 ;
     RECT  2.34 5.881 5.397 5.933 ;
     RECT  4.068 5.933 5.397 5.971 ;
     RECT  118.515 2.413 118.797 5.971 ;
     RECT  4.068 5.971 5.814 6.035 ;
     RECT  212.76 5.701 213.642 6.079 ;
     RECT  2.34 5.933 3.294 6.107 ;
     RECT  4.536 6.035 5.814 6.107 ;
     RECT  212.04 6.079 213.642 6.115 ;
     RECT  211.428 6.115 213.642 6.173 ;
     RECT  2.415 6.107 3.294 6.269 ;
     RECT  212.148 6.173 213.642 6.269 ;
     RECT  212.148 6.269 213.534 6.305 ;
     RECT  2.415 6.269 2.97 6.539 ;
     RECT  2.415 6.539 2.862 6.575 ;
     RECT  212.148 6.305 213.297 6.575 ;
     RECT  2.415 6.575 2.697 8.005 ;
     RECT  2.34 8.005 2.697 8.041 ;
     RECT  5.115 6.107 5.814 8.131 ;
     RECT  2.268 8.041 2.697 8.141 ;
     RECT  2.34 8.141 2.697 8.159 ;
     RECT  7.815 2.413 8.097 8.239 ;
     RECT  5.115 8.131 6.246 8.267 ;
     RECT  2.415 8.159 2.697 8.311 ;
     RECT  3.6 8.131 3.618 8.311 ;
     RECT  5.115 8.267 6.138 8.311 ;
     RECT  4.86 8.311 6.138 8.381 ;
     RECT  2.415 8.311 3.618 8.429 ;
     RECT  5.004 8.381 6.138 8.429 ;
     RECT  2.415 8.429 3.33 8.465 ;
     RECT  140.115 2.413 140.397 8.473 ;
     RECT  210.315 2.413 210.597 8.473 ;
     RECT  214.344 8.437 214.362 8.477 ;
     RECT  210.315 8.473 210.69 8.491 ;
     RECT  6.12 8.429 6.138 8.501 ;
     RECT  206.352 8.401 206.37 8.501 ;
     RECT  209.7 8.491 210.69 8.525 ;
     RECT  2.415 8.465 3.078 8.537 ;
     RECT  209.7 8.525 210.597 8.537 ;
     RECT  213.015 6.575 213.297 8.545 ;
     RECT  212.148 6.575 212.166 8.581 ;
     RECT  213.015 8.545 213.534 8.581 ;
     RECT  212.904 8.581 213.534 8.699 ;
     RECT  211.32 8.581 212.166 8.735 ;
     RECT  212.904 8.699 213.39 8.735 ;
     RECT  140.115 8.473 141.066 10.049 ;
     RECT  2.415 8.537 2.697 10.435 ;
     RECT  0.216 10.471 0.234 10.685 ;
     RECT  7.815 8.239 8.154 10.831 ;
     RECT  212.148 8.735 212.166 11.011 ;
     RECT  207.615 2.413 207.897 11.083 ;
     RECT  211.536 11.011 212.166 11.101 ;
     RECT  213.015 8.735 213.297 11.101 ;
     RECT  211.536 11.101 213.297 11.129 ;
     RECT  7.815 10.831 8.262 11.137 ;
     RECT  2.304 10.435 2.697 11.165 ;
     RECT  211.644 11.129 213.297 11.165 ;
     RECT  208.908 11.137 208.926 11.173 ;
     RECT  3.708 11.011 3.726 11.209 ;
     RECT  7.815 11.137 8.298 11.209 ;
     RECT  208.908 11.173 209.07 11.213 ;
     RECT  214.344 11.101 214.362 11.213 ;
     RECT  3.708 11.209 3.762 11.281 ;
     RECT  7.308 11.209 8.298 11.281 ;
     RECT  207.615 11.083 208.134 11.281 ;
     RECT  208.908 11.213 208.926 11.281 ;
     RECT  3.636 11.281 3.762 11.399 ;
     RECT  6.264 11.281 6.282 11.399 ;
     RECT  7.308 11.281 8.622 11.407 ;
     RECT  207.615 11.281 208.926 11.435 ;
     RECT  6.768 11.407 8.622 11.507 ;
     RECT  212.148 11.165 213.297 11.705 ;
     RECT  10.515 2.413 10.797 11.821 ;
     RECT  7.488 11.507 8.406 11.981 ;
     RECT  7.632 11.981 8.406 12.209 ;
     RECT  7.815 12.209 8.406 12.325 ;
     RECT  2.415 11.165 2.697 13.135 ;
     RECT  2.415 13.135 2.79 13.147 ;
     RECT  2.268 13.147 2.79 13.199 ;
     RECT  3.816 13.261 3.834 13.361 ;
     RECT  2.415 13.199 2.79 13.441 ;
     RECT  5.004 8.429 5.397 13.441 ;
     RECT  7.815 12.325 9.054 13.441 ;
     RECT  7.524 13.441 9.054 13.531 ;
     RECT  5.004 13.441 5.778 13.559 ;
     RECT  7.524 13.531 9.126 13.559 ;
     RECT  2.415 13.441 3.222 13.631 ;
     RECT  213.015 11.705 213.297 13.801 ;
     RECT  7.815 13.559 9.126 13.945 ;
     RECT  214.344 13.963 214.362 14.009 ;
     RECT  212.148 11.705 212.166 14.071 ;
     RECT  213.015 13.801 213.534 14.071 ;
     RECT  212.148 14.071 213.534 14.099 ;
     RECT  205.992 14.377 206.73 14.395 ;
     RECT  207.615 11.435 208.278 14.395 ;
     RECT  212.148 14.099 213.297 14.405 ;
     RECT  205.992 14.395 208.278 14.429 ;
     RECT  206.136 14.429 208.278 14.441 ;
     RECT  206.136 14.441 206.73 14.675 ;
     RECT  2.415 13.631 2.697 15.565 ;
     RECT  2.304 15.565 2.697 15.719 ;
     RECT  0.216 15.601 0.234 15.725 ;
     RECT  2.415 15.719 2.697 15.835 ;
     RECT  2.415 15.835 2.754 15.871 ;
     RECT  5.004 13.559 5.397 15.961 ;
     RECT  4.932 15.961 5.598 15.997 ;
     RECT  6.372 15.979 6.39 15.997 ;
     RECT  7.815 13.945 9.414 15.997 ;
     RECT  10.476 11.821 10.797 15.997 ;
     RECT  4.716 15.997 6.39 16.025 ;
     RECT  4.716 16.025 5.958 16.033 ;
     RECT  3.744 16.069 3.762 16.109 ;
     RECT  6.768 16.033 6.786 16.141 ;
     RECT  7.815 15.997 10.797 16.169 ;
     RECT  3.924 16.141 3.942 16.259 ;
     RECT  9.036 16.169 10.797 16.259 ;
     RECT  10.44 16.259 10.797 16.267 ;
     RECT  4.68 16.033 5.958 16.295 ;
     RECT  6.768 16.141 6.93 16.295 ;
     RECT  6.84 16.295 6.93 16.367 ;
     RECT  13.215 2.413 13.497 16.375 ;
     RECT  9.036 16.259 9.342 16.439 ;
     RECT  10.44 16.267 11.142 16.529 ;
     RECT  2.415 15.871 3.006 16.601 ;
     RECT  212.148 14.405 212.166 16.681 ;
     RECT  213.015 14.405 213.297 16.681 ;
     RECT  211.5 16.681 213.297 16.795 ;
     RECT  211.32 16.795 213.297 16.799 ;
     RECT  69.915 2.413 70.197 16.807 ;
     RECT  207.615 14.441 208.278 16.807 ;
     RECT  5.004 16.295 5.706 16.835 ;
     RECT  191.415 5.117 191.79 16.835 ;
     RECT  211.32 16.799 211.338 16.871 ;
     RECT  214.344 16.699 214.362 16.871 ;
     RECT  18.615 2.413 18.897 16.951 ;
     RECT  6.912 16.367 6.93 16.979 ;
     RECT  18.324 16.951 18.897 17.069 ;
     RECT  212.076 16.799 213.297 17.213 ;
     RECT  32.115 2.413 32.397 17.311 ;
     RECT  33.552 16.501 33.57 17.311 ;
     RECT  10.476 16.529 11.142 17.339 ;
     RECT  15.048 17.221 15.066 17.339 ;
     RECT  192.564 17.041 192.582 17.339 ;
     RECT  14.724 17.347 14.994 17.419 ;
     RECT  9.036 16.439 9.054 17.483 ;
     RECT  14.544 17.419 14.994 17.519 ;
     RECT  10.515 17.339 11.142 17.609 ;
     RECT  20.016 17.491 20.034 17.609 ;
     RECT  12.744 16.375 13.497 17.617 ;
     RECT  14.544 17.519 14.922 17.681 ;
     RECT  5.115 16.835 5.706 17.923 ;
     RECT  5.115 17.923 6.39 17.959 ;
     RECT  7.815 16.169 8.154 17.959 ;
     RECT  32.115 17.311 33.57 17.959 ;
     RECT  2.415 16.601 2.697 17.995 ;
     RECT  5.115 17.959 6.858 18.031 ;
     RECT  7.815 17.959 8.874 18.031 ;
     RECT  19.908 17.725 19.926 18.059 ;
     RECT  5.115 18.031 8.874 18.139 ;
     RECT  2.304 17.995 2.697 18.149 ;
     RECT  5.112 18.139 8.874 18.149 ;
     RECT  5.112 18.149 6.066 18.185 ;
     RECT  7.38 18.149 8.19 18.185 ;
     RECT  5.112 18.185 5.706 18.193 ;
     RECT  0.216 18.031 0.234 18.221 ;
     RECT  5.04 18.193 5.706 18.221 ;
     RECT  7.632 18.185 8.19 18.221 ;
     RECT  32.115 17.959 34.002 18.229 ;
     RECT  34.815 2.413 35.097 18.229 ;
     RECT  12.024 17.617 13.497 18.293 ;
     RECT  2.415 18.149 2.697 18.301 ;
     RECT  3.42 18.121 3.438 18.301 ;
     RECT  14.616 17.681 14.922 18.301 ;
     RECT  5.04 18.221 5.67 18.419 ;
     RECT  31.104 5.611 31.122 18.427 ;
     RECT  2.415 18.301 3.546 18.455 ;
     RECT  18.432 17.069 18.897 18.455 ;
     RECT  32.115 18.229 35.097 18.455 ;
     RECT  2.415 18.455 3.438 18.491 ;
     RECT  5.115 18.419 5.67 18.491 ;
     RECT  3.42 18.491 3.438 18.527 ;
     RECT  30.78 18.427 31.122 18.527 ;
     RECT  14.616 18.301 15.066 18.535 ;
     RECT  14.4 18.535 15.066 18.571 ;
     RECT  14.4 18.571 15.138 18.959 ;
     RECT  14.616 18.959 15.138 19.031 ;
     RECT  210.315 8.537 210.597 19.381 ;
     RECT  212.148 17.213 213.297 19.381 ;
     RECT  214.236 19.435 214.254 19.571 ;
     RECT  209.88 19.381 210.597 19.615 ;
     RECT  209.7 19.615 210.654 19.651 ;
     RECT  211.896 19.381 213.297 19.651 ;
     RECT  209.7 19.651 211.014 19.661 ;
     RECT  24.015 2.413 24.297 19.741 ;
     RECT  210.276 19.661 211.014 19.769 ;
     RECT  211.752 19.651 213.297 19.805 ;
     RECT  210.315 19.769 211.014 19.841 ;
     RECT  207.504 16.807 208.278 19.913 ;
     RECT  2.415 18.491 2.697 20.551 ;
     RECT  129.315 2.413 129.597 20.695 ;
     RECT  12.456 18.293 13.497 20.723 ;
     RECT  129.024 20.695 129.597 20.731 ;
     RECT  0.216 20.683 0.234 20.759 ;
     RECT  14.616 19.031 14.706 20.759 ;
     RECT  7.815 18.221 8.19 20.779 ;
     RECT  2.304 20.551 2.697 20.821 ;
     RECT  129.024 20.731 130.266 20.821 ;
     RECT  159.015 2.413 159.297 20.821 ;
     RECT  2.304 20.821 3.366 20.849 ;
     RECT  7.236 20.779 8.19 20.849 ;
     RECT  129.024 20.821 130.59 20.849 ;
     RECT  5.115 18.491 5.397 20.929 ;
     RECT  130.536 20.849 130.59 20.957 ;
     RECT  5.115 20.929 5.706 21.001 ;
     RECT  7.596 20.849 8.19 21.001 ;
     RECT  130.572 20.957 130.59 21.029 ;
     RECT  2.376 20.849 3.366 21.119 ;
     RECT  4.788 21.001 6.282 21.119 ;
     RECT  10.515 17.609 10.89 21.155 ;
     RECT  7.596 21.001 8.226 21.199 ;
     RECT  129.024 20.849 129.597 21.199 ;
     RECT  12.816 20.723 13.497 21.227 ;
     RECT  2.415 21.119 3.366 21.263 ;
     RECT  5.115 21.119 6.282 21.263 ;
     RECT  6.264 21.263 6.282 21.299 ;
     RECT  122.544 21.127 122.562 21.299 ;
     RECT  128.628 21.199 129.597 21.299 ;
     RECT  7.596 21.199 8.55 21.541 ;
     RECT  7.596 21.541 9.234 21.629 ;
     RECT  10.515 21.155 10.797 21.631 ;
     RECT  7.74 21.629 9.234 21.659 ;
     RECT  158.472 20.821 159.297 21.731 ;
     RECT  209.052 19.741 209.07 21.811 ;
     RECT  212.148 19.805 213.297 21.901 ;
     RECT  206.136 14.675 206.658 21.973 ;
     RECT  207.615 19.913 208.278 21.973 ;
     RECT  158.796 21.731 159.297 22.037 ;
     RECT  206.136 21.973 208.278 22.081 ;
     RECT  209.052 21.811 209.394 22.081 ;
     RECT  7.815 21.659 9.234 22.199 ;
     RECT  206.136 22.081 209.394 22.199 ;
     RECT  214.884 22.207 214.902 22.253 ;
     RECT  118.515 5.971 118.89 22.469 ;
     RECT  206.136 22.199 209.07 22.469 ;
     RECT  15.915 2.413 16.197 22.513 ;
     RECT  126.615 2.413 126.897 22.513 ;
     RECT  206.136 22.469 208.278 22.541 ;
     RECT  14.688 20.759 14.706 22.549 ;
     RECT  23.364 19.741 24.297 22.577 ;
     RECT  158.904 22.037 159.297 22.577 ;
     RECT  69.915 16.807 70.254 22.621 ;
     RECT  210.315 19.841 210.597 22.621 ;
     RECT  211.86 21.901 213.297 22.739 ;
     RECT  69.84 22.621 70.254 22.781 ;
     RECT  2.415 21.263 2.697 22.981 ;
     RECT  2.415 22.981 2.826 23.153 ;
     RECT  2.415 23.153 2.754 23.161 ;
     RECT  0.216 23.227 0.234 23.279 ;
     RECT  3.78 23.161 3.798 23.279 ;
     RECT  7.815 22.199 8.55 23.359 ;
     RECT  9.288 22.351 9.306 23.359 ;
     RECT  7.815 23.359 9.306 23.431 ;
     RECT  2.376 23.161 2.754 23.549 ;
     RECT  3.888 23.395 3.906 23.549 ;
     RECT  6.84 23.557 6.858 23.657 ;
     RECT  2.376 23.549 2.697 23.855 ;
     RECT  7.815 23.431 9.378 24.241 ;
     RECT  10.152 21.631 10.797 24.241 ;
     RECT  209.052 22.469 209.07 24.709 ;
     RECT  209.052 24.709 209.178 24.737 ;
     RECT  212.148 22.739 213.297 24.781 ;
     RECT  209.16 24.737 209.178 24.809 ;
     RECT  126.615 22.513 126.954 24.899 ;
     RECT  61.815 2.413 62.097 24.907 ;
     RECT  212.04 24.781 213.297 24.955 ;
     RECT  212.04 24.955 213.786 25.043 ;
     RECT  209.556 24.907 209.574 25.141 ;
     RECT  210.315 22.621 211.014 25.141 ;
     RECT  206.136 22.541 207.897 25.169 ;
     RECT  209.556 25.141 211.014 25.205 ;
     RECT  206.136 25.169 206.694 25.229 ;
     RECT  209.664 25.205 211.014 25.229 ;
     RECT  2.415 23.855 2.697 25.681 ;
     RECT  2.412 25.681 2.697 25.853 ;
     RECT  2.415 25.853 2.697 25.861 ;
     RECT  0.54 25.771 0.558 25.889 ;
     RECT  2.415 25.861 2.97 26.095 ;
     RECT  2.415 26.095 3.006 26.131 ;
     RECT  2.415 26.131 3.51 26.251 ;
     RECT  5.115 21.263 5.397 26.257 ;
     RECT  4.644 26.257 5.397 26.293 ;
     RECT  2.415 26.251 3.726 26.401 ;
     RECT  4.608 26.293 5.397 26.491 ;
     RECT  2.415 26.401 3.87 26.519 ;
     RECT  3.708 26.519 3.87 26.669 ;
     RECT  4.608 26.491 5.814 26.789 ;
     RECT  3.852 26.669 3.87 26.797 ;
     RECT  118.515 22.469 118.797 26.797 ;
     RECT  3.852 26.797 4.302 26.825 ;
     RECT  210.315 25.229 211.014 27.481 ;
     RECT  212.04 25.043 213.297 27.481 ;
     RECT  214.344 27.691 214.362 27.743 ;
     RECT  2.415 26.519 2.697 28.111 ;
     RECT  2.304 28.111 2.697 28.283 ;
     RECT  2.415 28.283 2.697 28.291 ;
     RECT  0.216 28.267 0.234 28.319 ;
     RECT  210.315 27.481 213.297 28.445 ;
     RECT  2.415 28.291 2.862 28.651 ;
     RECT  15.915 22.513 16.722 28.759 ;
     RECT  33.12 18.455 35.097 28.787 ;
     RECT  105.015 2.413 105.297 28.795 ;
     RECT  33.732 28.787 35.097 28.823 ;
     RECT  2.415 28.651 3.114 28.831 ;
     RECT  4.284 26.825 4.302 28.831 ;
     RECT  5.115 26.789 5.814 28.831 ;
     RECT  7.815 24.241 10.797 28.921 ;
     RECT  210.315 28.445 211.122 28.921 ;
     RECT  2.415 28.831 3.186 28.949 ;
     RECT  209.88 28.921 211.122 28.973 ;
     RECT  2.415 28.949 3.114 28.985 ;
     RECT  4.284 28.831 6.138 28.993 ;
     RECT  4.284 28.993 6.822 29.021 ;
     RECT  64.515 2.413 64.797 29.029 ;
     RECT  5.115 29.021 6.822 29.057 ;
     RECT  67.215 3.725 67.914 29.057 ;
     RECT  206.136 25.229 206.658 29.065 ;
     RECT  209.268 29.179 209.286 29.219 ;
     RECT  210.168 28.973 211.122 29.261 ;
     RECT  208.944 29.227 208.962 29.264 ;
     RECT  5.115 29.057 5.742 29.327 ;
     RECT  6.804 29.057 6.822 29.371 ;
     RECT  7.668 28.921 10.797 29.371 ;
     RECT  186.015 2.413 186.297 29.371 ;
     RECT  206.028 29.065 206.658 29.371 ;
     RECT  207.615 25.169 207.897 29.371 ;
     RECT  6.804 29.371 10.797 29.399 ;
     RECT  75.315 2.413 75.597 29.461 ;
     RECT  204.915 2.413 205.197 29.467 ;
     RECT  206.028 29.371 207.897 29.467 ;
     RECT  204.915 29.467 207.897 29.489 ;
     RECT  78.015 2.413 78.297 29.497 ;
     RECT  104.688 28.795 105.297 29.497 ;
     RECT  6.948 29.399 10.797 29.525 ;
     RECT  192.636 17.491 192.654 29.525 ;
     RECT  204.915 29.489 206.658 29.525 ;
     RECT  56.415 2.413 56.697 29.533 ;
     RECT  74.664 29.461 75.597 29.561 ;
     RECT  206.028 29.525 206.514 29.561 ;
     RECT  118.515 26.797 118.854 29.569 ;
     RECT  77.4 29.497 78.297 29.597 ;
     RECT  106.956 21.901 106.974 29.597 ;
     RECT  104.58 29.497 105.297 29.633 ;
     RECT  107.715 2.413 107.997 29.641 ;
     RECT  107.1 29.641 107.997 29.795 ;
     RECT  185.4 29.371 186.297 30.029 ;
     RECT  118.515 29.569 119.142 30.101 ;
     RECT  102.315 2.413 102.597 30.109 ;
     RECT  7.308 29.525 10.797 30.181 ;
     RECT  185.58 30.029 186.297 30.209 ;
     RECT  7.308 30.181 11.034 30.221 ;
     RECT  210.315 29.261 211.014 30.451 ;
     RECT  2.415 28.985 2.697 30.541 ;
     RECT  31.104 18.527 31.122 30.569 ;
     RECT  206.028 29.561 206.046 30.569 ;
     RECT  209.88 30.451 211.014 30.569 ;
     RECT  121.215 2.413 121.497 30.649 ;
     RECT  199.515 2.413 199.797 30.649 ;
     RECT  209.88 30.569 210.69 30.649 ;
     RECT  209.7 30.649 210.69 30.701 ;
     RECT  214.344 30.427 214.362 30.713 ;
     RECT  2.304 30.541 2.697 30.721 ;
     RECT  29.415 5.693 29.697 30.721 ;
     RECT  212.04 28.445 213.297 30.749 ;
     RECT  1.728 30.721 2.862 30.893 ;
     RECT  5.115 29.327 5.454 30.991 ;
     RECT  101.7 30.109 102.597 30.991 ;
     RECT  104.688 29.633 105.297 31.019 ;
     RECT  104.76 31.019 105.297 31.081 ;
     RECT  2.415 30.893 2.862 31.109 ;
     RECT  5.076 30.991 5.454 31.109 ;
     RECT  104.76 31.081 105.462 31.109 ;
     RECT  120.816 30.649 121.497 31.109 ;
     RECT  2.415 31.109 2.79 31.145 ;
     RECT  107.172 29.795 107.997 31.145 ;
     RECT  6.804 30.991 6.822 31.181 ;
     RECT  101.592 30.991 102.597 31.217 ;
     RECT  96.915 2.413 97.197 31.261 ;
     RECT  69.915 22.781 70.254 31.339 ;
     RECT  105.015 31.109 105.462 31.379 ;
     RECT  69.732 31.339 70.254 31.387 ;
     RECT  96.915 31.261 97.434 31.387 ;
     RECT  69.732 31.387 70.722 31.423 ;
     RECT  96.228 31.387 97.434 31.423 ;
     RECT  7.74 30.221 11.034 31.523 ;
     RECT  69.408 31.423 70.83 31.523 ;
     RECT  6.84 31.495 6.966 31.621 ;
     RECT  7.74 31.523 10.797 31.621 ;
     RECT  71.568 31.531 71.586 31.621 ;
     RECT  72.615 2.413 72.897 31.621 ;
     RECT  69.408 31.523 70.758 31.649 ;
     RECT  118.515 30.101 118.854 31.657 ;
     RECT  207.615 29.489 207.897 31.657 ;
     RECT  6.84 31.621 10.797 31.661 ;
     RECT  69.408 31.649 70.722 31.685 ;
     RECT  29.415 30.721 30.114 31.693 ;
     RECT  31.032 31.387 31.05 31.693 ;
     RECT  67.215 29.057 67.626 31.693 ;
     RECT  33.768 28.823 35.097 31.721 ;
     RECT  69.552 31.685 70.722 31.721 ;
     RECT  29.415 31.693 31.05 31.793 ;
     RECT  118.515 31.657 118.962 31.793 ;
     RECT  66.708 31.693 67.626 31.829 ;
     RECT  96.12 31.423 97.434 31.829 ;
     RECT  114.588 31.693 114.606 31.829 ;
     RECT  21.315 2.413 21.597 31.891 ;
     RECT  75.315 29.561 75.597 31.891 ;
     RECT  6.84 31.661 6.966 31.919 ;
     RECT  71.568 31.621 72.897 31.919 ;
     RECT  61.815 24.907 62.406 31.927 ;
     RECT  94.215 2.413 94.497 31.927 ;
     RECT  96.12 31.829 97.197 31.927 ;
     RECT  56.415 29.533 57.294 31.955 ;
     RECT  24.015 22.577 24.297 31.999 ;
     RECT  96.048 31.927 97.197 31.999 ;
     RECT  69.624 31.721 70.722 32.027 ;
     RECT  71.748 31.919 71.766 32.027 ;
     RECT  96.012 31.999 97.197 32.027 ;
     RECT  140.115 10.049 140.994 32.027 ;
     RECT  21.315 31.891 21.69 32.035 ;
     RECT  25.668 31.999 25.686 32.035 ;
     RECT  26.715 4.145 26.997 32.035 ;
     RECT  94.215 31.927 94.662 32.063 ;
     RECT  21.315 32.035 22.014 32.071 ;
     RECT  23.94 31.999 24.297 32.071 ;
     RECT  96.012 32.027 96.102 32.099 ;
     RECT  98.604 31.999 98.622 32.189 ;
     RECT  21.276 32.071 22.554 32.197 ;
     RECT  34.38 31.721 35.097 32.225 ;
     RECT  23.832 32.071 24.57 32.233 ;
     RECT  7.812 31.661 10.797 32.237 ;
     RECT  21.276 32.197 22.986 32.341 ;
     RECT  23.832 32.233 24.606 32.341 ;
     RECT  25.668 32.035 26.997 32.341 ;
     RECT  5.115 31.109 5.454 32.347 ;
     RECT  5.115 32.347 5.778 32.459 ;
     RECT  207.54 31.657 207.897 32.459 ;
     RECT  61.815 31.927 62.982 32.467 ;
     RECT  6.84 31.919 6.894 32.477 ;
     RECT  21.276 32.341 26.997 32.495 ;
     RECT  61.74 32.467 62.982 32.495 ;
     RECT  26.676 32.495 26.997 32.539 ;
     RECT  28.656 32.299 28.674 32.539 ;
     RECT  29.415 31.793 30.114 32.539 ;
     RECT  21.276 32.495 25.83 32.611 ;
     RECT  28.656 32.539 30.114 32.611 ;
     RECT  21.096 32.611 25.83 32.737 ;
     RECT  26.676 32.539 27.234 32.737 ;
     RECT  189.9 32.701 189.918 32.765 ;
     RECT  19.98 32.737 19.998 32.773 ;
     RECT  20.772 32.737 25.83 32.773 ;
     RECT  32.115 18.455 32.397 32.773 ;
     RECT  96.048 32.099 96.102 32.801 ;
     RECT  18.615 18.455 18.897 32.881 ;
     RECT  26.676 32.737 27.414 32.881 ;
     RECT  28.332 32.611 30.114 32.881 ;
     RECT  191.415 16.835 191.697 32.881 ;
     RECT  191.268 32.881 191.697 32.957 ;
     RECT  2.415 31.145 2.697 32.971 ;
     RECT  2.415 32.971 2.862 33.071 ;
     RECT  18.432 32.881 18.897 33.079 ;
     RECT  19.98 32.773 25.83 33.079 ;
     RECT  207.615 32.459 207.897 33.079 ;
     RECT  212.256 30.749 213.297 33.079 ;
     RECT  18.432 33.079 19.026 33.115 ;
     RECT  31.032 31.793 31.05 33.115 ;
     RECT  2.415 33.071 2.697 33.151 ;
     RECT  14.58 22.549 14.706 33.151 ;
     RECT  207.615 33.079 208.278 33.151 ;
     RECT  209.052 32.467 209.07 33.151 ;
     RECT  210.315 30.701 210.69 33.179 ;
     RECT  69.624 32.027 70.197 33.241 ;
     RECT  207.615 33.151 209.07 33.269 ;
     RECT  212.22 33.079 213.297 33.269 ;
     RECT  61.74 32.495 62.097 33.277 ;
     RECT  6.804 33.043 6.822 33.305 ;
     RECT  19.944 33.079 25.83 33.313 ;
     RECT  26.676 32.881 30.114 33.313 ;
     RECT  30.852 33.115 31.05 33.313 ;
     RECT  31.788 32.773 32.397 33.313 ;
     RECT  14.58 33.151 14.85 33.341 ;
     RECT  69.552 33.241 70.197 33.341 ;
     RECT  214.236 33.211 214.254 33.341 ;
     RECT  18.288 33.115 19.206 33.349 ;
     RECT  19.944 33.313 30.114 33.349 ;
     RECT  69.624 33.341 70.197 33.377 ;
     RECT  61.74 33.277 62.154 33.385 ;
     RECT  62.964 32.495 62.982 33.385 ;
     RECT  207.615 33.269 208.098 33.389 ;
     RECT  77.004 29.641 77.022 33.413 ;
     RECT  0.216 33.307 0.234 33.449 ;
     RECT  18.288 33.349 30.114 33.511 ;
     RECT  30.852 33.313 32.397 33.511 ;
     RECT  2.376 33.151 2.697 33.575 ;
     RECT  208.908 33.269 209.07 33.575 ;
     RECT  7.815 32.237 10.797 33.619 ;
     RECT  18.288 33.511 32.397 33.619 ;
     RECT  15.66 28.759 16.722 33.643 ;
     RECT  15.66 33.643 17.19 33.655 ;
     RECT  15.66 33.655 17.262 33.691 ;
     RECT  18.144 33.619 32.397 33.691 ;
     RECT  67.215 31.829 67.626 33.781 ;
     RECT  188.715 2.413 188.997 33.781 ;
     RECT  177.915 2.413 178.197 33.787 ;
     RECT  186.015 30.209 186.297 33.787 ;
     RECT  196.815 2.413 197.097 33.787 ;
     RECT  205.92 33.739 205.938 33.809 ;
     RECT  12.456 33.655 12.474 33.817 ;
     RECT  13.215 21.227 13.497 33.817 ;
     RECT  66.672 33.781 67.626 33.817 ;
     RECT  65.988 33.817 67.626 33.821 ;
     RECT  188.715 33.781 189.09 33.821 ;
     RECT  107.715 31.145 107.997 33.835 ;
     RECT  15.66 33.691 33.066 33.845 ;
     RECT  15.66 33.845 24.678 33.881 ;
     RECT  204.915 29.525 205.197 33.883 ;
     RECT  174.42 33.787 174.438 33.917 ;
     RECT  177.915 33.787 178.29 33.917 ;
     RECT  182.412 33.787 182.43 33.917 ;
     RECT  186.015 33.787 186.39 33.917 ;
     RECT  190.404 33.787 190.422 33.917 ;
     RECT  196.815 33.787 197.19 33.917 ;
     RECT  198.36 33.787 198.378 33.917 ;
     RECT  7.815 33.619 11.07 33.925 ;
     RECT  65.988 33.821 66.006 33.961 ;
     RECT  204.696 33.883 205.197 33.989 ;
     RECT  75.315 31.891 75.87 34.051 ;
     RECT  12.456 33.817 13.497 34.079 ;
     RECT  65.916 33.961 66.006 34.079 ;
     RECT  4.284 29.021 4.302 34.087 ;
     RECT  5.115 32.459 5.454 34.087 ;
     RECT  25.416 33.845 33.066 34.151 ;
     RECT  61.74 33.385 62.982 34.151 ;
     RECT  65.808 34.087 65.826 34.157 ;
     RECT  107.28 33.835 107.997 34.195 ;
     RECT  4.284 34.087 5.454 34.219 ;
     RECT  87.696 34.159 87.858 34.231 ;
     RECT  113.115 2.413 113.397 34.231 ;
     RECT  56.415 31.955 56.898 34.321 ;
     RECT  82.656 34.231 82.674 34.349 ;
     RECT  101.628 31.217 102.597 34.357 ;
     RECT  4.284 34.219 5.634 34.363 ;
     RECT  39.276 28.759 39.294 34.385 ;
     RECT  34.815 32.225 35.097 34.393 ;
     RECT  56.415 34.321 57.222 34.421 ;
     RECT  101.628 34.357 102.618 34.429 ;
     RECT  101.628 34.429 102.726 34.465 ;
     RECT  87.228 34.231 87.858 34.493 ;
     RECT  7.815 33.925 11.286 34.501 ;
     RECT  14.58 33.341 14.706 34.501 ;
     RECT  101.484 34.465 102.978 34.501 ;
     RECT  196.815 33.917 197.097 34.501 ;
     RECT  107.172 34.195 107.997 34.529 ;
     RECT  199.515 30.649 200.358 34.591 ;
     RECT  100.908 34.501 103.446 34.619 ;
     RECT  113.115 34.231 113.454 34.619 ;
     RECT  184.716 30.073 184.734 34.619 ;
     RECT  7.815 34.501 11.322 34.627 ;
     RECT  167.115 2.413 167.397 34.627 ;
     RECT  4.248 34.363 5.634 34.637 ;
     RECT  14.58 34.501 14.85 34.655 ;
     RECT  196.38 34.501 197.097 34.655 ;
     RECT  15.66 33.881 24.606 34.699 ;
     RECT  25.416 34.151 32.397 34.699 ;
     RECT  100.908 34.619 102.978 34.699 ;
     RECT  100.728 34.699 102.978 34.736 ;
     RECT  100.872 34.736 102.978 34.763 ;
     RECT  118.515 31.793 118.854 34.763 ;
     RECT  14.58 34.655 14.814 34.771 ;
     RECT  75.315 34.051 75.906 34.771 ;
     RECT  6.552 34.771 6.678 34.861 ;
     RECT  5.112 34.637 5.634 34.897 ;
     RECT  6.552 34.861 6.822 34.897 ;
     RECT  7.815 34.627 11.394 34.897 ;
     RECT  12.492 34.079 13.497 34.897 ;
     RECT  5.112 34.897 6.822 34.933 ;
     RECT  5.112 34.933 6.93 34.969 ;
     RECT  7.815 34.897 13.497 34.969 ;
     RECT  5.112 34.969 13.497 34.987 ;
     RECT  14.4 34.771 14.814 34.987 ;
     RECT  4.248 34.637 4.302 35.005 ;
     RECT  3.708 35.005 4.302 35.041 ;
     RECT  53.715 2.413 53.997 35.131 ;
     RECT  100.872 34.763 102.597 35.159 ;
     RECT  5.112 34.987 14.814 35.231 ;
     RECT  98.604 35.131 98.622 35.231 ;
     RECT  5.112 35.231 6.966 35.339 ;
     RECT  15.66 34.699 32.397 35.339 ;
     RECT  3.6 35.041 4.302 35.401 ;
     RECT  5.112 35.339 6.678 35.401 ;
     RECT  12.996 35.231 14.814 35.437 ;
     RECT  15.66 35.339 28.278 35.437 ;
     RECT  29.052 35.339 32.397 35.437 ;
     RECT  34.452 34.393 35.097 35.437 ;
     RECT  7.815 35.231 12.222 35.465 ;
     RECT  67.215 33.821 67.626 35.509 ;
     RECT  72.615 31.919 72.897 35.509 ;
     RECT  33.768 35.437 35.097 35.545 ;
     RECT  69.915 33.377 70.197 35.581 ;
     RECT  3.6 35.401 6.678 35.699 ;
     RECT  6.66 35.699 6.678 35.771 ;
     RECT  29.052 35.437 32.49 35.815 ;
     RECT  33.3 35.545 35.097 35.815 ;
     RECT  66.708 35.509 67.626 35.815 ;
     RECT  68.58 35.581 70.197 35.815 ;
     RECT  2.415 33.575 2.697 35.851 ;
     RECT  72.54 35.509 72.897 35.851 ;
     RECT  29.052 35.815 35.097 35.941 ;
     RECT  35.928 35.581 35.946 35.941 ;
     RECT  72.36 35.851 72.897 35.941 ;
     RECT  75.315 34.771 75.978 35.941 ;
     RECT  66.708 35.815 70.197 35.947 ;
     RECT  2.304 35.851 2.697 35.977 ;
     RECT  3.6 35.699 5.397 35.977 ;
     RECT  66.348 35.947 70.197 35.977 ;
     RECT  72.36 35.941 72.954 35.977 ;
     RECT  207.615 33.389 207.897 35.977 ;
     RECT  206.532 35.899 206.55 36.005 ;
     RECT  66.348 35.977 70.398 36.013 ;
     RECT  71.64 35.977 72.954 36.013 ;
     RECT  2.304 35.977 5.397 36.029 ;
     RECT  209.052 33.575 209.07 36.041 ;
     RECT  214.236 35.947 214.254 36.041 ;
     RECT  12.996 35.437 28.278 36.085 ;
     RECT  29.052 35.941 35.946 36.085 ;
     RECT  71.46 36.013 72.954 36.085 ;
     RECT  73.98 36.013 73.998 36.085 ;
     RECT  74.772 35.941 75.978 36.085 ;
     RECT  207.324 35.977 207.897 36.091 ;
     RECT  210.315 33.179 210.597 36.091 ;
     RECT  64.188 29.029 64.797 36.121 ;
     RECT  66.348 36.013 70.614 36.121 ;
     RECT  71.46 36.085 75.978 36.121 ;
     RECT  105.015 31.379 105.297 36.121 ;
     RECT  206.676 36.091 207.897 36.149 ;
     RECT  63.936 36.121 64.797 36.211 ;
     RECT  172.515 2.413 172.797 36.235 ;
     RECT  184.536 34.735 184.554 36.239 ;
     RECT  3.996 36.029 5.397 36.275 ;
     RECT  172.44 36.235 172.797 36.275 ;
     RECT  207.324 36.149 207.897 36.275 ;
     RECT  209.952 36.091 210.597 36.283 ;
     RECT  209.808 36.283 210.597 36.32 ;
     RECT  2.304 36.029 3.222 36.383 ;
     RECT  7.815 35.465 12.15 36.391 ;
     RECT  12.996 36.085 35.946 36.391 ;
     RECT  63.864 36.211 64.797 36.391 ;
     RECT  172.515 36.275 172.797 36.391 ;
     RECT  2.304 36.383 3.15 36.419 ;
     RECT  172.515 36.391 172.926 36.461 ;
     RECT  191.415 32.957 191.697 36.475 ;
     RECT  3.996 36.275 4.194 36.509 ;
     RECT  104.904 36.121 105.297 36.509 ;
     RECT  7.815 36.391 35.946 36.517 ;
     RECT  62.964 34.151 62.982 36.517 ;
     RECT  63.864 36.391 65.538 36.517 ;
     RECT  62.964 36.517 65.538 36.589 ;
     RECT  60.552 36.481 60.57 36.617 ;
     RECT  52.992 35.131 53.997 36.625 ;
     RECT  2.415 36.419 3.15 36.653 ;
     RECT  4.176 36.509 4.194 36.653 ;
     RECT  59.115 2.413 59.397 36.661 ;
     RECT  61.74 34.151 62.097 36.661 ;
     RECT  62.82 36.589 65.538 36.661 ;
     RECT  66.348 36.121 75.978 36.661 ;
     RECT  188.715 33.821 188.997 36.751 ;
     RECT  122.652 35.041 122.67 36.763 ;
     RECT  145.515 4.289 145.797 36.763 ;
     RECT  153.615 2.413 153.897 36.763 ;
     RECT  161.715 2.413 161.997 36.763 ;
     RECT  169.815 2.413 170.097 36.763 ;
     RECT  177.915 33.917 178.197 36.763 ;
     RECT  188.604 36.751 188.997 36.797 ;
     RECT  58.716 36.661 59.397 36.815 ;
     RECT  61.236 36.661 62.097 36.859 ;
     RECT  62.82 36.661 75.978 36.859 ;
     RECT  191.415 36.475 191.862 36.859 ;
     RECT  122.544 36.763 122.67 36.893 ;
     RECT  130.536 36.763 130.554 36.893 ;
     RECT  138.528 36.763 138.546 36.893 ;
     RECT  145.515 36.763 146.502 36.893 ;
     RECT  153.615 36.763 154.494 36.893 ;
     RECT  161.715 36.763 162.486 36.893 ;
     RECT  169.815 36.763 170.442 36.893 ;
     RECT  177.915 36.763 178.434 36.893 ;
     RECT  190.404 36.763 190.422 36.893 ;
     RECT  7.704 36.517 35.946 36.931 ;
     RECT  115.815 2.413 116.097 36.931 ;
     RECT  191.415 36.859 192.15 36.959 ;
     RECT  7.704 36.931 36.162 37.021 ;
     RECT  52.416 36.625 53.997 37.021 ;
     RECT  115.815 36.931 116.73 37.037 ;
     RECT  7.344 37.021 36.162 37.093 ;
     RECT  7.344 37.093 36.27 37.201 ;
     RECT  104.94 36.509 105.297 37.229 ;
     RECT  61.236 36.859 75.978 37.387 ;
     RECT  40.215 2.413 40.497 37.399 ;
     RECT  45.615 2.413 45.897 37.399 ;
     RECT  48.315 2.413 48.597 37.399 ;
     RECT  60.876 37.387 75.978 37.427 ;
     RECT  40.215 37.399 41.058 37.435 ;
     RECT  7.344 37.201 36.594 37.471 ;
     RECT  40.215 37.435 41.418 37.471 ;
     RECT  42.915 2.413 43.197 37.471 ;
     RECT  44.1 37.399 44.118 37.471 ;
     RECT  48.315 37.399 48.726 37.471 ;
     RECT  59.115 36.815 59.397 37.561 ;
     RECT  6.552 37.471 36.594 37.579 ;
     RECT  40.215 37.471 41.526 37.579 ;
     RECT  58.464 37.561 59.397 37.579 ;
     RECT  6.408 37.579 36.594 37.589 ;
     RECT  39.672 37.579 41.526 37.589 ;
     RECT  42.768 37.471 43.197 37.597 ;
     RECT  44.028 37.471 44.118 37.597 ;
     RECT  45.036 37.399 45.897 37.597 ;
     RECT  46.656 37.561 46.674 37.597 ;
     RECT  47.916 37.471 48.726 37.597 ;
     RECT  6.408 37.589 6.426 37.625 ;
     RECT  39.672 37.589 41.418 37.625 ;
     RECT  39.672 37.625 41.202 37.627 ;
     RECT  58.356 37.579 59.397 37.627 ;
     RECT  45.036 37.597 48.726 37.633 ;
     RECT  7.164 37.589 36.594 37.661 ;
     RECT  42.768 37.597 44.118 37.669 ;
     RECT  42.624 37.669 44.118 37.675 ;
     RECT  44.964 37.633 48.726 37.705 ;
     RECT  52.308 37.021 53.997 37.705 ;
     RECT  18.108 37.661 36.594 37.741 ;
     RECT  88.815 2.413 89.097 37.741 ;
     RECT  100.872 35.159 100.89 37.741 ;
     RECT  101.628 35.159 102.597 37.741 ;
     RECT  55.26 37.579 55.278 37.831 ;
     RECT  5.115 36.275 5.397 37.867 ;
     RECT  52.308 37.705 54.45 37.867 ;
     RECT  55.26 37.831 55.494 37.867 ;
     RECT  121.215 31.109 121.497 37.867 ;
     RECT  58.032 37.627 59.397 37.895 ;
     RECT  44.964 37.705 49.194 37.903 ;
     RECT  38.772 37.723 38.79 38.005 ;
     RECT  39.528 37.627 41.202 38.005 ;
     RECT  42.192 37.675 44.118 38.011 ;
     RECT  44.964 37.903 49.518 38.011 ;
     RECT  51.015 2.413 51.297 38.011 ;
     RECT  51.015 38.011 51.534 38.101 ;
     RECT  100.872 37.741 102.597 38.101 ;
     RECT  42.192 38.011 49.59 38.107 ;
     RECT  88.815 37.741 89.226 38.129 ;
     RECT  2.415 36.653 2.697 38.137 ;
     RECT  56.415 34.421 56.697 38.137 ;
     RECT  123.915 2.413 124.197 38.137 ;
     RECT  2.415 38.137 2.862 38.173 ;
     RECT  52.308 37.867 55.494 38.173 ;
     RECT  56.304 38.137 56.697 38.173 ;
     RECT  61.02 37.427 75.978 38.173 ;
     RECT  18.108 37.741 36.738 38.189 ;
     RECT  42.192 38.107 49.626 38.2 ;
     RECT  5.115 37.867 5.886 38.203 ;
     RECT  52.308 38.173 56.697 38.209 ;
     RECT  58.32 37.895 59.397 38.209 ;
     RECT  115.815 37.037 116.226 38.209 ;
     RECT  115.416 38.209 116.226 38.237 ;
     RECT  121.215 37.867 121.626 38.237 ;
     RECT  38.772 38.005 41.202 38.245 ;
     RECT  52.308 38.209 56.826 38.245 ;
     RECT  91.515 2.413 91.797 38.245 ;
     RECT  38.736 38.245 41.202 38.251 ;
     RECT  50.724 38.101 51.534 38.251 ;
     RECT  52.308 38.245 57.186 38.251 ;
     RECT  18.108 38.189 28.35 38.273 ;
     RECT  2.415 38.173 4.014 38.281 ;
     RECT  38.664 38.251 41.202 38.281 ;
     RECT  42.192 38.2 49.662 38.281 ;
     RECT  50.724 38.251 57.186 38.281 ;
     RECT  61.02 38.173 76.122 38.281 ;
     RECT  99.615 2.413 99.897 38.281 ;
     RECT  100.656 38.101 102.597 38.281 ;
     RECT  18.108 38.273 22.626 38.309 ;
     RECT  38.52 38.281 41.202 38.371 ;
     RECT  42.192 38.281 57.186 38.371 ;
     RECT  80.715 2.413 80.997 38.371 ;
     RECT  81.756 38.155 81.774 38.371 ;
     RECT  2.268 38.281 4.014 38.381 ;
     RECT  23.472 38.273 28.35 38.399 ;
     RECT  80.715 38.371 81.774 38.399 ;
     RECT  96.084 32.801 96.102 38.399 ;
     RECT  38.52 38.371 57.186 38.407 ;
     RECT  80.715 38.399 81.486 38.429 ;
     RECT  88.815 38.129 89.118 38.435 ;
     RECT  90.792 38.245 91.797 38.435 ;
     RECT  38.52 38.407 57.294 38.443 ;
     RECT  22.32 38.309 22.338 38.471 ;
     RECT  29.124 38.189 36.738 38.479 ;
     RECT  37.515 2.413 37.797 38.479 ;
     RECT  18.108 38.309 21.597 38.507 ;
     RECT  61.02 38.281 76.626 38.515 ;
     RECT  145.515 36.893 145.797 38.539 ;
     RECT  4.824 38.203 5.886 38.543 ;
     RECT  7.164 37.661 17.262 38.551 ;
     RECT  18.108 38.507 20.178 38.551 ;
     RECT  2.415 38.381 4.014 38.579 ;
     RECT  6.12 38.551 6.138 38.635 ;
     RECT  6.948 38.551 20.178 38.635 ;
     RECT  211.5 38.479 211.518 38.635 ;
     RECT  21.024 38.507 21.597 38.669 ;
     RECT  211.356 38.635 211.518 38.675 ;
     RECT  29.124 38.479 37.797 38.677 ;
     RECT  38.52 38.443 57.366 38.677 ;
     RECT  212.256 33.269 213.297 38.677 ;
     RECT  23.472 38.399 28.17 38.705 ;
     RECT  6.12 38.635 20.178 38.717 ;
     RECT  60.408 38.515 76.626 38.717 ;
     RECT  140.115 32.027 140.397 38.731 ;
     RECT  6.12 38.717 19.566 38.741 ;
     RECT  214.344 38.683 214.362 38.741 ;
     RECT  58.32 38.209 59.634 38.749 ;
     RECT  60.408 38.717 64.797 38.749 ;
     RECT  4.824 38.543 5.397 38.765 ;
     RECT  6.84 38.741 19.566 38.765 ;
     RECT  29.124 38.677 57.366 38.765 ;
     RECT  145.515 38.539 145.89 38.765 ;
     RECT  65.556 38.717 76.626 38.779 ;
     RECT  107.715 34.529 107.997 38.779 ;
     RECT  58.32 38.749 64.797 38.785 ;
     RECT  99.615 38.281 102.597 38.785 ;
     RECT  6.84 38.765 14.886 38.813 ;
     RECT  99.615 38.785 102.978 38.821 ;
     RECT  104.04 38.479 104.058 38.821 ;
     RECT  140.115 38.731 140.526 38.849 ;
     RECT  96.915 32.027 97.197 38.911 ;
     RECT  86.115 2.413 86.397 38.923 ;
     RECT  2.415 38.579 3.438 38.939 ;
     RECT  6.84 38.813 14.634 38.939 ;
     RECT  15.915 38.765 19.566 38.939 ;
     RECT  96.804 38.911 97.197 38.957 ;
     RECT  2.415 38.939 3.222 38.975 ;
     RECT  17.604 38.939 19.566 38.975 ;
     RECT  212.076 38.677 213.297 38.975 ;
     RECT  78.015 29.597 78.297 38.983 ;
     RECT  33.876 38.765 57.366 39.019 ;
     RECT  58.176 38.785 64.797 39.019 ;
     RECT  78.015 38.983 78.534 39.019 ;
     RECT  17.604 38.975 18.897 39.047 ;
     RECT  86.115 38.923 86.67 39.053 ;
     RECT  15.915 38.939 16.542 39.083 ;
     RECT  17.892 39.047 18.897 39.083 ;
     RECT  65.556 38.779 76.986 39.091 ;
     RECT  77.76 39.019 78.534 39.091 ;
     RECT  6.84 38.939 14.454 39.119 ;
     RECT  6.84 39.119 13.842 39.209 ;
     RECT  26.496 38.705 28.17 39.209 ;
     RECT  33.876 39.019 64.797 39.209 ;
     RECT  106.128 35.851 106.146 39.209 ;
     RECT  29.124 38.765 33.03 39.217 ;
     RECT  23.472 38.705 25.686 39.245 ;
     RECT  26.496 39.209 27.342 39.245 ;
     RECT  33.876 39.209 62.334 39.281 ;
     RECT  107.604 38.779 107.997 39.289 ;
     RECT  199.515 34.591 200.934 39.289 ;
     RECT  61.164 39.281 62.298 39.317 ;
     RECT  63.432 39.209 64.797 39.353 ;
     RECT  33.876 39.281 60.426 39.479 ;
     RECT  65.556 39.091 78.534 39.487 ;
     RECT  79.38 39.019 79.398 39.487 ;
     RECT  28.692 39.217 33.03 39.515 ;
     RECT  24.015 39.245 25.686 39.547 ;
     RECT  26.496 39.245 26.997 39.547 ;
     RECT  28.98 39.515 33.03 39.559 ;
     RECT  33.876 39.479 36.486 39.559 ;
     RECT  64.332 39.353 64.797 39.559 ;
     RECT  65.556 39.487 79.398 39.559 ;
     RECT  80.715 38.429 80.997 39.559 ;
     RECT  63.432 39.353 63.45 39.587 ;
     RECT  64.332 39.559 79.398 39.595 ;
     RECT  80.172 39.559 80.997 39.595 ;
     RECT  83.415 2.413 83.697 39.595 ;
     RECT  199.515 39.289 200.97 39.595 ;
     RECT  28.98 39.559 36.486 39.623 ;
     RECT  98.604 38.923 98.622 39.631 ;
     RECT  156.315 2.413 156.597 39.721 ;
     RECT  156.315 39.721 157.194 39.773 ;
     RECT  64.332 39.595 80.997 39.821 ;
     RECT  76.968 39.821 80.997 39.827 ;
     RECT  77.004 39.827 80.997 39.857 ;
     RECT  98.604 39.631 98.694 39.857 ;
     RECT  159.015 22.577 159.297 39.865 ;
     RECT  77.04 39.857 80.997 39.869 ;
     RECT  6.84 39.209 13.662 39.901 ;
     RECT  24.015 39.547 26.997 39.917 ;
     RECT  99.615 38.821 104.058 39.917 ;
     RECT  158.724 39.865 159.297 39.917 ;
     RECT  24.015 39.917 24.354 40.019 ;
     RECT  37.296 39.479 60.426 40.019 ;
     RECT  199.44 39.595 200.97 40.019 ;
     RECT  61.164 39.317 62.097 40.027 ;
     RECT  25.56 39.917 26.997 40.091 ;
     RECT  26.136 40.091 26.997 40.127 ;
     RECT  28.98 39.623 36.378 40.127 ;
     RECT  28.98 40.127 32.706 40.163 ;
     RECT  64.332 39.821 76.05 40.163 ;
     RECT  113.115 34.619 113.397 40.171 ;
     RECT  65.664 40.163 76.05 40.199 ;
     RECT  87.84 34.493 87.858 40.199 ;
     RECT  6.408 39.901 13.662 40.219 ;
     RECT  26.424 40.127 26.997 40.289 ;
     RECT  37.296 40.019 60.282 40.289 ;
     RECT  65.664 40.199 74.214 40.289 ;
     RECT  126.615 24.899 126.897 40.297 ;
     RECT  29.088 40.163 32.706 40.361 ;
     RECT  65.988 40.289 73.026 40.361 ;
     RECT  74.052 40.289 74.214 40.361 ;
     RECT  100.62 39.917 104.058 40.361 ;
     RECT  66.24 40.361 73.026 40.369 ;
     RECT  126.576 40.297 126.897 40.405 ;
     RECT  105.015 37.229 105.297 40.441 ;
     RECT  125.748 40.171 125.766 40.441 ;
     RECT  126.54 40.405 126.897 40.441 ;
     RECT  66.24 40.369 72.897 40.469 ;
     RECT  103.68 40.361 104.058 40.469 ;
     RECT  2.415 38.975 2.697 40.531 ;
     RECT  37.296 40.289 46.17 40.559 ;
     RECT  66.24 40.469 70.578 40.559 ;
     RECT  77.436 39.869 80.997 40.567 ;
     RECT  37.296 40.559 46.098 40.595 ;
     RECT  83.124 39.595 83.697 40.603 ;
     RECT  66.24 40.559 67.497 40.631 ;
     RECT  99.615 39.917 99.897 40.639 ;
     RECT  100.62 40.361 102.87 40.639 ;
     RECT  122.652 36.893 122.67 40.639 ;
     RECT  50.616 40.289 60.282 40.667 ;
     RECT  68.256 40.559 70.578 40.667 ;
     RECT  77.436 40.567 81.414 40.667 ;
     RECT  37.296 40.595 44.046 40.685 ;
     RECT  66.708 40.631 67.497 40.685 ;
     RECT  68.256 40.667 70.254 40.685 ;
     RECT  46.908 40.289 49.842 40.703 ;
     RECT  50.616 40.667 59.49 40.703 ;
     RECT  68.256 40.685 69.066 40.703 ;
     RECT  69.876 40.685 70.254 40.703 ;
     RECT  2.415 40.531 2.934 40.711 ;
     RECT  6.264 40.219 13.662 40.711 ;
     RECT  33.624 40.127 36.378 40.711 ;
     RECT  37.296 40.685 41.598 40.711 ;
     RECT  61.092 40.027 62.097 40.711 ;
     RECT  83.088 40.603 83.697 40.711 ;
     RECT  96.915 38.957 97.197 40.711 ;
     RECT  98.64 40.639 98.658 40.711 ;
     RECT  167.115 34.627 167.85 40.711 ;
     RECT  44.82 40.595 46.098 40.739 ;
     RECT  61.092 40.711 62.73 40.787 ;
     RECT  67.215 40.685 67.497 40.787 ;
     RECT  72.615 40.469 72.897 40.787 ;
     RECT  77.436 40.667 78.297 40.787 ;
     RECT  129.315 21.299 129.597 40.787 ;
     RECT  132.015 2.413 132.297 40.787 ;
     RECT  134.715 2.413 134.997 40.787 ;
     RECT  137.415 2.413 137.697 40.787 ;
     RECT  140.115 38.849 140.397 40.787 ;
     RECT  142.815 2.413 143.097 40.787 ;
     RECT  145.515 38.765 145.797 40.787 ;
     RECT  148.215 2.413 148.497 40.787 ;
     RECT  150.915 4.181 151.197 40.787 ;
     RECT  153.615 36.893 153.897 40.787 ;
     RECT  156.315 39.773 156.597 40.787 ;
     RECT  159.015 39.917 159.297 40.787 ;
     RECT  161.715 36.893 161.997 40.787 ;
     RECT  164.415 2.413 164.697 40.787 ;
     RECT  77.436 40.787 78.105 40.801 ;
     RECT  6.264 40.711 13.842 40.829 ;
     RECT  45 40.739 46.098 40.829 ;
     RECT  46.944 40.703 49.842 40.829 ;
     RECT  57.78 40.703 59.49 40.829 ;
     RECT  68.256 40.703 68.454 40.829 ;
     RECT  69.915 40.703 70.254 40.829 ;
     RECT  79.092 40.667 81.414 40.829 ;
     RECT  99.615 40.639 102.87 40.829 ;
     RECT  125.748 40.441 126.897 40.837 ;
     RECT  45.468 40.829 45.705 40.865 ;
     RECT  50.616 40.703 57.042 40.865 ;
     RECT  79.092 40.829 79.11 40.865 ;
     RECT  96.915 40.711 97.794 40.865 ;
     RECT  98.604 40.711 98.658 40.873 ;
     RECT  105.015 40.441 105.57 40.873 ;
     RECT  80.064 40.829 81.414 40.877 ;
     RECT  13.215 40.829 13.842 40.901 ;
     RECT  46.944 40.829 49.194 40.901 ;
     RECT  56.376 40.865 57.042 40.901 ;
     RECT  57.78 40.829 59.274 40.901 ;
     RECT  60.264 40.667 60.282 40.901 ;
     RECT  76.968 40.801 78.105 40.901 ;
     RECT  62.712 40.787 62.73 40.909 ;
     RECT  50.616 40.865 55.17 40.937 ;
     RECT  62.712 40.909 62.802 40.937 ;
     RECT  64.332 40.163 64.854 40.937 ;
     RECT  76.968 40.901 76.986 40.937 ;
     RECT  80.172 40.877 81.414 40.937 ;
     RECT  5.115 38.765 5.397 40.945 ;
     RECT  61.092 40.787 61.905 40.945 ;
     RECT  42.516 40.685 44.046 40.973 ;
     RECT  51.912 40.937 54.918 40.973 ;
     RECT  56.376 40.901 57.006 40.973 ;
     RECT  58.068 40.901 59.274 40.973 ;
     RECT  80.172 40.937 81.342 40.973 ;
     RECT  99.615 40.829 100.746 40.973 ;
     RECT  101.664 40.829 102.87 40.973 ;
     RECT  18.615 39.083 18.897 40.981 ;
     RECT  64.332 40.937 64.674 40.981 ;
     RECT  0.54 40.843 0.558 41.009 ;
     RECT  46.944 40.901 48.405 41.009 ;
     RECT  49.176 40.901 49.194 41.009 ;
     RECT  51.912 40.973 52.578 41.009 ;
     RECT  54.9 40.973 54.918 41.009 ;
     RECT  58.644 40.973 59.274 41.009 ;
     RECT  62.784 40.937 62.802 41.009 ;
     RECT  64.224 40.981 64.674 41.009 ;
     RECT  98.604 40.873 98.694 41.009 ;
     RECT  101.736 40.973 102.87 41.009 ;
     RECT  47.448 41.009 48.405 41.021 ;
     RECT  45.615 40.865 45.705 41.057 ;
     RECT  48.315 41.021 48.405 41.057 ;
     RECT  50.616 40.937 51.105 41.057 ;
     RECT  53.715 40.973 53.982 41.057 ;
     RECT  59.115 41.009 59.205 41.057 ;
     RECT  60.444 40.945 61.905 41.057 ;
     RECT  64.224 41.009 64.605 41.057 ;
     RECT  67.215 40.787 67.374 41.057 ;
     RECT  69.915 40.829 70.005 41.057 ;
     RECT  72.615 40.787 72.705 41.057 ;
     RECT  75.315 40.199 76.05 41.057 ;
     RECT  78.015 40.901 78.105 41.057 ;
     RECT  80.28 40.973 81.342 41.057 ;
     RECT  129.315 40.787 129.405 41.057 ;
     RECT  132.015 40.787 132.105 41.057 ;
     RECT  134.715 40.787 134.805 41.057 ;
     RECT  137.415 40.787 137.505 41.057 ;
     RECT  140.115 40.787 140.205 41.057 ;
     RECT  142.815 40.787 142.905 41.057 ;
     RECT  145.515 40.787 145.605 41.057 ;
     RECT  148.215 40.787 148.305 41.057 ;
     RECT  150.915 40.787 151.005 41.057 ;
     RECT  153.615 40.787 153.705 41.057 ;
     RECT  156.315 40.787 156.405 41.057 ;
     RECT  159.015 40.787 159.105 41.057 ;
     RECT  161.715 40.787 161.805 41.057 ;
     RECT  164.415 40.787 164.505 41.057 ;
     RECT  167.115 40.711 167.886 41.057 ;
     RECT  5.115 40.945 5.526 41.071 ;
     RECT  6.264 40.829 7.074 41.071 ;
     RECT  21.315 38.669 21.597 41.071 ;
     RECT  29.415 40.361 32.706 41.071 ;
     RECT  33.624 40.711 41.598 41.071 ;
     RECT  2.415 40.711 2.97 41.099 ;
     RECT  121.215 38.237 121.554 41.107 ;
     RECT  18.288 40.981 18.897 41.117 ;
     RECT  2.415 41.099 2.862 41.135 ;
     RECT  121.215 41.107 121.59 41.143 ;
     RECT  122.58 40.639 122.67 41.143 ;
     RECT  121.215 41.143 122.67 41.173 ;
     RECT  123.84 38.137 124.197 41.173 ;
     RECT  210.315 36.32 210.597 41.179 ;
     RECT  210.315 41.179 210.69 41.251 ;
     RECT  210.315 41.251 211.014 41.323 ;
     RECT  51.912 41.009 51.93 41.324 ;
     RECT  103.68 40.469 103.698 41.341 ;
     RECT  7.815 40.829 12.438 41.369 ;
     RECT  100.728 40.973 100.746 41.369 ;
     RECT  121.215 41.173 124.197 41.369 ;
     RECT  209.736 41.323 211.014 41.369 ;
     RECT  103.68 41.341 103.77 41.377 ;
     RECT  104.976 40.873 105.57 41.377 ;
     RECT  121.215 41.369 122.382 41.377 ;
     RECT  5.115 41.071 7.074 41.405 ;
     RECT  25.452 41.251 25.47 41.405 ;
     RECT  67.356 41.057 67.374 41.405 ;
     RECT  74.052 40.361 74.07 41.405 ;
     RECT  214.308 41.413 214.326 41.453 ;
     RECT  121.104 41.377 122.382 41.467 ;
     RECT  212.256 38.975 213.297 41.467 ;
     RECT  56.376 40.973 56.754 41.477 ;
     RECT  123.48 41.369 124.197 41.485 ;
     RECT  125.316 40.837 126.897 41.485 ;
     RECT  75.78 41.057 76.05 41.513 ;
     RECT  20.124 40.441 20.142 41.521 ;
     RECT  75.852 41.513 76.05 41.549 ;
     RECT  211.752 41.467 213.534 41.549 ;
     RECT  27.936 41.605 27.954 41.611 ;
     RECT  210.276 41.369 210.69 41.639 ;
     RECT  211.752 41.549 213.297 41.675 ;
     RECT  100.908 41.611 100.926 41.683 ;
     RECT  123.48 41.485 126.897 41.683 ;
     RECT  7.815 41.369 11.322 41.719 ;
     RECT  5.115 41.405 6.822 41.747 ;
     RECT  26.715 40.289 26.997 41.755 ;
     RECT  27.936 41.611 28.674 41.755 ;
     RECT  29.415 41.071 41.598 41.755 ;
     RECT  42.516 40.973 43.83 41.755 ;
     RECT  118.515 34.763 118.797 41.755 ;
     RECT  20.124 41.521 20.394 41.791 ;
     RECT  21.204 41.071 21.597 41.791 ;
     RECT  120.564 41.467 122.382 41.791 ;
     RECT  64.224 41.057 64.494 41.819 ;
     RECT  102.024 41.009 102.87 41.881 ;
     RECT  103.68 41.377 105.57 41.881 ;
     RECT  22.824 41.083 22.842 41.899 ;
     RECT  118.515 41.755 119.43 41.899 ;
     RECT  120.42 41.791 122.382 41.899 ;
     RECT  19.944 41.791 21.597 41.909 ;
     RECT  26.28 41.755 43.83 41.909 ;
     RECT  60.444 41.057 61.182 41.909 ;
     RECT  21.315 41.909 21.597 41.917 ;
     RECT  118.515 41.899 122.382 41.917 ;
     RECT  19.944 41.909 20.142 41.945 ;
     RECT  56.376 41.477 56.394 41.945 ;
     RECT  83.016 40.711 83.697 41.947 ;
     RECT  86.115 39.053 86.397 41.947 ;
     RECT  118.476 41.917 122.382 41.953 ;
     RECT  5.115 41.747 6.714 41.981 ;
     RECT  27.972 41.909 43.83 41.981 ;
     RECT  64.476 41.819 64.494 41.981 ;
     RECT  118.26 41.953 122.382 41.989 ;
     RECT  22.824 41.899 22.914 42.017 ;
     RECT  22.896 42.017 22.914 42.029 ;
     RECT  28.728 41.981 43.83 42.053 ;
     RECT  99.615 40.973 99.897 42.061 ;
     RECT  128.628 42.025 128.646 42.061 ;
     RECT  82.656 41.947 83.697 42.077 ;
     RECT  86.115 41.947 86.67 42.077 ;
     RECT  99.504 42.061 99.897 42.125 ;
     RECT  94.215 32.063 94.497 42.139 ;
     RECT  112.176 41.791 112.194 42.151 ;
     RECT  113.115 40.171 113.598 42.151 ;
     RECT  128.592 42.061 128.646 42.151 ;
     RECT  5.115 41.981 5.994 42.173 ;
     RECT  28.8 42.053 43.83 42.179 ;
     RECT  93.024 41.947 93.042 42.179 ;
     RECT  94.068 42.139 94.497 42.179 ;
     RECT  117.684 41.989 122.382 42.187 ;
     RECT  29.376 42.179 43.83 42.215 ;
     RECT  99.615 42.125 99.897 42.223 ;
     RECT  100.908 41.683 100.962 42.223 ;
     RECT  99.615 42.223 100.962 42.235 ;
     RECT  99.615 42.235 101.034 42.259 ;
     RECT  102.024 41.881 105.57 42.259 ;
     RECT  99.615 42.259 105.57 42.287 ;
     RECT  112.176 42.151 113.598 42.295 ;
     RECT  15.915 39.083 16.197 42.331 ;
     RECT  107.244 39.289 107.997 42.331 ;
     RECT  110.415 2.413 110.697 42.331 ;
     RECT  111.492 42.295 113.598 42.331 ;
     RECT  115.416 38.237 116.097 42.331 ;
     RECT  117.684 42.187 122.454 42.331 ;
     RECT  123.48 41.683 127.062 42.331 ;
     RECT  123.264 42.331 127.062 42.379 ;
     RECT  81.324 41.057 81.342 42.457 ;
     RECT  115.416 42.331 122.454 42.457 ;
     RECT  123.192 42.379 127.062 42.457 ;
     RECT  60.444 41.909 60.462 42.461 ;
     RECT  81.252 42.457 81.342 42.493 ;
     RECT  106.344 42.457 106.362 42.493 ;
     RECT  110.415 42.331 113.634 42.493 ;
     RECT  115.416 42.457 127.062 42.529 ;
     RECT  29.376 42.215 43.146 42.557 ;
     RECT  7.74 41.719 11.322 42.565 ;
     RECT  86.115 42.077 86.397 42.565 ;
     RECT  128.52 42.151 128.646 42.565 ;
     RECT  110.415 42.493 113.886 42.571 ;
     RECT  88.815 38.435 89.097 42.601 ;
     RECT  110.415 42.571 114.606 42.601 ;
     RECT  171.216 42.565 171.234 42.601 ;
     RECT  172.515 36.461 172.797 42.601 ;
     RECT  191.415 36.959 191.697 42.601 ;
     RECT  192.672 42.523 192.69 42.601 ;
     RECT  191.415 42.601 192.69 42.629 ;
     RECT  80.28 41.057 80.298 42.646 ;
     RECT  191.415 42.629 192.186 42.653 ;
     RECT  82.908 42.077 83.697 42.691 ;
     RECT  88.815 42.601 89.514 42.691 ;
     RECT  169.815 36.893 170.097 42.691 ;
     RECT  107.244 42.331 108.09 42.727 ;
     RECT  88.815 42.691 89.766 42.749 ;
     RECT  104.904 42.287 105.57 42.749 ;
     RECT  33.3 42.557 43.146 42.755 ;
     RECT  6.84 42.565 11.322 42.757 ;
     RECT  109.872 42.601 114.606 42.763 ;
     RECT  115.416 42.529 127.206 42.763 ;
     RECT  29.376 42.557 32.49 42.791 ;
     RECT  6.66 42.757 11.322 42.797 ;
     RECT  106.344 42.493 106.506 42.799 ;
     RECT  107.244 42.727 108.126 42.799 ;
     RECT  109.872 42.763 127.206 42.799 ;
     RECT  109.584 42.799 127.206 42.811 ;
     RECT  30.636 42.791 32.49 42.827 ;
     RECT  7.38 42.797 11.322 42.863 ;
     RECT  88.815 42.749 89.514 42.871 ;
     RECT  109.548 42.811 127.206 42.961 ;
     RECT  29.376 42.791 29.754 42.997 ;
     RECT  88.344 42.871 89.514 42.997 ;
     RECT  109.404 42.961 127.206 42.997 ;
     RECT  29.304 42.997 29.754 43.033 ;
     RECT  109.332 42.997 127.206 43.033 ;
     RECT  169.815 42.691 170.298 43.033 ;
     RECT  171.216 42.601 172.797 43.033 ;
     RECT  88.2 42.997 89.514 43.037 ;
     RECT  99.615 42.287 103.842 43.069 ;
     RECT  104.94 42.749 105.57 43.099 ;
     RECT  106.344 42.799 108.126 43.099 ;
     RECT  29.196 43.033 29.754 43.105 ;
     RECT  99.615 43.069 104.094 43.105 ;
     RECT  104.94 43.099 108.126 43.105 ;
     RECT  109.332 43.033 127.71 43.105 ;
     RECT  98.604 43.003 98.622 43.133 ;
     RECT  99.615 43.105 104.166 43.133 ;
     RECT  27.972 41.981 27.99 43.141 ;
     RECT  29.016 43.105 29.754 43.141 ;
     RECT  81.252 42.493 81.774 43.141 ;
     RECT  33.552 42.755 43.146 43.2 ;
     RECT  46.728 42.601 46.746 43.2 ;
     RECT  50.616 41.057 50.634 43.2 ;
     RECT  53.964 41.057 53.982 43.2 ;
     RECT  75.852 41.549 75.87 43.2 ;
     RECT  80.208 42.646 80.298 43.2 ;
     RECT  81.252 43.141 81.81 43.2 ;
     RECT  128.52 42.565 129.258 43.2 ;
     RECT  167.832 41.057 167.886 43.2 ;
     RECT  2.415 41.135 2.697 43.231 ;
     RECT  179.748 42.715 179.766 43.259 ;
     RECT  182.412 43.231 182.43 43.331 ;
     RECT  27.972 43.141 29.754 43.339 ;
     RECT  2.415 43.231 2.934 43.387 ;
     RECT  104.94 43.105 127.71 43.403 ;
     RECT  2.268 43.387 2.934 43.439 ;
     RECT  104.94 43.403 124.794 43.439 ;
     RECT  125.676 43.403 127.71 43.573 ;
     RECT  30.78 42.827 32.49 43.609 ;
     RECT  33.552 43.2 81.81 43.609 ;
     RECT  101.304 43.133 104.166 43.609 ;
     RECT  104.94 43.439 124.758 43.609 ;
     RECT  2.415 43.439 2.934 43.645 ;
     RECT  7.632 42.863 11.322 43.645 ;
     RECT  169.815 43.033 172.797 43.645 ;
     RECT  199.515 40.019 200.97 43.681 ;
     RECT  30.78 43.609 81.81 43.771 ;
     RECT  189.792 43.681 189.81 43.771 ;
     RECT  2.415 43.645 3.654 43.799 ;
     RECT  6.588 43.681 6.606 43.799 ;
     RECT  7.38 43.645 11.322 43.799 ;
     RECT  189.792 43.771 190.422 43.799 ;
     RECT  2.415 43.799 2.826 43.835 ;
     RECT  210.315 41.639 210.69 43.843 ;
     RECT  3.636 43.799 3.654 43.871 ;
     RECT  27.828 43.339 29.754 43.871 ;
     RECT  101.304 43.609 124.758 43.871 ;
     RECT  190.404 43.799 190.422 43.871 ;
     RECT  199.515 43.681 201.186 43.871 ;
     RECT  27.972 43.871 29.754 43.879 ;
     RECT  30.672 43.771 81.81 43.879 ;
     RECT  209.808 43.843 210.69 43.943 ;
     RECT  169.776 43.645 172.797 43.997 ;
     RECT  169.815 43.997 172.797 44.069 ;
     RECT  7.632 43.799 11.322 44.105 ;
     RECT  27.972 43.879 81.81 44.105 ;
     RECT  12.132 41.369 12.438 44.113 ;
     RECT  13.215 40.901 13.497 44.113 ;
     RECT  27.972 44.105 28.494 44.177 ;
     RECT  109.152 43.871 124.758 44.185 ;
     RECT  208.656 43.915 208.674 44.185 ;
     RECT  209.808 43.943 210.597 44.185 ;
     RECT  82.908 42.691 83.97 44.221 ;
     RECT  207.615 36.275 207.897 44.221 ;
     RECT  208.656 44.185 210.597 44.221 ;
     RECT  29.415 44.105 81.81 44.249 ;
     RECT  82.908 44.221 84.438 44.249 ;
     RECT  109.152 44.185 124.902 44.311 ;
     RECT  125.676 43.573 127.746 44.311 ;
     RECT  128.52 43.2 167.886 44.311 ;
     RECT  83.34 44.249 84.438 44.339 ;
     RECT  207.615 44.221 210.597 44.339 ;
     RECT  83.34 44.339 83.97 44.375 ;
     RECT  214.344 44.203 214.362 44.411 ;
     RECT  207.615 44.339 208.962 44.429 ;
     RECT  109.152 44.311 167.886 44.477 ;
     RECT  208.656 44.429 208.962 44.609 ;
     RECT  101.304 43.871 108.342 44.617 ;
     RECT  169.815 44.069 170.154 44.789 ;
     RECT  198.036 42.727 198.054 44.851 ;
     RECT  109.872 44.477 167.886 44.879 ;
     RECT  101.304 44.617 109.062 44.887 ;
     RECT  198.036 44.851 198.378 44.951 ;
     RECT  109.872 44.879 167.616 44.957 ;
     RECT  30.564 44.249 81.81 45.023 ;
     RECT  99.615 43.133 100.314 45.031 ;
     RECT  101.16 44.887 109.062 45.031 ;
     RECT  109.872 44.957 127.746 45.053 ;
     RECT  30.78 45.023 81.81 45.149 ;
     RECT  209.808 44.339 210.597 45.265 ;
     RECT  27.972 44.177 27.99 45.301 ;
     RECT  199.515 43.871 201.042 45.301 ;
     RECT  21.315 41.917 21.942 45.391 ;
     RECT  15.372 42.331 16.197 45.403 ;
     RECT  31.824 45.149 81.81 45.491 ;
     RECT  6.732 45.403 6.858 45.533 ;
     RECT  22.824 45.403 22.842 45.533 ;
     RECT  99.615 45.031 109.062 45.535 ;
     RECT  109.872 45.053 127.422 45.535 ;
     RECT  3.744 45.499 3.762 45.547 ;
     RECT  27.72 45.301 27.99 45.599 ;
     RECT  31.932 45.491 81.81 45.833 ;
     RECT  207.615 44.429 207.897 45.841 ;
     RECT  30.78 45.149 30.798 45.869 ;
     RECT  2.415 43.835 2.697 45.931 ;
     RECT  26.715 41.909 26.997 45.931 ;
     RECT  31.968 45.833 81.81 45.959 ;
     RECT  99.615 45.535 127.422 45.959 ;
     RECT  27.972 45.599 27.99 45.965 ;
     RECT  128.52 44.957 167.616 45.967 ;
     RECT  21.204 45.391 21.942 45.968 ;
     RECT  31.968 45.959 33.786 45.995 ;
     RECT  3.744 45.547 3.978 46.027 ;
     RECT  33.3 45.995 33.786 46.031 ;
     RECT  99.615 45.959 126.897 46.031 ;
     RECT  3.744 46.027 4.302 46.039 ;
     RECT  14.832 45.403 16.197 46.061 ;
     RECT  26.676 45.931 26.997 46.061 ;
     RECT  2.304 45.931 2.697 46.103 ;
     RECT  101.124 46.031 126.897 46.103 ;
     RECT  2.415 46.103 2.697 46.111 ;
     RECT  3.42 46.039 4.302 46.111 ;
     RECT  5.115 42.173 5.397 46.111 ;
     RECT  0.54 45.883 0.558 46.139 ;
     RECT  128.268 45.967 167.616 46.201 ;
     RECT  34.632 45.959 81.81 46.229 ;
     RECT  101.448 46.103 126.897 46.265 ;
     RECT  31.968 45.995 32.397 46.409 ;
     RECT  128.196 46.201 167.616 46.471 ;
     RECT  33.3 46.031 33.498 46.499 ;
     RECT  101.556 46.265 126.897 46.535 ;
     RECT  2.415 46.111 5.397 46.571 ;
     RECT  102.315 46.535 126.897 46.571 ;
     RECT  102.315 46.571 105.966 46.607 ;
     RECT  3.492 46.571 5.397 46.679 ;
     RECT  127.692 46.471 167.616 46.685 ;
     RECT  20.124 41.945 20.142 46.741 ;
     RECT  106.812 46.571 126.897 46.741 ;
     RECT  29.415 44.249 29.697 46.747 ;
     RECT  19.62 46.741 20.142 46.781 ;
     RECT  34.815 46.229 81.81 46.805 ;
     RECT  102.315 46.607 105.93 46.829 ;
     RECT  34.815 46.805 36.558 46.841 ;
     RECT  29.415 46.747 29.79 46.877 ;
     RECT  30.78 46.747 30.798 46.877 ;
     RECT  37.296 46.805 81.81 46.913 ;
     RECT  207.504 45.841 207.897 46.921 ;
     RECT  103.716 46.829 105.93 46.949 ;
     RECT  208.656 44.609 208.674 46.949 ;
     RECT  212.292 41.675 213.297 47.011 ;
     RECT  34.815 46.841 36.378 47.039 ;
     RECT  103.716 46.949 105.858 47.039 ;
     RECT  34.815 47.039 36.27 47.075 ;
     RECT  209.808 45.265 211.014 47.083 ;
     RECT  214.344 46.939 214.362 47.111 ;
     RECT  212.22 47.011 213.297 47.117 ;
     RECT  206.676 47.119 206.694 47.131 ;
     RECT  206.532 47.131 206.694 47.155 ;
     RECT  207.468 46.921 207.897 47.155 ;
     RECT  206.532 47.155 207.897 47.165 ;
     RECT  103.716 47.039 105.297 47.183 ;
     RECT  206.532 47.165 206.55 47.183 ;
     RECT  104.436 47.183 105.297 47.219 ;
     RECT  3.708 46.679 5.397 47.281 ;
     RECT  3.708 47.281 5.742 47.309 ;
     RECT  36.252 47.075 36.27 47.309 ;
     RECT  37.515 46.913 81.81 47.309 ;
     RECT  106.812 46.741 127.53 47.309 ;
     RECT  207.324 47.165 207.897 47.309 ;
     RECT  3.78 47.309 5.742 47.315 ;
     RECT  106.812 47.309 126.897 47.317 ;
     RECT  209.556 47.083 211.014 47.345 ;
     RECT  106.74 47.317 126.897 47.357 ;
     RECT  106.812 47.357 126.897 47.453 ;
     RECT  127.656 47.461 127.71 47.549 ;
     RECT  39.852 47.309 81.81 47.579 ;
     RECT  106.812 47.453 121.626 47.579 ;
     RECT  37.515 47.309 38.97 47.615 ;
     RECT  113.004 47.579 121.626 47.615 ;
     RECT  39.996 47.579 81.81 47.651 ;
     RECT  106.812 47.579 111.906 47.687 ;
     RECT  113.115 47.615 121.626 47.693 ;
     RECT  114.12 47.693 121.626 47.723 ;
     RECT  106.812 47.687 111.69 47.759 ;
     RECT  108.756 47.759 111.69 47.849 ;
     RECT  122.544 47.453 126.897 47.849 ;
     RECT  108.756 47.849 108.774 47.885 ;
     RECT  114.12 47.723 118.797 47.885 ;
     RECT  119.52 47.723 121.626 47.885 ;
     RECT  124.92 47.849 126.897 47.933 ;
     RECT  119.52 47.885 119.682 48.029 ;
     RECT  37.515 47.615 38.718 48.119 ;
     RECT  40.068 47.651 81.81 48.119 ;
     RECT  109.548 47.849 111.69 48.119 ;
     RECT  114.12 47.885 117.594 48.119 ;
     RECT  124.92 47.933 125.226 48.119 ;
     RECT  127.656 47.549 127.674 48.119 ;
     RECT  114.984 48.119 116.874 48.155 ;
     RECT  122.544 47.849 124.197 48.155 ;
     RECT  126 47.933 126.897 48.155 ;
     RECT  114.12 48.119 114.138 48.191 ;
     RECT  3.924 47.315 5.742 48.199 ;
     RECT  114.984 48.155 116.097 48.227 ;
     RECT  109.548 48.119 111.366 48.263 ;
     RECT  114.984 48.227 115.002 48.263 ;
     RECT  3.924 48.199 5.85 48.271 ;
     RECT  126.615 48.155 126.897 48.271 ;
     RECT  116.856 48.155 116.874 48.299 ;
     RECT  37.515 48.119 38.394 48.389 ;
     RECT  40.068 48.119 40.497 48.389 ;
     RECT  41.292 48.119 81.81 48.389 ;
     RECT  109.548 48.263 109.566 48.389 ;
     RECT  110.415 48.263 111.366 48.389 ;
     RECT  3.456 48.271 6.534 48.425 ;
     RECT  37.515 48.389 38.286 48.425 ;
     RECT  2.415 46.571 2.697 48.427 ;
     RECT  3.456 48.425 5.742 48.461 ;
     RECT  122.544 48.155 122.562 48.461 ;
     RECT  126.615 48.271 127.242 48.461 ;
     RECT  2.376 48.427 2.697 48.541 ;
     RECT  3.456 48.461 3.942 48.541 ;
     RECT  7.632 44.105 11.178 48.541 ;
     RECT  123.336 48.155 124.197 48.619 ;
     RECT  2.376 48.541 3.942 48.659 ;
     RECT  123.336 48.619 124.434 48.659 ;
     RECT  2.415 48.659 2.862 48.929 ;
     RECT  3.924 48.659 3.942 48.929 ;
     RECT  2.415 48.929 2.754 48.965 ;
     RECT  6.516 48.425 6.534 49.171 ;
     RECT  6.516 49.171 6.714 49.207 ;
     RECT  7.488 48.541 11.178 49.207 ;
     RECT  4.752 48.461 5.742 49.271 ;
     RECT  6.516 49.207 11.178 49.279 ;
     RECT  19.944 46.781 20.142 49.279 ;
     RECT  21.315 45.968 21.942 49.279 ;
     RECT  4.752 49.271 5.397 49.315 ;
     RECT  4.608 49.315 5.397 49.469 ;
     RECT  6.228 49.279 11.178 49.469 ;
     RECT  209.808 47.345 211.014 49.579 ;
     RECT  209.808 49.579 211.338 49.621 ;
     RECT  6.228 49.469 6.246 49.739 ;
     RECT  209.808 49.621 211.518 49.739 ;
     RECT  209.808 49.739 211.338 49.811 ;
     RECT  212.292 47.117 213.297 49.855 ;
     RECT  19.944 49.279 21.942 49.883 ;
     RECT  214.344 49.675 214.362 49.883 ;
     RECT  212.184 49.855 213.297 50.009 ;
     RECT  19.98 49.883 21.942 50.153 ;
     RECT  7.632 49.469 11.178 50.431 ;
     RECT  7.632 50.431 11.286 50.557 ;
     RECT  12.132 44.113 13.497 50.557 ;
     RECT  7.632 50.557 13.497 50.935 ;
     RECT  6.408 50.731 6.426 50.963 ;
     RECT  7.344 50.935 13.497 50.971 ;
     RECT  0.216 50.923 0.234 50.999 ;
     RECT  2.415 48.965 2.697 51.061 ;
     RECT  7.02 50.971 13.497 51.161 ;
     RECT  5.115 49.469 5.397 51.169 ;
     RECT  2.415 51.061 3.186 51.197 ;
     RECT  4.572 51.169 5.397 51.395 ;
     RECT  2.415 51.197 2.934 51.503 ;
     RECT  83.376 44.375 83.97 52.439 ;
     RECT  209.808 49.811 211.014 52.439 ;
     RECT  209.808 52.439 210.69 52.459 ;
     RECT  209.7 52.459 210.69 52.511 ;
     RECT  214.344 52.459 214.362 52.583 ;
     RECT  85.392 42.565 86.397 52.591 ;
     RECT  212.292 50.009 213.297 52.681 ;
     RECT  84.708 52.591 86.397 52.709 ;
     RECT  209.808 52.511 210.69 52.709 ;
     RECT  212.184 52.681 213.297 52.709 ;
     RECT  41.868 48.389 81.81 53.249 ;
     RECT  128.52 46.685 167.616 53.285 ;
     RECT  2.415 51.503 2.697 53.491 ;
     RECT  0.216 53.467 0.234 53.519 ;
     RECT  2.415 53.491 3.438 53.591 ;
     RECT  6.624 53.563 6.642 53.599 ;
     RECT  6.624 53.599 6.858 53.671 ;
     RECT  6.516 53.671 6.858 53.699 ;
     RECT  6.516 53.699 6.642 53.789 ;
     RECT  6.516 53.789 6.534 53.825 ;
     RECT  2.415 53.591 3.366 53.933 ;
     RECT  20.7 50.153 21.942 54.869 ;
     RECT  207.615 47.309 207.897 55.111 ;
     RECT  212.184 52.709 212.202 55.111 ;
     RECT  213.015 52.709 213.297 55.111 ;
     RECT  209.808 52.709 210.654 55.139 ;
     RECT  207.615 55.111 208.278 55.255 ;
     RECT  209.052 54.715 209.07 55.255 ;
     RECT  212.184 55.111 213.297 55.277 ;
     RECT  214.344 55.195 214.362 55.283 ;
     RECT  210.315 55.139 210.654 55.291 ;
     RECT  207.615 55.255 209.07 55.325 ;
     RECT  15.372 46.061 16.197 55.387 ;
     RECT  28.26 55.291 28.278 55.409 ;
     RECT  208.944 55.325 209.07 55.409 ;
     RECT  210.315 55.291 210.762 55.409 ;
     RECT  210.315 55.409 210.654 55.445 ;
     RECT  14.832 55.387 16.197 55.517 ;
     RECT  22.824 55.387 22.842 55.517 ;
     RECT  28.44 55.483 28.458 55.589 ;
     RECT  2.415 53.933 2.697 55.651 ;
     RECT  2.304 55.651 2.697 55.831 ;
     RECT  1.728 55.831 2.754 55.867 ;
     RECT  5.115 51.395 5.397 55.867 ;
     RECT  171.216 44.069 172.797 55.949 ;
     RECT  5.115 55.867 5.562 55.957 ;
     RECT  1.728 55.867 3.114 56.045 ;
     RECT  5.115 55.957 6.174 56.065 ;
     RECT  2.376 56.045 3.114 56.101 ;
     RECT  2.376 56.101 3.294 56.255 ;
     RECT  4.86 56.065 6.174 56.291 ;
     RECT  4.068 56.065 4.086 56.299 ;
     RECT  4.86 56.291 5.994 56.299 ;
     RECT  4.068 56.299 5.994 56.363 ;
     RECT  4.32 56.363 5.994 56.399 ;
     RECT  4.392 56.399 5.994 56.525 ;
     RECT  2.415 56.255 3.294 56.597 ;
     RECT  2.415 56.597 2.898 56.759 ;
     RECT  171.792 55.949 172.797 56.759 ;
     RECT  2.415 56.759 2.826 56.795 ;
     RECT  171.036 56.101 171.054 56.911 ;
     RECT  123.336 48.659 124.197 57.029 ;
     RECT  126.615 48.461 126.897 57.037 ;
     RECT  126.504 57.037 126.897 57.173 ;
     RECT  7.74 51.161 13.497 57.181 ;
     RECT  7.416 57.181 13.497 57.299 ;
     RECT  106.812 47.759 107.997 57.299 ;
     RECT  106.812 57.299 106.83 57.335 ;
     RECT  5.115 56.525 5.994 57.379 ;
     RECT  5.115 57.379 6.174 57.415 ;
     RECT  5.115 57.415 6.462 57.451 ;
     RECT  196.815 34.655 197.097 57.451 ;
     RECT  198.036 44.951 198.054 57.451 ;
     RECT  5.115 57.451 6.858 57.569 ;
     RECT  7.74 57.299 13.497 57.569 ;
     RECT  120.492 47.885 121.626 57.569 ;
     RECT  196.815 57.451 198.054 57.569 ;
     RECT  128.52 53.285 128.61 57.605 ;
     RECT  171.036 56.911 171.126 57.749 ;
     RECT  199.515 45.301 201.114 57.811 ;
     RECT  209.052 55.409 209.07 57.931 ;
     RECT  210.315 55.445 210.597 57.931 ;
     RECT  212.184 55.277 212.202 57.931 ;
     RECT  213.015 55.277 213.297 57.931 ;
     RECT  214.308 57.919 214.326 57.965 ;
     RECT  171.108 57.749 171.126 58.109 ;
     RECT  206.532 57.595 206.55 58.117 ;
     RECT  207.615 55.325 207.897 58.117 ;
     RECT  206.532 58.117 207.897 58.145 ;
     RECT  209.052 57.931 210.597 58.145 ;
     RECT  206.676 58.145 207.897 58.157 ;
     RECT  209.88 58.145 210.597 58.157 ;
     RECT  209.052 58.145 209.07 58.181 ;
     RECT  2.415 56.795 2.697 58.261 ;
     RECT  119.664 48.029 119.682 58.261 ;
     RECT  128.52 57.605 128.538 58.289 ;
     RECT  15.372 55.517 16.197 58.351 ;
     RECT  210.315 58.157 210.597 58.351 ;
     RECT  5.115 57.569 6.462 58.379 ;
     RECT  119.52 58.261 119.682 58.379 ;
     RECT  119.52 58.379 119.538 58.415 ;
     RECT  120.492 57.569 121.497 58.415 ;
     RECT  6.156 58.379 6.462 58.487 ;
     RECT  2.268 58.261 3.15 58.495 ;
     RECT  6.228 58.487 6.462 58.523 ;
     RECT  2.268 58.495 3.546 58.541 ;
     RECT  199.515 57.811 201.15 58.555 ;
     RECT  10.515 57.569 13.497 58.559 ;
     RECT  14.76 58.351 16.197 58.559 ;
     RECT  2.415 58.541 3.546 58.649 ;
     RECT  210.315 58.351 211.014 58.657 ;
     RECT  2.415 58.649 2.754 58.685 ;
     RECT  6.552 58.531 6.57 58.721 ;
     RECT  3.528 58.649 3.546 58.801 ;
     RECT  199.515 58.555 201.186 58.885 ;
     RECT  169.815 44.789 170.097 58.891 ;
     RECT  177.915 36.893 178.197 58.891 ;
     RECT  188.715 36.797 188.997 58.891 ;
     RECT  3.528 58.801 3.69 58.919 ;
     RECT  199.404 58.885 201.186 58.925 ;
     RECT  188.604 58.891 188.997 58.928 ;
     RECT  3.528 58.919 3.546 58.955 ;
     RECT  199.515 58.925 201.186 58.999 ;
     RECT  169.815 58.891 170.442 59.021 ;
     RECT  177.915 58.891 178.434 59.021 ;
     RECT  190.404 58.891 190.422 59.021 ;
     RECT  199.515 58.999 201.258 59.071 ;
     RECT  197.892 58.987 197.91 59.099 ;
     RECT  26.715 46.061 26.997 59.161 ;
     RECT  199.515 59.071 201.33 59.189 ;
     RECT  26.496 59.161 26.997 59.213 ;
     RECT  28.044 58.699 28.062 59.261 ;
     RECT  207.072 58.157 207.897 59.729 ;
     RECT  21.315 54.869 21.942 59.851 ;
     RECT  21.315 59.851 22.41 59.999 ;
     RECT  24.015 40.019 24.297 60.151 ;
     RECT  23.94 60.151 24.297 60.317 ;
     RECT  210.315 58.657 211.158 60.421 ;
     RECT  212.184 57.931 213.297 60.421 ;
     RECT  210.315 60.421 211.41 60.539 ;
     RECT  212.184 60.421 213.534 60.539 ;
     RECT  212.184 60.539 212.202 60.647 ;
     RECT  213.015 60.539 213.534 60.655 ;
     RECT  213.015 60.655 213.786 60.701 ;
     RECT  210.315 60.539 211.266 60.749 ;
     RECT  212.076 60.655 212.094 60.809 ;
     RECT  2.415 58.685 2.697 60.817 ;
     RECT  2.415 60.817 2.862 60.961 ;
     RECT  1.728 60.961 2.862 61.037 ;
     RECT  2.415 61.037 2.862 61.195 ;
     RECT  7.74 57.569 9.666 61.195 ;
     RECT  2.415 61.195 3.006 61.231 ;
     RECT  7.56 61.195 9.666 61.259 ;
     RECT  5.115 58.379 5.397 61.321 ;
     RECT  5.115 61.321 5.706 61.501 ;
     RECT  4.572 61.501 5.706 61.655 ;
     RECT  2.415 61.231 3.222 61.691 ;
     RECT  4.572 61.655 5.397 61.727 ;
     RECT  207.216 59.729 207.897 63.005 ;
     RECT  209.34 58.963 209.358 63.391 ;
     RECT  210.315 60.749 211.158 63.391 ;
     RECT  214.236 63.451 214.254 63.581 ;
     RECT  2.415 61.691 2.697 63.589 ;
     RECT  2.415 63.589 3.006 63.625 ;
     RECT  5.115 61.727 5.397 63.661 ;
     RECT  0.216 63.547 0.234 63.689 ;
     RECT  5.115 63.661 5.958 63.779 ;
     RECT  209.34 63.391 211.59 63.779 ;
     RECT  209.34 63.779 211.446 63.815 ;
     RECT  209.34 63.815 211.158 63.821 ;
     RECT  2.415 63.625 3.114 64.193 ;
     RECT  209.34 63.821 209.358 65.245 ;
     RECT  200.736 59.189 201.258 65.273 ;
     RECT  2.415 64.193 2.697 65.911 ;
     RECT  0.54 66.085 0.558 66.125 ;
     RECT  207.615 63.005 207.897 66.181 ;
     RECT  2.304 65.911 2.697 66.217 ;
     RECT  209.34 65.245 209.394 66.217 ;
     RECT  2.304 66.217 3.294 66.253 ;
     RECT  4.104 66.217 4.122 66.253 ;
     RECT  214.236 66.187 214.254 66.281 ;
     RECT  207.615 66.181 208.134 66.331 ;
     RECT  208.908 66.217 209.394 66.331 ;
     RECT  2.304 66.253 4.23 66.361 ;
     RECT  5.115 63.779 5.397 66.361 ;
     RECT  213.015 60.701 213.297 66.361 ;
     RECT  207.615 66.331 209.394 66.389 ;
     RECT  213.015 66.361 213.534 66.509 ;
     RECT  208.908 66.389 209.394 66.515 ;
     RECT  2.304 66.361 5.397 66.785 ;
     RECT  7.74 61.259 9.666 66.793 ;
     RECT  10.515 58.559 11.178 66.793 ;
     RECT  6.84 66.721 6.858 66.821 ;
     RECT  4.5 66.785 5.397 66.901 ;
     RECT  2.304 66.785 3.726 67.055 ;
     RECT  3.42 67.055 3.726 67.091 ;
     RECT  4.5 66.901 5.922 67.091 ;
     RECT  2.304 67.055 2.697 67.127 ;
     RECT  7.74 66.793 11.178 67.289 ;
     RECT  12.132 58.559 13.497 67.405 ;
     RECT  99.615 46.031 100.314 67.559 ;
     RECT  99.615 67.559 100.062 67.595 ;
     RECT  199.515 59.189 199.797 67.675 ;
     RECT  200.916 65.273 201.258 67.675 ;
     RECT  199.515 67.675 201.258 67.829 ;
     RECT  83.376 52.439 83.697 67.837 ;
     RECT  7.74 67.289 9.666 68.207 ;
     RECT  12.132 67.405 13.698 68.369 ;
     RECT  15.372 58.559 16.197 68.369 ;
     RECT  83.376 67.837 83.754 68.369 ;
     RECT  12.132 68.369 13.59 68.405 ;
     RECT  41.868 53.249 81.774 68.441 ;
     RECT  12.132 68.405 13.497 68.477 ;
     RECT  7.74 68.207 9.522 68.485 ;
     RECT  6.84 68.485 9.522 68.521 ;
     RECT  6.48 68.521 9.522 68.611 ;
     RECT  4.5 67.091 5.397 68.711 ;
     RECT  4.572 68.711 5.397 68.755 ;
     RECT  6.264 68.611 9.522 68.755 ;
     RECT  2.415 67.127 2.697 68.791 ;
     RECT  3.564 68.719 3.582 68.791 ;
     RECT  207.615 66.389 207.897 68.791 ;
     RECT  0.54 68.587 0.558 68.819 ;
     RECT  209.052 66.515 209.394 68.819 ;
     RECT  213.015 66.509 213.297 68.881 ;
     RECT  2.415 68.791 3.582 68.909 ;
     RECT  207.468 68.791 207.897 68.917 ;
     RECT  210.315 63.821 211.158 68.923 ;
     RECT  2.415 68.909 3.114 68.945 ;
     RECT  4.572 68.755 9.522 68.945 ;
     RECT  206.532 68.917 206.55 68.953 ;
     RECT  207.324 68.917 207.897 68.953 ;
     RECT  206.532 68.953 207.897 68.957 ;
     RECT  212.796 68.881 213.297 68.957 ;
     RECT  209.376 68.819 209.394 68.971 ;
     RECT  210.315 68.923 211.41 68.971 ;
     RECT  4.572 68.945 6.282 68.981 ;
     RECT  212.976 68.957 213.297 68.981 ;
     RECT  214.236 68.923 214.254 68.981 ;
     RECT  206.676 68.957 207.897 69.005 ;
     RECT  209.376 68.971 211.41 69.179 ;
     RECT  4.572 68.981 5.742 69.215 ;
     RECT  7.128 68.945 9.522 69.215 ;
     RECT  207.324 69.005 207.897 69.215 ;
     RECT  210.315 69.179 211.41 69.215 ;
     RECT  5.115 69.215 5.742 69.359 ;
     RECT  6.876 70.681 6.894 70.879 ;
     RECT  7.632 69.215 9.522 70.879 ;
     RECT  6.876 70.879 9.522 70.915 ;
     RECT  2.415 68.945 2.697 70.951 ;
     RECT  2.415 70.951 3.258 71.069 ;
     RECT  6.48 70.915 9.522 71.069 ;
     RECT  41.868 68.441 81.216 71.105 ;
     RECT  2.415 71.069 2.754 71.141 ;
     RECT  5.115 69.359 5.397 71.221 ;
     RECT  0.54 71.083 0.558 71.249 ;
     RECT  6.876 71.069 9.522 71.249 ;
     RECT  5.115 71.221 5.67 71.339 ;
     RECT  213.015 68.981 213.297 71.455 ;
     RECT  210.315 69.215 211.158 71.491 ;
     RECT  212.616 71.455 213.297 71.609 ;
     RECT  210.315 71.491 211.518 71.617 ;
     RECT  210.315 71.617 212.166 71.741 ;
     RECT  214.344 71.659 214.362 71.753 ;
     RECT  211.896 71.741 212.166 71.789 ;
     RECT  212.148 71.789 212.166 71.915 ;
     RECT  7.416 71.249 9.522 73.381 ;
     RECT  10.515 67.289 11.178 73.381 ;
     RECT  2.415 71.141 2.697 73.471 ;
     RECT  202.215 2.413 202.497 73.507 ;
     RECT  2.268 73.471 2.697 73.615 ;
     RECT  7.416 73.381 11.178 73.643 ;
     RECT  2.268 73.615 2.79 73.651 ;
     RECT  2.268 73.651 2.862 73.661 ;
     RECT  7.416 73.643 10.797 73.741 ;
     RECT  3.6 73.651 3.618 73.769 ;
     RECT  2.415 73.661 2.862 73.805 ;
     RECT  6.12 73.885 6.138 73.921 ;
     RECT  6.912 73.741 10.797 73.921 ;
     RECT  6.12 73.921 10.797 74.039 ;
     RECT  88.815 43.037 89.514 74.039 ;
     RECT  6.912 74.039 10.797 74.111 ;
     RECT  210.315 71.741 210.69 74.461 ;
     RECT  214.344 74.425 214.362 74.477 ;
     RECT  202.104 73.507 202.497 74.489 ;
     RECT  209.376 69.179 209.394 74.551 ;
     RECT  210.315 74.461 211.014 74.551 ;
     RECT  213.015 71.609 213.297 74.551 ;
     RECT  209.376 74.551 211.014 74.579 ;
     RECT  213.015 74.551 213.354 74.669 ;
     RECT  211.716 74.635 211.734 74.683 ;
     RECT  209.376 74.579 210.69 74.717 ;
     RECT  211.716 74.683 211.842 74.849 ;
     RECT  211.716 74.849 211.734 74.885 ;
     RECT  5.115 71.339 5.397 75.811 ;
     RECT  6.12 74.039 6.138 75.811 ;
     RECT  2.415 73.805 2.697 76.045 ;
     RECT  5.115 75.811 6.138 76.081 ;
     RECT  2.304 76.045 2.697 76.199 ;
     RECT  5.115 76.081 6.714 76.199 ;
     RECT  0.216 76.081 0.234 76.205 ;
     RECT  7.74 74.111 10.797 76.243 ;
     RECT  2.415 76.199 2.697 76.315 ;
     RECT  5.115 76.199 6.174 76.343 ;
     RECT  2.415 76.315 2.898 76.351 ;
     RECT  5.115 76.343 5.922 76.363 ;
     RECT  101.556 46.535 101.574 76.469 ;
     RECT  2.415 76.351 3.114 76.549 ;
     RECT  4.464 76.363 5.922 76.585 ;
     RECT  2.415 76.549 3.186 76.621 ;
     RECT  4.32 76.585 5.922 76.739 ;
     RECT  2.415 76.621 3.438 76.811 ;
     RECT  4.32 76.739 4.338 76.847 ;
     RECT  102.315 46.829 102.597 76.855 ;
     RECT  102.315 76.855 102.726 76.891 ;
     RECT  3.42 76.811 3.438 76.919 ;
     RECT  101.34 76.585 101.358 76.925 ;
     RECT  102.315 76.891 102.906 76.928 ;
     RECT  99.615 67.595 99.897 76.939 ;
     RECT  188.715 58.928 188.997 76.981 ;
     RECT  186.015 33.917 186.297 76.987 ;
     RECT  196.815 57.569 197.097 76.987 ;
     RECT  188.715 76.981 189.09 77.021 ;
     RECT  186.015 76.987 186.39 77.117 ;
     RECT  196.815 76.987 197.19 77.117 ;
     RECT  99.504 76.939 99.897 77.125 ;
     RECT  200.916 67.829 201.258 77.161 ;
     RECT  209.376 74.717 209.394 77.161 ;
     RECT  213.015 74.669 213.297 77.161 ;
     RECT  14.976 77.227 14.994 77.275 ;
     RECT  196.815 77.117 197.097 77.275 ;
     RECT  14.652 77.275 14.994 77.279 ;
     RECT  209.052 77.161 209.394 77.279 ;
     RECT  14.652 77.279 14.67 77.315 ;
     RECT  209.052 77.279 209.07 77.395 ;
     RECT  207.615 69.215 207.897 77.419 ;
     RECT  214.344 77.179 214.362 77.423 ;
     RECT  196.524 77.275 197.097 77.431 ;
     RECT  207.615 77.419 208.134 77.431 ;
     RECT  208.872 77.395 209.07 77.431 ;
     RECT  99.396 77.125 99.897 77.501 ;
     RECT  210.315 74.717 210.69 77.521 ;
     RECT  207.615 77.431 209.07 77.549 ;
     RECT  207.615 77.549 208.278 77.597 ;
     RECT  210.315 77.521 210.834 77.597 ;
     RECT  199.515 67.829 199.797 77.899 ;
     RECT  200.844 77.161 201.258 77.899 ;
     RECT  190.404 76.987 190.422 77.933 ;
     RECT  198.36 77.803 198.378 77.933 ;
     RECT  199.515 77.899 201.258 77.936 ;
     RECT  7.632 76.243 10.797 77.971 ;
     RECT  103.32 77.935 103.338 77.971 ;
     RECT  103.32 77.971 103.482 77.981 ;
     RECT  199.515 77.936 199.797 78.331 ;
     RECT  199.404 78.331 199.797 78.368 ;
     RECT  5.115 76.739 5.922 78.511 ;
     RECT  5.115 78.511 6.354 78.571 ;
     RECT  4.752 78.571 6.354 78.601 ;
     RECT  4.752 78.601 6.498 78.629 ;
     RECT  2.415 76.811 2.697 78.667 ;
     RECT  2.415 78.667 2.754 78.745 ;
     RECT  2.415 78.745 2.97 78.781 ;
     RECT  7.524 77.971 10.797 78.871 ;
     RECT  2.415 78.781 3.15 78.979 ;
     RECT  2.415 78.979 3.294 79.051 ;
     RECT  2.415 79.051 3.402 79.169 ;
     RECT  5.115 78.629 6.498 79.169 ;
     RECT  6.228 79.169 6.498 79.177 ;
     RECT  7.38 78.871 10.797 79.177 ;
     RECT  2.415 79.169 3.294 79.205 ;
     RECT  6.228 79.177 10.797 79.205 ;
     RECT  2.415 79.205 3.15 79.241 ;
     RECT  207.615 77.597 207.897 79.789 ;
     RECT  209.052 77.549 209.07 79.817 ;
     RECT  171.684 79.753 171.702 79.861 ;
     RECT  212.292 77.161 213.297 79.915 ;
     RECT  212.292 79.915 213.678 80.051 ;
     RECT  103.464 77.981 103.482 80.095 ;
     RECT  207.468 79.789 207.897 80.095 ;
     RECT  210.315 77.597 210.597 80.107 ;
     RECT  103.464 80.095 103.77 80.131 ;
     RECT  212.292 80.051 213.297 80.131 ;
     RECT  206.532 80.095 207.897 80.141 ;
     RECT  209.664 80.107 210.597 80.155 ;
     RECT  212.22 80.131 213.297 80.189 ;
     RECT  209.664 80.155 210.978 80.221 ;
     RECT  207.36 80.141 207.897 80.249 ;
     RECT  209.664 80.221 211.086 80.249 ;
     RECT  200.844 77.936 201.258 80.329 ;
     RECT  210.315 80.249 211.086 80.357 ;
     RECT  103.464 80.131 103.95 80.381 ;
     RECT  199.515 78.368 199.797 80.491 ;
     RECT  199.476 80.491 199.797 80.621 ;
     RECT  6.948 79.205 10.797 80.923 ;
     RECT  2.415 79.241 2.697 81.031 ;
     RECT  2.304 81.031 2.697 81.203 ;
     RECT  2.415 81.203 2.697 81.211 ;
     RECT  0.216 81.163 0.234 81.239 ;
     RECT  196.416 77.431 197.097 81.239 ;
     RECT  6.48 80.923 10.797 81.337 ;
     RECT  42.444 71.105 81.216 81.337 ;
     RECT  6.48 81.337 10.818 81.509 ;
     RECT  204.915 33.989 205.197 81.547 ;
     RECT  2.415 81.211 2.862 81.571 ;
     RECT  204.915 81.547 205.506 81.599 ;
     RECT  105.015 47.219 105.297 81.715 ;
     RECT  5.115 79.169 5.397 81.751 ;
     RECT  6.48 81.509 10.797 81.751 ;
     RECT  104.292 81.715 105.297 81.773 ;
     RECT  2.415 81.571 2.934 81.779 ;
     RECT  4.968 81.751 10.797 81.821 ;
     RECT  2.415 81.779 2.898 81.869 ;
     RECT  4.968 81.821 6.066 81.869 ;
     RECT  200.736 80.329 201.258 81.869 ;
     RECT  199.515 80.621 199.797 81.877 ;
     RECT  2.415 81.869 2.79 81.905 ;
     RECT  199.44 81.877 199.797 81.917 ;
     RECT  5.115 81.869 6.066 81.941 ;
     RECT  5.115 81.941 5.994 82.049 ;
     RECT  6.84 81.821 10.797 82.049 ;
     RECT  171 79.861 171.702 82.139 ;
     RECT  210.315 80.357 210.597 82.147 ;
     RECT  21.315 59.999 21.942 82.651 ;
     RECT  26.715 59.213 26.997 82.651 ;
     RECT  210.315 82.147 211.014 82.651 ;
     RECT  21.204 82.651 21.942 82.688 ;
     RECT  14.832 82.651 14.85 82.781 ;
     RECT  26.676 82.651 26.997 82.781 ;
     RECT  212.292 80.189 213.297 82.795 ;
     RECT  214.344 82.699 214.362 82.823 ;
     RECT  7.488 82.049 10.797 82.831 ;
     RECT  210.315 82.651 211.374 82.831 ;
     RECT  212.184 82.795 213.297 82.831 ;
     RECT  6.408 82.747 6.426 82.859 ;
     RECT  210.315 82.831 213.297 82.949 ;
     RECT  210.315 82.949 211.518 83.021 ;
     RECT  2.415 81.905 2.697 83.461 ;
     RECT  7.452 82.831 10.797 83.461 ;
     RECT  209.304 82.921 209.322 83.497 ;
     RECT  103.464 80.381 103.482 83.605 ;
     RECT  104.436 81.773 105.297 83.605 ;
     RECT  199.515 81.917 199.797 83.605 ;
     RECT  2.415 83.461 3.33 83.641 ;
     RECT  5.115 82.049 5.397 83.641 ;
     RECT  103.464 83.605 105.297 83.645 ;
     RECT  199.116 83.605 199.797 83.645 ;
     RECT  0.216 83.707 0.234 83.759 ;
     RECT  2.415 83.641 3.402 83.759 ;
     RECT  2.415 83.759 3.33 83.767 ;
     RECT  200.736 81.869 201.186 83.767 ;
     RECT  2.412 83.767 3.33 83.795 ;
     RECT  7.38 83.461 10.797 83.911 ;
     RECT  2.412 83.795 2.697 83.939 ;
     RECT  5.115 83.641 6.174 84.181 ;
     RECT  5.115 84.181 6.498 84.221 ;
     RECT  5.115 84.221 6.282 84.299 ;
     RECT  5.115 84.299 6.138 84.335 ;
     RECT  7.236 83.911 10.797 84.613 ;
     RECT  12.24 68.477 13.497 84.641 ;
     RECT  209.304 83.497 209.394 85.351 ;
     RECT  210.315 83.021 211.014 85.351 ;
     RECT  209.304 85.351 211.014 85.379 ;
     RECT  214.344 85.423 214.362 85.469 ;
     RECT  211.428 85.435 211.446 85.483 ;
     RECT  212.292 82.949 213.297 85.483 ;
     RECT  209.304 85.379 210.69 85.649 ;
     RECT  211.428 85.483 213.297 85.649 ;
     RECT  211.428 85.649 211.446 85.685 ;
     RECT  7.2 84.613 10.797 85.765 ;
     RECT  7.056 85.765 10.797 85.801 ;
     RECT  209.304 85.649 210.654 86.195 ;
     RECT  6.948 85.801 10.797 86.225 ;
     RECT  5.115 84.335 5.598 86.341 ;
     RECT  0.216 86.251 0.234 86.369 ;
     RECT  2.415 83.939 2.697 86.431 ;
     RECT  3.42 86.341 4.194 86.431 ;
     RECT  5.115 86.341 5.706 86.431 ;
     RECT  2.415 86.431 5.706 86.459 ;
     RECT  2.415 86.459 3.294 86.611 ;
     RECT  2.412 86.611 3.294 86.621 ;
     RECT  2.412 86.621 3.222 86.765 ;
     RECT  4.032 86.459 5.706 86.861 ;
     RECT  4.788 86.861 5.706 86.881 ;
     RECT  2.415 86.765 3.222 86.909 ;
     RECT  4.032 86.861 4.05 86.999 ;
     RECT  7.092 86.225 10.797 86.999 ;
     RECT  4.788 86.881 5.922 87.035 ;
     RECT  4.788 87.035 5.706 87.179 ;
     RECT  128.52 74.047 128.538 87.547 ;
     RECT  98.604 87.547 98.622 87.647 ;
     RECT  96.915 40.865 97.197 87.691 ;
     RECT  207.615 80.249 207.897 88.123 ;
     RECT  210.315 86.195 210.654 88.171 ;
     RECT  214.344 88.159 214.362 88.205 ;
     RECT  210.315 88.171 211.338 88.219 ;
     RECT  212.292 85.649 213.297 88.219 ;
     RECT  183.315 2.413 183.597 88.231 ;
     RECT  207.615 88.123 208.278 88.349 ;
     RECT  210.315 88.219 213.297 88.349 ;
     RECT  209.304 86.195 209.394 88.357 ;
     RECT  7.164 86.999 10.797 88.363 ;
     RECT  5.115 87.179 5.706 88.501 ;
     RECT  6.48 88.363 10.797 88.501 ;
     RECT  183.315 88.231 183.978 88.501 ;
     RECT  211.716 88.349 213.297 88.619 ;
     RECT  2.415 86.909 2.697 88.627 ;
     RECT  96.915 87.691 97.542 88.735 ;
     RECT  212.004 88.619 213.297 88.763 ;
     RECT  2.415 88.627 2.934 88.771 ;
     RECT  5.115 88.501 10.797 88.771 ;
     RECT  0.216 88.747 0.234 88.799 ;
     RECT  2.415 88.771 3.042 88.861 ;
     RECT  5.004 88.771 10.797 88.861 ;
     RECT  4.86 88.861 10.797 88.925 ;
     RECT  2.415 88.861 3.582 89.041 ;
     RECT  191.415 42.653 191.697 89.041 ;
     RECT  5.115 88.925 10.797 89.159 ;
     RECT  2.415 89.041 4.014 89.195 ;
     RECT  5.115 89.159 6.354 89.195 ;
     RECT  207.615 88.349 207.897 89.203 ;
     RECT  208.656 88.357 209.394 89.203 ;
     RECT  3.564 89.195 4.014 89.231 ;
     RECT  3.996 89.231 4.014 89.339 ;
     RECT  210.315 88.349 210.597 89.743 ;
     RECT  6.336 89.195 6.354 90.043 ;
     RECT  7.164 89.159 10.797 90.043 ;
     RECT  128.52 87.547 128.61 90.247 ;
     RECT  5.115 89.195 5.397 90.391 ;
     RECT  99.615 77.501 99.897 90.391 ;
     RECT  207.615 89.203 209.394 90.481 ;
     RECT  5.004 90.391 5.397 90.517 ;
     RECT  4.896 90.517 5.397 90.605 ;
     RECT  6.336 90.043 10.797 90.619 ;
     RECT  207.504 90.481 209.394 90.689 ;
     RECT  5.115 90.605 5.397 90.859 ;
     RECT  6.336 90.619 10.854 90.859 ;
     RECT  207.504 90.689 208.062 90.895 ;
     RECT  212.292 88.763 213.297 90.895 ;
     RECT  207.396 90.895 208.062 90.907 ;
     RECT  209.376 90.689 209.394 90.907 ;
     RECT  210.315 89.743 210.978 90.907 ;
     RECT  206.856 90.907 208.062 90.931 ;
     RECT  212.292 90.895 213.786 90.941 ;
     RECT  209.376 90.907 210.978 90.955 ;
     RECT  5.115 90.859 10.854 90.959 ;
     RECT  2.415 89.195 2.697 91.021 ;
     RECT  206.712 90.931 208.062 91.049 ;
     RECT  209.376 90.955 211.23 91.049 ;
     RECT  206.712 91.049 206.73 91.085 ;
     RECT  210.315 91.049 211.23 91.085 ;
     RECT  96.588 88.735 97.542 91.165 ;
     RECT  6.336 90.959 10.797 91.181 ;
     RECT  7.164 91.181 10.797 91.193 ;
     RECT  2.304 91.021 2.697 91.201 ;
     RECT  2.268 91.201 2.697 91.277 ;
     RECT  2.304 91.277 2.697 91.291 ;
     RECT  2.304 91.291 2.898 91.319 ;
     RECT  200.736 83.767 201.474 91.319 ;
     RECT  202.215 74.489 202.497 91.327 ;
     RECT  5.115 90.959 5.598 91.427 ;
     RECT  2.415 91.319 2.898 91.463 ;
     RECT  3.78 91.201 3.798 91.471 ;
     RECT  200.844 91.319 201.474 91.499 ;
     RECT  202.215 91.327 202.554 91.499 ;
     RECT  3.708 91.471 3.798 91.589 ;
     RECT  3.78 91.589 3.798 91.733 ;
     RECT  2.415 91.463 2.697 93.361 ;
     RECT  5.115 91.427 5.397 93.361 ;
     RECT  6.336 91.181 6.354 93.361 ;
     RECT  7.164 91.193 8.097 93.361 ;
     RECT  8.928 91.193 10.797 93.361 ;
     RECT  2.415 93.361 3.402 93.403 ;
     RECT  2.415 93.403 3.834 93.445 ;
     RECT  2.415 93.445 4.23 93.479 ;
     RECT  4.212 93.479 4.23 93.485 ;
     RECT  83.376 68.369 83.697 93.631 ;
     RECT  210.315 91.085 211.014 93.631 ;
     RECT  212.292 90.941 213.297 93.631 ;
     RECT  212.292 93.631 213.534 93.691 ;
     RECT  5.115 93.361 10.797 93.749 ;
     RECT  210.315 93.631 211.518 93.749 ;
     RECT  212.292 93.691 214.254 93.749 ;
     RECT  212.292 93.749 213.297 93.757 ;
     RECT  6.228 93.749 10.797 93.821 ;
     RECT  214.236 93.749 214.254 93.821 ;
     RECT  0.216 93.787 0.234 93.929 ;
     RECT  207.615 91.049 208.062 93.979 ;
     RECT  207.615 93.979 208.134 93.991 ;
     RECT  207.18 93.991 208.134 94.019 ;
     RECT  2.415 93.479 3.186 94.055 ;
     RECT  6.336 93.821 10.797 94.055 ;
     RECT  212.148 93.757 213.297 94.055 ;
     RECT  207.18 94.019 208.062 94.061 ;
     RECT  207.615 94.061 208.062 94.873 ;
     RECT  200.916 91.499 201.474 94.901 ;
     RECT  113.115 47.693 113.397 94.945 ;
     RECT  113.115 94.945 113.562 94.981 ;
     RECT  128.52 90.247 128.682 95.107 ;
     RECT  5.115 93.749 5.397 95.179 ;
     RECT  206.928 94.873 208.062 95.179 ;
     RECT  209.376 91.049 209.394 95.179 ;
     RECT  4.608 95.179 5.397 95.369 ;
     RECT  200.952 94.901 201.474 95.477 ;
     RECT  6.336 94.055 8.097 95.639 ;
     RECT  206.928 95.179 209.394 95.639 ;
     RECT  209.052 95.639 209.394 95.645 ;
     RECT  4.68 95.369 5.397 95.755 ;
     RECT  4.68 95.755 5.778 96.215 ;
     RECT  2.415 94.055 2.697 96.295 ;
     RECT  209.376 95.645 209.394 96.331 ;
     RECT  210.315 93.749 211.014 96.331 ;
     RECT  212.292 94.055 213.297 96.331 ;
     RECT  2.268 96.295 2.697 96.365 ;
     RECT  4.68 96.215 5.397 96.475 ;
     RECT  214.344 96.427 214.362 96.521 ;
     RECT  4.068 96.475 5.397 96.601 ;
     RECT  3.456 96.601 5.397 96.605 ;
     RECT  209.376 96.331 213.297 96.605 ;
     RECT  4.68 96.605 5.397 96.629 ;
     RECT  3.456 96.605 3.906 96.719 ;
     RECT  4.968 96.629 5.397 96.719 ;
     RECT  210.315 96.605 213.297 96.719 ;
     RECT  2.304 96.365 2.697 96.755 ;
     RECT  3.816 96.719 3.906 96.791 ;
     RECT  3.816 96.791 3.834 96.899 ;
     RECT  200.952 95.477 201.186 96.989 ;
     RECT  200.952 96.989 201.15 96.997 ;
     RECT  202.215 91.499 202.497 96.997 ;
     RECT  206.928 95.639 208.062 96.997 ;
     RECT  200.88 96.997 201.15 97.069 ;
     RECT  200.772 97.069 201.15 97.097 ;
     RECT  202.176 96.997 202.497 97.169 ;
     RECT  200.772 97.097 201.006 97.259 ;
     RECT  83.34 93.631 83.697 97.771 ;
     RECT  83.34 97.771 83.718 97.951 ;
     RECT  210.315 96.719 211.014 98.311 ;
     RECT  8.928 94.055 10.797 98.491 ;
     RECT  169.815 59.021 170.097 98.491 ;
     RECT  200.844 97.259 200.898 98.519 ;
     RECT  6.804 95.639 8.097 98.581 ;
     RECT  41.868 81.337 81.216 98.581 ;
     RECT  127.944 95.107 128.682 98.581 ;
     RECT  129.6 53.285 167.616 98.581 ;
     RECT  169.812 98.491 170.097 98.609 ;
     RECT  6.732 98.581 8.097 98.617 ;
     RECT  8.82 98.491 10.797 98.617 ;
     RECT  5.04 96.719 5.397 98.725 ;
     RECT  4.68 98.725 5.418 98.761 ;
     RECT  87.84 95.251 87.858 98.761 ;
     RECT  169.815 98.609 170.097 98.761 ;
     RECT  170.82 97.141 170.838 98.761 ;
     RECT  6.732 98.617 10.797 98.789 ;
     RECT  4.284 98.761 5.562 98.959 ;
     RECT  6.732 98.789 8.154 98.959 ;
     RECT  3.492 98.851 3.51 98.971 ;
     RECT  4.284 98.959 8.154 98.971 ;
     RECT  2.415 96.755 2.697 99.031 ;
     RECT  3.492 98.971 8.154 99.031 ;
     RECT  212.292 96.719 213.297 99.031 ;
     RECT  0.216 98.827 0.234 99.059 ;
     RECT  206.928 96.997 208.17 99.121 ;
     RECT  2.412 99.031 8.154 99.149 ;
     RECT  14.76 99.031 14.994 99.149 ;
     RECT  209.376 96.605 209.394 99.149 ;
     RECT  212.292 99.031 213.606 99.149 ;
     RECT  206.928 99.121 208.278 99.157 ;
     RECT  210.315 98.311 211.23 99.163 ;
     RECT  212.292 99.149 213.297 99.163 ;
     RECT  2.415 99.149 3.51 99.185 ;
     RECT  4.392 99.149 8.154 99.185 ;
     RECT  214.884 99.157 214.902 99.197 ;
     RECT  6.336 99.185 8.154 99.293 ;
     RECT  2.415 99.185 2.97 99.419 ;
     RECT  4.392 99.185 5.397 99.419 ;
     RECT  6.336 99.293 8.097 99.419 ;
     RECT  2.415 99.419 2.862 99.455 ;
     RECT  210.315 99.163 213.297 99.455 ;
     RECT  206.928 99.157 209.178 99.463 ;
     RECT  206.352 99.463 209.178 99.527 ;
     RECT  169.815 98.761 170.838 99.571 ;
     RECT  210.315 99.455 211.23 99.571 ;
     RECT  200.844 98.519 200.862 99.599 ;
     RECT  206.352 99.527 208.674 99.599 ;
     RECT  4.752 99.419 5.397 99.629 ;
     RECT  169.812 99.571 170.838 99.689 ;
     RECT  88.815 74.039 89.097 99.733 ;
     RECT  88.815 99.733 89.766 99.841 ;
     RECT  6.804 99.419 8.097 100.381 ;
     RECT  8.928 98.789 10.797 100.741 ;
     RECT  6.516 100.381 8.097 100.747 ;
     RECT  5.115 99.629 5.397 100.891 ;
     RECT  6.408 100.747 8.097 100.891 ;
     RECT  2.415 99.455 2.697 101.011 ;
     RECT  5.115 100.891 8.097 101.039 ;
     RECT  5.115 101.039 5.922 101.111 ;
     RECT  5.115 101.111 5.454 101.309 ;
     RECT  0.216 101.281 0.234 101.357 ;
     RECT  2.415 101.011 2.79 101.461 ;
     RECT  2.415 101.461 3.258 101.579 ;
     RECT  2.415 101.579 3.114 101.615 ;
     RECT  206.928 99.599 208.674 101.759 ;
     RECT  206.928 101.759 208.17 101.857 ;
     RECT  206.532 101.857 208.17 101.933 ;
     RECT  214.308 101.893 214.326 101.933 ;
     RECT  209.916 99.571 211.23 102.091 ;
     RECT  206.676 101.933 208.17 102.173 ;
     RECT  209.772 102.091 211.23 102.199 ;
     RECT  209.592 102.199 211.23 102.299 ;
     RECT  6.804 101.039 8.097 103.195 ;
     RECT  6.804 103.195 8.154 103.279 ;
     RECT  8.928 100.741 11.106 103.279 ;
     RECT  6.804 103.279 11.106 103.541 ;
     RECT  2.415 101.615 2.697 103.621 ;
     RECT  6.804 103.541 9.306 103.847 ;
     RECT  2.415 103.621 3.006 103.867 ;
     RECT  8.892 103.847 9.306 103.883 ;
     RECT  6.804 103.847 8.154 103.901 ;
     RECT  2.268 103.867 3.006 103.919 ;
     RECT  8.928 103.883 9.306 104.045 ;
     RECT  2.415 103.919 3.006 104.089 ;
     RECT  2.415 104.089 3.33 104.161 ;
     RECT  2.415 104.161 3.474 104.279 ;
     RECT  2.415 104.279 3.33 104.315 ;
     RECT  209.916 102.299 211.23 104.701 ;
     RECT  209.916 104.701 211.518 104.819 ;
     RECT  214.344 104.683 214.362 104.891 ;
     RECT  212.292 99.455 213.297 104.935 ;
     RECT  209.916 104.819 211.338 104.957 ;
     RECT  212.184 104.935 213.297 105.089 ;
     RECT  14.76 99.149 14.778 106.015 ;
     RECT  104.328 83.645 105.297 106.027 ;
     RECT  188.715 77.021 188.997 106.027 ;
     RECT  191.415 89.041 192.042 106.027 ;
     RECT  199.515 83.645 199.797 106.027 ;
     RECT  41.868 98.581 81.774 106.11 ;
     RECT  127.944 98.581 167.616 106.11 ;
     RECT  95.724 91.165 97.542 106.169 ;
     RECT  110.415 48.389 110.697 106.171 ;
     RECT  177.915 59.021 178.197 106.171 ;
     RECT  8.928 104.045 8.946 106.205 ;
     RECT  103.464 83.645 103.482 106.205 ;
     RECT  104.328 106.027 105.354 106.205 ;
     RECT  113.115 94.981 113.814 106.205 ;
     RECT  127.944 106.11 129.114 106.205 ;
     RECT  169.815 99.689 170.838 106.205 ;
     RECT  83.34 97.951 83.826 106.213 ;
     RECT  14.688 106.015 14.778 106.219 ;
     RECT  26.715 82.781 26.997 106.219 ;
     RECT  82.728 106.213 83.826 106.219 ;
     RECT  86.115 52.709 86.397 106.219 ;
     RECT  188.604 106.027 188.997 106.219 ;
     RECT  14.688 106.219 14.85 106.241 ;
     RECT  81.756 106.11 81.774 106.241 ;
     RECT  87.408 98.761 87.858 106.241 ;
     RECT  88.776 99.841 89.766 106.241 ;
     RECT  10.188 103.541 11.106 106.253 ;
     RECT  104.436 106.205 105.354 106.253 ;
     RECT  190.116 106.027 190.134 106.267 ;
     RECT  88.776 106.241 89.097 106.277 ;
     RECT  128.52 106.205 129.114 106.277 ;
     RECT  169.815 106.205 170.586 106.277 ;
     RECT  2.415 104.315 2.697 106.285 ;
     RECT  21.315 82.688 21.942 106.312 ;
     RECT  188.604 106.219 189.27 106.312 ;
     RECT  41.868 106.11 42.714 106.313 ;
     RECT  87.84 106.241 87.858 106.313 ;
     RECT  106.668 106.171 106.686 106.315 ;
     RECT  114.588 106.171 114.606 106.315 ;
     RECT  190.116 106.267 190.422 106.315 ;
     RECT  110.34 106.171 110.697 106.321 ;
     RECT  14.832 106.241 14.85 106.349 ;
     RECT  22.824 106.219 22.842 106.349 ;
     RECT  30.672 106.219 30.798 106.349 ;
     RECT  82.656 106.219 83.826 106.349 ;
     RECT  86.115 106.219 86.67 106.349 ;
     RECT  98.604 106.171 98.622 106.349 ;
     RECT  188.568 106.312 189.27 106.349 ;
     RECT  113.115 106.205 113.562 106.397 ;
     RECT  10.515 106.253 11.106 106.411 ;
     RECT  107.715 57.299 107.997 106.411 ;
     RECT  186.015 77.117 186.297 106.411 ;
     RECT  191.415 106.027 192.546 106.411 ;
     RECT  196.815 81.239 197.097 106.411 ;
     RECT  2.304 106.285 2.697 106.439 ;
     RECT  83.34 106.349 83.826 106.439 ;
     RECT  188.604 106.349 189.27 106.439 ;
     RECT  190.116 106.315 190.566 106.439 ;
     RECT  191.415 106.411 192.87 106.439 ;
     RECT  199.224 106.027 199.797 106.439 ;
     RECT  0.216 106.321 0.234 106.445 ;
     RECT  21.204 106.312 21.942 106.448 ;
     RECT  196.704 106.411 197.097 106.448 ;
     RECT  199.404 106.439 199.797 106.448 ;
     RECT  186.015 106.411 186.426 106.459 ;
     RECT  192.852 106.439 192.87 106.459 ;
     RECT  106.596 106.315 106.686 106.493 ;
     RECT  110.34 106.321 110.826 106.493 ;
     RECT  114.408 106.315 114.606 106.493 ;
     RECT  190.44 106.439 190.566 106.493 ;
     RECT  192.852 106.459 192.978 106.493 ;
     RECT  10.515 106.411 11.502 106.507 ;
     RECT  12.816 84.641 13.497 106.507 ;
     RECT  110.34 106.493 110.754 106.511 ;
     RECT  2.415 106.439 2.697 106.519 ;
     RECT  10.515 106.507 13.497 106.541 ;
     RECT  26.676 106.219 26.997 106.541 ;
     RECT  30.78 106.349 30.798 106.541 ;
     RECT  106.668 106.493 106.686 106.541 ;
     RECT  107.604 106.411 107.997 106.541 ;
     RECT  110.376 106.511 110.754 106.541 ;
     RECT  114.588 106.493 114.606 106.541 ;
     RECT  122.544 106.171 122.562 106.541 ;
     RECT  169.815 106.277 170.442 106.541 ;
     RECT  177.915 106.171 178.434 106.541 ;
     RECT  190.44 106.493 190.458 106.541 ;
     RECT  12.168 106.541 13.497 106.547 ;
     RECT  206.928 102.173 208.17 106.555 ;
     RECT  186.015 106.459 186.498 106.589 ;
     RECT  192.96 106.493 192.978 106.589 ;
     RECT  206.928 106.555 208.422 106.589 ;
     RECT  2.415 106.519 3.042 106.591 ;
     RECT  194.115 2.413 194.397 106.603 ;
     RECT  95.976 106.169 97.542 106.619 ;
     RECT  191.415 106.439 192.042 106.619 ;
     RECT  128.52 106.277 128.682 106.664 ;
     RECT  2.415 106.591 3.222 106.699 ;
     RECT  96.84 106.619 97.542 106.709 ;
     RECT  128.592 106.664 128.682 106.709 ;
     RECT  191.415 106.619 191.898 106.709 ;
     RECT  4.104 106.591 4.23 106.745 ;
     RECT  6.804 103.901 8.097 106.745 ;
     RECT  83.34 106.439 83.697 106.745 ;
     RECT  128.592 106.709 128.646 106.745 ;
     RECT  183.315 88.501 184.05 106.745 ;
     RECT  4.212 106.745 4.23 106.781 ;
     RECT  41.868 106.313 42.642 106.781 ;
     RECT  128.628 106.745 128.646 106.781 ;
     RECT  171.684 82.139 171.702 106.781 ;
     RECT  42.012 106.781 42.642 106.817 ;
     RECT  99.615 90.391 99.99 106.817 ;
     RECT  42.012 106.817 42.57 106.853 ;
     RECT  95.976 106.619 95.994 106.853 ;
     RECT  2.415 106.699 3.294 106.861 ;
     RECT  5.115 101.309 5.397 106.861 ;
     RECT  6.84 106.745 8.097 106.889 ;
     RECT  42.444 106.853 42.57 106.889 ;
     RECT  96.915 106.709 97.542 106.889 ;
     RECT  193.5 106.603 194.397 106.979 ;
     RECT  40.215 48.389 40.497 106.987 ;
     RECT  2.415 106.861 3.438 107.015 ;
     RECT  193.824 106.979 194.397 107.021 ;
     RECT  40.215 106.987 41.022 107.024 ;
     RECT  3.42 107.015 3.438 107.051 ;
     RECT  4.536 106.861 5.397 107.123 ;
     RECT  38.772 106.789 38.79 107.123 ;
     RECT  42.444 106.889 42.498 107.123 ;
     RECT  102.315 76.928 102.597 107.179 ;
     RECT  104.436 106.253 105.297 107.179 ;
     RECT  186.015 106.589 186.297 107.179 ;
     RECT  187.56 107.179 187.578 107.323 ;
     RECT  102.315 107.179 102.906 107.371 ;
     RECT  209.916 104.957 211.23 107.401 ;
     RECT  102.315 107.371 103.23 107.519 ;
     RECT  104.076 107.179 105.297 107.519 ;
     RECT  185.94 107.179 186.297 107.519 ;
     RECT  187.56 107.323 187.902 107.519 ;
     RECT  104.4 107.519 105.297 107.549 ;
     RECT  214.308 107.419 214.326 107.591 ;
     RECT  209.88 107.401 211.23 107.671 ;
     RECT  212.292 105.089 213.297 107.671 ;
     RECT  209.736 107.671 211.23 107.741 ;
     RECT  212.004 107.671 213.297 107.825 ;
     RECT  33.48 46.499 33.498 108.059 ;
     RECT  42.444 107.123 42.462 108.253 ;
     RECT  45.807 108.253 45.897 108.523 ;
     RECT  48.507 108.253 48.597 108.523 ;
     RECT  51.207 108.253 51.297 108.523 ;
     RECT  53.907 108.253 53.997 108.523 ;
     RECT  56.607 108.253 56.697 108.523 ;
     RECT  59.307 108.253 59.397 108.523 ;
     RECT  62.007 108.253 62.097 108.523 ;
     RECT  64.707 108.253 64.797 108.523 ;
     RECT  67.407 108.253 67.497 108.523 ;
     RECT  70.107 108.253 70.197 108.523 ;
     RECT  72.807 108.253 72.897 108.523 ;
     RECT  75.507 108.253 75.597 108.523 ;
     RECT  78.207 108.253 78.297 108.523 ;
     RECT  80.907 108.253 80.997 108.523 ;
     RECT  129.507 108.253 129.597 108.523 ;
     RECT  132.207 108.253 132.297 108.523 ;
     RECT  134.907 108.253 134.997 108.523 ;
     RECT  137.607 108.253 137.697 108.523 ;
     RECT  140.307 108.253 140.397 108.523 ;
     RECT  143.007 108.253 143.097 108.523 ;
     RECT  145.707 108.253 145.797 108.523 ;
     RECT  148.407 108.253 148.497 108.523 ;
     RECT  151.107 108.253 151.197 108.523 ;
     RECT  153.807 108.253 153.897 108.523 ;
     RECT  156.507 108.253 156.597 108.523 ;
     RECT  159.207 108.253 159.297 108.523 ;
     RECT  161.907 108.253 161.997 108.523 ;
     RECT  164.607 108.253 164.697 108.523 ;
     RECT  167.307 108.253 167.397 108.523 ;
     RECT  2.415 107.015 2.697 108.571 ;
     RECT  4.356 108.031 4.374 108.715 ;
     RECT  5.115 107.123 5.397 108.715 ;
     RECT  4.356 108.715 5.397 108.751 ;
     RECT  4.032 108.751 5.397 108.869 ;
     RECT  4.212 108.869 5.397 108.985 ;
     RECT  2.415 108.571 3.078 109.021 ;
     RECT  4.212 108.985 5.49 109.139 ;
     RECT  0.54 108.907 0.558 109.247 ;
     RECT  2.415 109.021 3.258 109.283 ;
     RECT  5.076 109.139 5.397 109.283 ;
     RECT  4.212 109.139 4.23 109.325 ;
     RECT  6.84 106.889 6.858 109.417 ;
     RECT  7.815 106.889 8.097 109.417 ;
     RECT  6.84 109.417 8.097 109.445 ;
     RECT  207.432 106.589 208.422 109.795 ;
     RECT  207.432 109.795 209.07 110.101 ;
     RECT  212.292 107.825 213.297 110.155 ;
     RECT  207.432 110.101 209.142 110.327 ;
     RECT  212.292 110.155 213.786 110.363 ;
     RECT  212.292 110.363 213.297 110.371 ;
     RECT  209.916 107.741 211.23 110.395 ;
     RECT  207.432 110.327 209.07 110.429 ;
     RECT  212.22 110.371 213.297 110.429 ;
     RECT  208.944 110.429 209.07 110.489 ;
     RECT  209.916 110.395 211.338 110.525 ;
     RECT  2.415 109.283 2.697 111.271 ;
     RECT  2.304 111.271 2.697 111.443 ;
     RECT  0.216 111.403 0.234 111.479 ;
     RECT  2.415 111.443 2.697 111.685 ;
     RECT  7.416 109.445 8.097 111.685 ;
     RECT  7.272 111.685 8.097 111.721 ;
     RECT  6.624 111.721 8.097 111.739 ;
     RECT  42.444 108.253 43.197 111.749 ;
     RECT  5.115 109.283 5.397 111.811 ;
     RECT  6.444 111.739 8.097 111.811 ;
     RECT  2.415 111.685 2.862 111.839 ;
     RECT  5.115 111.811 8.097 111.839 ;
     RECT  5.115 111.839 6.462 111.911 ;
     RECT  5.115 111.911 5.778 111.919 ;
     RECT  7.272 111.839 8.097 111.983 ;
     RECT  4.86 111.919 5.778 111.991 ;
     RECT  4.716 111.991 5.778 112.109 ;
     RECT  4.716 112.109 5.397 112.145 ;
     RECT  7.416 111.983 8.097 112.289 ;
     RECT  207.432 110.429 208.17 112.919 ;
     RECT  214.308 112.939 214.326 112.991 ;
     RECT  206.532 112.939 206.55 113.029 ;
     RECT  206.532 113.029 206.694 113.035 ;
     RECT  207.432 112.919 207.897 113.035 ;
     RECT  206.532 113.035 207.897 113.063 ;
     RECT  206.676 113.063 207.897 113.069 ;
     RECT  209.916 110.525 211.23 113.179 ;
     RECT  207.324 113.069 207.897 113.189 ;
     RECT  209.052 110.489 209.07 113.189 ;
     RECT  209.916 113.179 211.41 113.225 ;
     RECT  2.415 111.839 2.697 113.845 ;
     RECT  0.216 113.881 0.234 113.981 ;
     RECT  7.668 112.289 8.097 113.995 ;
     RECT  2.304 113.845 2.697 113.999 ;
     RECT  7.668 113.995 8.19 114.043 ;
     RECT  10.515 106.541 10.797 114.043 ;
     RECT  2.415 113.999 2.697 114.115 ;
     RECT  2.415 114.115 3.186 114.151 ;
     RECT  7.668 114.043 8.262 114.151 ;
     RECT  10.515 114.043 10.854 114.179 ;
     RECT  21.315 106.448 21.942 114.179 ;
     RECT  2.415 114.151 3.366 114.341 ;
     RECT  7.668 114.151 8.946 114.341 ;
     RECT  5.115 112.145 5.397 114.349 ;
     RECT  5.115 114.349 5.958 114.539 ;
     RECT  5.115 114.539 5.814 114.575 ;
     RECT  9.36 114.421 9.378 114.575 ;
     RECT  209.916 113.225 211.23 115.147 ;
     RECT  209.916 115.147 211.338 115.501 ;
     RECT  209.916 115.501 211.518 115.691 ;
     RECT  212.292 110.429 213.297 115.699 ;
     RECT  214.344 115.663 214.362 115.709 ;
     RECT  212.04 115.699 213.297 115.961 ;
     RECT  2.415 114.341 2.697 116.275 ;
     RECT  2.304 116.275 2.697 116.311 ;
     RECT  2.268 116.311 2.697 116.525 ;
     RECT  2.412 116.525 2.697 116.779 ;
     RECT  3.888 116.779 3.906 116.815 ;
     RECT  2.412 116.779 2.934 116.875 ;
     RECT  3.888 116.815 4.086 116.875 ;
     RECT  2.412 116.875 4.086 117.005 ;
     RECT  3.888 117.005 4.086 117.013 ;
     RECT  3.888 117.013 4.23 117.121 ;
     RECT  5.115 114.575 5.397 117.121 ;
     RECT  3.888 117.121 5.397 117.239 ;
     RECT  4.212 117.239 5.397 117.383 ;
     RECT  214.308 118.399 214.326 118.445 ;
     RECT  213.015 115.961 213.297 118.471 ;
     RECT  4.536 117.383 5.397 118.555 ;
     RECT  209.916 115.691 211.23 118.555 ;
     RECT  2.415 117.005 2.697 118.561 ;
     RECT  212.904 118.471 213.297 118.589 ;
     RECT  209.736 118.555 211.23 118.595 ;
     RECT  2.412 118.561 2.697 118.733 ;
     RECT  209.88 118.595 211.23 118.859 ;
     RECT  209.88 118.859 210.597 118.931 ;
     RECT  0.216 118.741 0.234 119.021 ;
     RECT  4.392 118.555 5.397 119.128 ;
     RECT  4.248 119.128 5.397 119.129 ;
     RECT  212.04 115.961 212.058 119.129 ;
     RECT  4.248 119.129 4.266 119.165 ;
     RECT  7.668 114.341 8.097 119.173 ;
     RECT  5.04 119.129 5.397 119.209 ;
     RECT  3.492 118.741 3.51 119.281 ;
     RECT  5.04 119.209 5.67 119.281 ;
     RECT  3.42 119.281 4.014 119.399 ;
     RECT  3.42 119.399 3.438 119.435 ;
     RECT  5.04 119.281 5.706 119.435 ;
     RECT  5.115 119.435 5.706 119.543 ;
     RECT  2.415 118.733 2.697 121.135 ;
     RECT  2.304 121.135 2.697 121.171 ;
     RECT  207.432 113.189 207.897 121.261 ;
     RECT  213.015 118.589 213.297 121.261 ;
     RECT  209.916 118.931 210.597 121.289 ;
     RECT  207.432 121.261 208.278 121.297 ;
     RECT  209.052 121.171 209.07 121.297 ;
     RECT  214.236 121.147 214.254 121.361 ;
     RECT  212.652 121.261 213.297 121.421 ;
     RECT  1.728 121.171 2.697 121.517 ;
     RECT  210.315 121.289 210.597 121.531 ;
     RECT  207.432 121.297 209.07 121.595 ;
     RECT  211.644 121.387 211.662 121.595 ;
     RECT  207.432 121.595 208.278 121.613 ;
     RECT  210.315 121.531 210.654 121.613 ;
     RECT  6.624 121.435 6.642 121.711 ;
     RECT  7.416 119.173 8.097 121.711 ;
     RECT  2.415 121.517 2.697 121.801 ;
     RECT  6.624 121.711 8.097 121.829 ;
     RECT  7.308 121.829 8.097 121.865 ;
     RECT  5.115 119.543 5.397 121.945 ;
     RECT  6.264 121.909 6.462 121.945 ;
     RECT  5.004 121.945 6.462 121.997 ;
     RECT  5.004 121.997 6.282 122.099 ;
     RECT  2.415 121.801 2.862 122.171 ;
     RECT  5.115 122.099 5.706 122.243 ;
     RECT  207.432 121.613 207.897 122.539 ;
     RECT  7.416 121.865 8.097 122.635 ;
     RECT  207.324 122.539 207.897 122.639 ;
     RECT  7.272 122.635 8.097 122.909 ;
     RECT  207.432 122.639 207.897 123.179 ;
     RECT  7.416 122.909 8.097 123.799 ;
     RECT  7.416 123.799 8.55 123.835 ;
     RECT  7.416 123.835 8.73 123.871 ;
     RECT  209.052 121.595 209.07 123.899 ;
     RECT  2.415 122.171 2.697 123.961 ;
     RECT  6.516 123.799 6.534 123.989 ;
     RECT  7.416 123.871 9.27 123.989 ;
     RECT  207.468 123.179 207.897 123.997 ;
     RECT  9.252 123.989 9.27 124.025 ;
     RECT  206.532 123.979 206.55 124.025 ;
     RECT  207.324 123.997 207.897 124.033 ;
     RECT  214.236 123.931 214.254 124.061 ;
     RECT  210.315 121.613 210.597 124.075 ;
     RECT  7.815 123.989 8.154 124.097 ;
     RECT  12.816 106.547 13.497 124.097 ;
     RECT  206.676 124.033 207.897 124.109 ;
     RECT  2.376 123.961 2.697 124.141 ;
     RECT  3.42 123.871 3.438 124.141 ;
     RECT  213.015 121.421 213.297 124.141 ;
     RECT  212.364 124.141 213.297 124.253 ;
     RECT  2.376 124.141 3.582 124.259 ;
     RECT  209.772 124.075 211.194 124.259 ;
     RECT  2.376 124.259 3.438 124.295 ;
     RECT  207.324 124.109 207.897 124.295 ;
     RECT  209.88 124.259 211.086 124.295 ;
     RECT  209.88 124.295 210.597 124.331 ;
     RECT  2.376 124.295 2.934 124.403 ;
     RECT  2.376 124.403 2.697 124.565 ;
     RECT  2.415 124.565 2.697 127.187 ;
     RECT  5.115 122.243 5.397 127.187 ;
     RECT  7.815 124.097 8.097 127.187 ;
     RECT  10.515 114.179 10.797 127.187 ;
     RECT  13.215 124.097 13.497 127.187 ;
     RECT  15.915 68.369 16.197 127.187 ;
     RECT  18.615 41.117 18.897 127.187 ;
     RECT  21.315 114.179 21.597 127.187 ;
     RECT  24.015 60.317 24.297 127.187 ;
     RECT  26.715 106.541 26.997 127.187 ;
     RECT  29.415 46.877 29.697 127.187 ;
     RECT  32.115 46.409 32.397 127.187 ;
     RECT  34.815 47.075 35.097 127.187 ;
     RECT  37.515 48.425 37.797 127.187 ;
     RECT  40.215 107.024 40.497 127.187 ;
     RECT  42.915 111.749 43.197 127.187 ;
     RECT  45.615 108.523 45.897 127.187 ;
     RECT  48.315 108.523 48.597 127.187 ;
     RECT  51.015 108.523 51.297 127.187 ;
     RECT  53.715 108.523 53.997 127.187 ;
     RECT  56.415 108.523 56.697 127.187 ;
     RECT  59.115 108.523 59.397 127.187 ;
     RECT  61.815 108.523 62.097 127.187 ;
     RECT  64.515 108.523 64.797 127.187 ;
     RECT  67.215 108.523 67.497 127.187 ;
     RECT  69.915 108.523 70.197 127.187 ;
     RECT  72.615 108.523 72.897 127.187 ;
     RECT  75.315 108.523 75.597 127.187 ;
     RECT  78.015 108.523 78.297 127.187 ;
     RECT  80.715 108.523 80.997 127.187 ;
     RECT  83.415 106.745 83.697 127.187 ;
     RECT  86.115 106.349 86.397 127.187 ;
     RECT  88.815 106.277 89.097 127.187 ;
     RECT  91.515 38.435 91.797 127.187 ;
     RECT  94.215 42.179 94.497 127.187 ;
     RECT  96.915 106.889 97.197 127.187 ;
     RECT  99.615 106.817 99.897 127.187 ;
     RECT  102.315 107.519 102.597 127.187 ;
     RECT  105.015 107.549 105.297 127.187 ;
     RECT  107.715 106.541 107.997 127.187 ;
     RECT  110.415 106.541 110.697 127.187 ;
     RECT  113.115 106.397 113.397 127.187 ;
     RECT  115.815 48.227 116.097 127.187 ;
     RECT  118.515 47.885 118.797 127.187 ;
     RECT  121.215 58.415 121.497 127.187 ;
     RECT  123.915 57.029 124.197 127.187 ;
     RECT  126.615 57.173 126.897 127.187 ;
     RECT  129.315 108.523 129.597 127.187 ;
     RECT  132.015 108.523 132.297 127.187 ;
     RECT  134.715 108.523 134.997 127.187 ;
     RECT  137.415 108.523 137.697 127.187 ;
     RECT  140.115 108.523 140.397 127.187 ;
     RECT  142.815 108.523 143.097 127.187 ;
     RECT  145.515 108.523 145.797 127.187 ;
     RECT  148.215 108.523 148.497 127.187 ;
     RECT  150.915 108.523 151.197 127.187 ;
     RECT  153.615 108.523 153.897 127.187 ;
     RECT  156.315 108.523 156.597 127.187 ;
     RECT  159.015 108.523 159.297 127.187 ;
     RECT  161.715 108.523 161.997 127.187 ;
     RECT  164.415 108.523 164.697 127.187 ;
     RECT  167.115 108.523 167.397 127.187 ;
     RECT  169.815 106.541 170.097 127.187 ;
     RECT  172.515 56.759 172.797 127.187 ;
     RECT  175.215 2.413 175.497 127.187 ;
     RECT  177.915 106.541 178.197 127.187 ;
     RECT  180.615 2.413 180.897 127.187 ;
     RECT  183.315 106.745 183.597 127.187 ;
     RECT  186.015 107.519 186.297 127.187 ;
     RECT  188.715 106.439 188.997 127.187 ;
     RECT  191.415 106.709 191.697 127.187 ;
     RECT  194.115 107.021 194.397 127.187 ;
     RECT  196.815 106.448 197.097 127.187 ;
     RECT  199.515 106.448 199.797 127.187 ;
     RECT  202.215 97.169 202.497 127.187 ;
     RECT  204.915 81.599 205.197 127.187 ;
     RECT  207.615 124.295 207.897 127.187 ;
     RECT  210.315 124.331 210.597 127.187 ;
     RECT  213.015 124.253 213.297 127.187 ;
     RECT  2.415 127.187 2.505 127.457 ;
     RECT  5.115 127.187 5.205 127.457 ;
     RECT  7.815 127.187 7.905 127.457 ;
     RECT  10.515 127.187 10.605 127.457 ;
     RECT  13.215 127.187 13.305 127.457 ;
     RECT  15.915 127.187 16.005 127.457 ;
     RECT  18.615 127.187 18.705 127.457 ;
     RECT  21.315 127.187 21.405 127.457 ;
     RECT  24.015 127.187 24.105 127.457 ;
     RECT  26.715 127.187 26.805 127.457 ;
     RECT  29.415 127.187 29.505 127.457 ;
     RECT  32.115 127.187 32.205 127.457 ;
     RECT  34.815 127.187 34.905 127.457 ;
     RECT  37.515 127.187 37.605 127.457 ;
     RECT  40.215 127.187 40.305 127.457 ;
     RECT  42.915 127.187 43.005 127.457 ;
     RECT  45.615 127.187 45.705 127.457 ;
     RECT  48.315 127.187 48.405 127.457 ;
     RECT  51.015 127.187 51.105 127.457 ;
     RECT  53.715 127.187 53.805 127.457 ;
     RECT  56.415 127.187 56.505 127.457 ;
     RECT  59.115 127.187 59.205 127.457 ;
     RECT  61.815 127.187 61.905 127.457 ;
     RECT  64.515 127.187 64.605 127.457 ;
     RECT  67.215 127.187 67.305 127.457 ;
     RECT  69.915 127.187 70.005 127.457 ;
     RECT  72.615 127.187 72.705 127.457 ;
     RECT  75.315 127.187 75.405 127.457 ;
     RECT  78.015 127.187 78.105 127.457 ;
     RECT  80.715 127.187 80.805 127.457 ;
     RECT  83.415 127.187 83.505 127.457 ;
     RECT  86.115 127.187 86.205 127.457 ;
     RECT  88.815 127.187 88.905 127.457 ;
     RECT  91.515 127.187 91.605 127.457 ;
     RECT  94.215 127.187 94.305 127.457 ;
     RECT  96.915 127.187 97.005 127.457 ;
     RECT  99.615 127.187 99.705 127.457 ;
     RECT  102.315 127.187 102.405 127.457 ;
     RECT  105.015 127.187 105.105 127.457 ;
     RECT  107.715 127.187 107.805 127.457 ;
     RECT  110.415 127.187 110.505 127.457 ;
     RECT  113.115 127.187 113.205 127.457 ;
     RECT  115.815 127.187 115.905 127.457 ;
     RECT  118.515 127.187 118.605 127.457 ;
     RECT  121.215 127.187 121.305 127.457 ;
     RECT  123.915 127.187 124.005 127.457 ;
     RECT  126.615 127.187 126.705 127.457 ;
     RECT  129.315 127.187 129.405 127.457 ;
     RECT  132.015 127.187 132.105 127.457 ;
     RECT  134.715 127.187 134.805 127.457 ;
     RECT  137.415 127.187 137.505 127.457 ;
     RECT  140.115 127.187 140.205 127.457 ;
     RECT  142.815 127.187 142.905 127.457 ;
     RECT  145.515 127.187 145.605 127.457 ;
     RECT  148.215 127.187 148.305 127.457 ;
     RECT  150.915 127.187 151.005 127.457 ;
     RECT  153.615 127.187 153.705 127.457 ;
     RECT  156.315 127.187 156.405 127.457 ;
     RECT  159.015 127.187 159.105 127.457 ;
     RECT  161.715 127.187 161.805 127.457 ;
     RECT  164.415 127.187 164.505 127.457 ;
     RECT  167.115 127.187 167.205 127.457 ;
     RECT  169.815 127.187 169.905 127.457 ;
     RECT  172.515 127.187 172.605 127.457 ;
     RECT  175.215 127.187 175.305 127.457 ;
     RECT  177.915 127.187 178.005 127.457 ;
     RECT  180.615 127.187 180.705 127.457 ;
     RECT  183.315 127.187 183.405 127.457 ;
     RECT  186.015 127.187 186.105 127.457 ;
     RECT  188.715 127.187 188.805 127.457 ;
     RECT  191.415 127.187 191.505 127.457 ;
     RECT  194.115 127.187 194.205 127.457 ;
     RECT  196.815 127.187 196.905 127.457 ;
     RECT  199.515 127.187 199.605 127.457 ;
     RECT  202.215 127.187 202.305 127.457 ;
     RECT  204.915 127.187 205.005 127.457 ;
     RECT  207.615 127.187 207.705 127.457 ;
     RECT  210.315 127.187 210.405 127.457 ;
     RECT  213.015 127.187 213.105 127.457 ;
    LAYER M4 ;
     RECT  0.156 30.768 0.181 30.792 ;
     RECT  0.181 30.768 0.227 30.888 ;
     RECT  0.156 5.616 0.245 5.64 ;
     RECT  0.156 10.656 0.245 10.68 ;
     RECT  0.156 15.696 0.245 15.72 ;
     RECT  0.156 18.192 0.245 18.216 ;
     RECT  0.156 20.688 0.245 20.712 ;
     RECT  0.156 23.232 0.245 23.256 ;
     RECT  0.156 28.272 0.245 28.296 ;
     RECT  0.156 33.312 0.245 33.336 ;
     RECT  0.156 50.928 0.245 50.952 ;
     RECT  0.156 53.472 0.245 53.496 ;
     RECT  0.156 63.552 0.245 63.576 ;
     RECT  0.156 76.176 0.245 76.2 ;
     RECT  0.156 81.168 0.245 81.192 ;
     RECT  0.156 83.712 0.245 83.736 ;
     RECT  0.156 86.256 0.245 86.28 ;
     RECT  0.156 88.752 0.245 88.776 ;
     RECT  0.156 93.792 0.245 93.816 ;
     RECT  0.156 98.832 0.245 98.856 ;
     RECT  0.156 101.328 0.245 101.352 ;
     RECT  0.156 106.416 0.245 106.44 ;
     RECT  0.156 111.408 0.245 111.432 ;
     RECT  0.156 113.952 0.245 113.976 ;
     RECT  0.156 118.992 0.245 119.016 ;
     RECT  0.156 25.776 0.569 25.8 ;
     RECT  0.156 40.848 0.569 40.872 ;
     RECT  0.156 45.888 0.569 45.912 ;
     RECT  0.156 66.096 0.569 66.12 ;
     RECT  0.156 68.592 0.569 68.616 ;
     RECT  0.156 71.088 0.569 71.112 ;
     RECT  0.156 108.912 0.569 108.936 ;
     RECT  0.156 8.112 2.408 8.136 ;
     RECT  0.156 13.152 2.408 13.176 ;
     RECT  0.227 30.864 2.408 30.888 ;
     RECT  0.156 35.856 2.408 35.88 ;
     RECT  0.156 38.352 2.408 38.376 ;
     RECT  0.156 43.392 2.408 43.416 ;
     RECT  0.156 48.432 2.408 48.456 ;
     RECT  0.156 56.016 2.408 56.04 ;
     RECT  0.156 58.512 2.408 58.536 ;
     RECT  0.156 61.008 2.408 61.032 ;
     RECT  0.156 73.632 2.408 73.656 ;
     RECT  0.156 78.672 2.408 78.696 ;
     RECT  0.156 91.248 2.408 91.272 ;
     RECT  0.156 96.336 2.408 96.36 ;
     RECT  0.156 103.872 2.408 103.896 ;
     RECT  0.156 116.496 2.408 116.52 ;
     RECT  0.156 121.488 2.408 121.512 ;
     RECT  0.156 124.032 2.408 124.056 ;
     RECT  2.408 2.148 2.512 127.452 ;
     RECT  2.512 2.418 2.704 127.182 ;
     RECT  2.704 78.672 2.765 78.696 ;
     RECT  2.704 5.904 3.491 6.264 ;
     RECT  2.704 66.672 3.557 66.792 ;
     RECT  3.557 66.768 3.635 66.792 ;
     RECT  2.704 35.376 3.733 36.024 ;
     RECT  3.692 46.224 3.733 46.248 ;
     RECT  3.733 35.328 3.779 36.024 ;
     RECT  3.733 45.504 3.779 46.248 ;
     RECT  3.692 48.432 3.779 48.456 ;
     RECT  2.704 55.872 3.779 55.896 ;
     RECT  3.697 26.256 3.781 26.664 ;
     RECT  3.733 47.28 3.82 47.304 ;
     RECT  3.491 6.24 3.827 6.264 ;
     RECT  3.733 16.08 3.827 16.104 ;
     RECT  3.781 26.256 3.827 26.28 ;
     RECT  2.704 116.88 3.971 116.952 ;
     RECT  3.805 93.408 4.117 93.432 ;
     RECT  2.704 86.592 4.201 86.616 ;
     RECT  3.779 35.328 4.237 35.736 ;
     RECT  4.124 98.976 4.381 99 ;
     RECT  4.237 119.136 4.381 119.16 ;
     RECT  4.237 34.368 4.549 35.736 ;
     RECT  4.201 86.544 4.597 86.616 ;
     RECT  4.381 98.976 4.7 99.24 ;
     RECT  4.597 95.184 4.885 95.208 ;
     RECT  4.057 96.48 4.885 96.6 ;
     RECT  4.837 17.664 4.981 17.688 ;
     RECT  4.885 90.576 4.981 90.6 ;
     RECT  4.837 8.352 5.108 8.376 ;
     RECT  4.981 17.664 5.108 18.168 ;
     RECT  2.704 22.464 5.108 22.488 ;
     RECT  4.849 28.944 5.108 28.968 ;
     RECT  4.549 34.128 5.108 35.736 ;
     RECT  4.813 38.208 5.108 38.76 ;
     RECT  3.779 45.504 5.108 46.152 ;
     RECT  4.837 48.432 5.108 48.456 ;
     RECT  4.981 58.128 5.108 58.152 ;
     RECT  4.453 76.368 5.108 76.392 ;
     RECT  4.7 78.576 5.108 78.6 ;
     RECT  4.597 86.544 5.108 86.856 ;
     RECT  4.849 88.896 5.108 88.92 ;
     RECT  4.981 90.384 5.108 90.6 ;
     RECT  4.117 93.408 5.108 93.48 ;
     RECT  4.885 95.184 5.108 96.6 ;
     RECT  4.7 98.976 5.108 99.624 ;
     RECT  2.704 106.704 5.108 106.728 ;
     RECT  4.165 109.296 5.108 109.32 ;
     RECT  3.971 116.88 5.108 116.904 ;
     RECT  4.381 118.56 5.108 119.16 ;
     RECT  4.741 122.64 5.108 122.664 ;
     RECT  5.108 2.148 5.212 127.452 ;
     RECT  5.212 2.418 5.404 127.182 ;
     RECT  5.404 28.944 5.555 28.968 ;
     RECT  5.404 55.872 5.573 55.896 ;
     RECT  5.404 34.224 5.651 35.736 ;
     RECT  5.404 37.968 5.651 37.992 ;
     RECT  5.404 66.768 5.651 66.792 ;
     RECT  5.651 34.368 5.699 34.824 ;
     RECT  5.404 15.984 5.725 16.536 ;
     RECT  5.404 40.224 6.293 40.248 ;
     RECT  5.404 100.896 6.38 100.92 ;
     RECT  5.725 15.984 6.401 16.008 ;
     RECT  5.404 32.352 6.421 32.376 ;
     RECT  6.421 80.928 6.428 80.952 ;
     RECT  6.397 82.752 6.428 82.776 ;
     RECT  5.404 83.856 6.428 83.88 ;
     RECT  5.404 122.64 6.433 122.664 ;
     RECT  6.38 100.752 6.437 100.92 ;
     RECT  6.38 37.584 6.467 37.608 ;
     RECT  6.38 68.784 6.467 68.808 ;
     RECT  5.404 79.008 6.467 79.032 ;
     RECT  6.437 100.752 6.467 100.776 ;
     RECT  5.404 88.752 6.469 88.824 ;
     RECT  5.404 90.864 6.469 90.888 ;
     RECT  6.428 80.928 6.509 82.776 ;
     RECT  6.509 81.792 6.515 82.776 ;
     RECT  6.428 83.856 6.515 84.216 ;
     RECT  6.433 111.744 6.517 111.768 ;
     RECT  6.469 88.368 6.528 88.824 ;
     RECT  6.528 88.368 6.553 88.392 ;
     RECT  5.404 41.424 6.6 42.168 ;
     RECT  6.433 121.968 6.613 122.664 ;
     RECT  6.469 90.864 6.649 91.176 ;
     RECT  6.649 90.048 6.689 91.176 ;
     RECT  6.613 121.44 6.697 122.664 ;
     RECT  6.397 50.736 6.707 50.76 ;
     RECT  6.62 99.168 6.707 99.192 ;
     RECT  5.404 45.504 6.721 46.056 ;
     RECT  6.661 106.416 6.829 106.44 ;
     RECT  6.421 31.632 6.853 32.376 ;
     RECT  6.937 86.064 7.093 86.088 ;
     RECT  6.421 38.64 7.153 38.664 ;
     RECT  6.937 29.472 7.292 29.496 ;
     RECT  7.285 73.776 7.297 73.8 ;
     RECT  7.093 86.016 7.333 86.088 ;
     RECT  6.515 82.752 7.429 82.776 ;
     RECT  6.697 121.968 7.429 122.664 ;
     RECT  7.292 11.232 7.477 11.256 ;
     RECT  7.196 20.784 7.585 20.808 ;
     RECT  5.404 22.464 7.585 22.488 ;
     RECT  7.429 82.752 7.585 82.872 ;
     RECT  6.515 83.856 7.585 83.976 ;
     RECT  7.292 29.472 7.621 30.216 ;
     RECT  6.853 31.632 7.621 32.472 ;
     RECT  6.6 41.424 7.669 42.792 ;
     RECT  7.297 73.776 7.669 74.088 ;
     RECT  7.477 11.232 7.808 11.976 ;
     RECT  7.669 13.68 7.808 13.704 ;
     RECT  6.685 18.096 7.808 18.12 ;
     RECT  7.585 20.784 7.808 22.488 ;
     RECT  7.621 28.8 7.808 32.472 ;
     RECT  5.699 34.368 7.808 34.392 ;
     RECT  7.669 36.528 7.808 36.552 ;
     RECT  7.153 38.64 7.808 39.576 ;
     RECT  7.669 40.8 7.808 42.792 ;
     RECT  6.721 45.408 7.808 46.056 ;
     RECT  6.613 55.392 7.808 55.416 ;
     RECT  7.549 61.2 7.808 61.224 ;
     RECT  6.793 68.88 7.808 68.904 ;
     RECT  6.721 70.944 7.808 70.968 ;
     RECT  7.669 73.776 7.808 74.616 ;
     RECT  7.189 79.2 7.808 79.224 ;
     RECT  7.693 81.456 7.808 81.48 ;
     RECT  7.585 82.752 7.808 83.976 ;
     RECT  7.333 85.824 7.808 86.088 ;
     RECT  6.689 90.048 7.808 90.984 ;
     RECT  6.469 93.84 7.808 93.864 ;
     RECT  5.404 95.184 7.808 95.208 ;
     RECT  6.829 106.416 7.808 106.536 ;
     RECT  7.237 107.52 7.808 107.544 ;
     RECT  7.429 121.968 7.808 123.768 ;
     RECT  7.808 2.148 7.912 127.452 ;
     RECT  7.912 2.418 8.104 127.182 ;
     RECT  8.104 28.8 8.165 28.824 ;
     RECT  8.104 82.752 8.201 83.784 ;
     RECT  8.104 38.016 8.243 43.656 ;
     RECT  8.104 45.264 8.243 46.728 ;
     RECT  8.104 60.672 8.243 61.224 ;
     RECT  8.201 82.752 8.243 83.64 ;
     RECT  8.104 93.504 8.243 93.576 ;
     RECT  8.104 103.2 8.243 103.896 ;
     RECT  8.104 53.04 8.245 53.784 ;
     RECT  8.104 114 8.245 114.024 ;
     RECT  8.243 45.504 8.273 46.728 ;
     RECT  8.104 57.6 8.273 57.624 ;
     RECT  8.104 63.408 8.284 63.432 ;
     RECT  8.104 85.344 8.345 85.368 ;
     RECT  8.104 22.464 8.387 24.216 ;
     RECT  8.104 32.256 8.387 33.672 ;
     RECT  8.104 76.32 8.387 76.344 ;
     RECT  8.243 93.552 8.417 93.576 ;
     RECT  8.104 73.632 8.597 74.616 ;
     RECT  8.243 38.016 8.723 42.792 ;
     RECT  8.723 38.016 8.741 42.168 ;
     RECT  8.104 34.848 8.885 35.736 ;
     RECT  8.104 68.976 9.073 69 ;
     RECT  8.245 53.04 9.107 53.064 ;
     RECT  8.104 50.976 9.245 51 ;
     RECT  8.597 73.632 9.245 73.656 ;
     RECT  9.133 16.08 9.251 16.104 ;
     RECT  8.741 38.016 9.313 42.024 ;
     RECT  9.313 37.92 9.452 42.024 ;
     RECT  9.452 36.96 9.539 42.024 ;
     RECT  8.885 35.28 9.644 35.736 ;
     RECT  8.387 32.256 9.745 32.28 ;
     RECT  9.539 37.872 9.853 42.024 ;
     RECT  8.104 106.512 10.177 107.544 ;
     RECT  9.644 35.28 10.393 35.88 ;
     RECT  9.313 33.84 10.501 33.864 ;
     RECT  10.393 34.944 10.501 35.88 ;
     RECT  9.853 37.872 10.501 42.6 ;
     RECT  8.387 22.464 10.508 22.488 ;
     RECT  9.745 31.392 10.508 32.28 ;
     RECT  10.501 33.84 10.508 35.88 ;
     RECT  10.501 37.68 10.508 42.6 ;
     RECT  8.273 45.504 10.508 46.056 ;
     RECT  8.104 55.392 10.508 55.416 ;
     RECT  8.243 82.752 10.508 82.776 ;
     RECT  8.104 90.864 10.508 90.888 ;
     RECT  9.781 93.456 10.508 93.48 ;
     RECT  10.177 106.224 10.508 107.544 ;
     RECT  10.508 2.148 10.612 127.452 ;
     RECT  10.612 2.418 10.804 127.182 ;
     RECT  10.804 90.624 10.865 90.792 ;
     RECT  10.804 36.912 10.901 39.048 ;
     RECT  10.804 33.84 11.405 35.736 ;
     RECT  11.405 34.944 11.549 35.736 ;
     RECT  10.901 37.92 11.869 39.048 ;
     RECT  10.804 40.128 11.869 42.6 ;
     RECT  10.901 36.912 12.085 36.936 ;
     RECT  11.869 50.88 12.125 50.904 ;
     RECT  12.085 36.864 12.805 36.936 ;
     RECT  11.869 37.92 12.805 42.6 ;
     RECT  11.549 35.712 12.949 35.736 ;
     RECT  12.805 36.864 12.949 42.6 ;
     RECT  12.949 35.712 13.045 42.6 ;
     RECT  10.804 22.464 13.208 22.488 ;
     RECT  11.405 33.84 13.208 33.864 ;
     RECT  13.045 35.328 13.208 42.6 ;
     RECT  10.804 45.408 13.208 45.96 ;
     RECT  10.804 55.392 13.208 55.416 ;
     RECT  10.804 82.656 13.208 82.68 ;
     RECT  10.865 90.624 13.208 90.648 ;
     RECT  10.804 106.32 13.208 107.544 ;
     RECT  13.208 2.148 13.312 127.452 ;
     RECT  13.312 2.418 13.504 127.182 ;
     RECT  13.504 34.992 13.745 37.896 ;
     RECT  13.745 37.584 13.817 37.896 ;
     RECT  13.817 37.584 14.821 37.752 ;
     RECT  13.504 45.408 14.821 45.96 ;
     RECT  13.504 55.392 14.821 55.416 ;
     RECT  13.504 82.656 14.821 82.68 ;
     RECT  13.504 106.32 14.821 107.544 ;
     RECT  14.821 45.408 14.861 46.056 ;
     RECT  14.821 55.392 14.861 55.512 ;
     RECT  14.821 82.656 14.861 82.776 ;
     RECT  14.641 77.28 14.924 77.304 ;
     RECT  13.745 34.992 15.145 36.36 ;
     RECT  15.145 34.992 15.217 36.504 ;
     RECT  14.821 37.536 15.217 38.28 ;
     RECT  15.217 34.992 15.469 38.28 ;
     RECT  13.504 22.464 15.908 22.488 ;
     RECT  13.504 33.84 15.908 33.864 ;
     RECT  15.469 34.992 15.908 38.76 ;
     RECT  13.504 41.424 15.908 42.6 ;
     RECT  14.861 45.504 15.908 46.056 ;
     RECT  14.861 55.488 15.908 55.512 ;
     RECT  14.965 59.184 15.908 59.208 ;
     RECT  14.924 77.232 15.908 77.304 ;
     RECT  14.861 82.752 15.908 82.776 ;
     RECT  13.504 90.624 15.908 90.648 ;
     RECT  14.821 106.224 15.908 107.544 ;
     RECT  15.908 2.148 16.012 127.452 ;
     RECT  16.012 2.418 16.204 127.182 ;
     RECT  16.204 33.648 16.553 38.76 ;
     RECT  16.553 33.648 16.697 38.232 ;
     RECT  16.697 33.648 17.273 37.896 ;
     RECT  17.273 33.648 18.277 33.864 ;
     RECT  16.204 41.424 18.277 42.6 ;
     RECT  16.204 22.464 18.608 22.488 ;
     RECT  18.277 33.12 18.608 33.864 ;
     RECT  17.273 34.896 18.608 37.896 ;
     RECT  18.277 41.088 18.608 42.6 ;
     RECT  16.204 45.504 18.608 46.056 ;
     RECT  16.204 55.488 18.608 55.512 ;
     RECT  16.204 59.184 18.608 59.208 ;
     RECT  16.204 77.28 18.608 77.304 ;
     RECT  16.204 82.752 18.608 82.776 ;
     RECT  16.204 106.224 18.608 107.544 ;
     RECT  18.608 2.148 18.712 127.452 ;
     RECT  18.712 2.418 18.904 127.182 ;
     RECT  18.904 33.12 19.721 38.712 ;
     RECT  18.904 59.184 19.957 59.208 ;
     RECT  19.721 33.12 20.003 35.448 ;
     RECT  18.904 45.408 20.009 46.776 ;
     RECT  19.721 37.056 20.189 38.712 ;
     RECT  20.003 33.12 20.473 35.4 ;
     RECT  20.473 32.88 21.265 35.4 ;
     RECT  18.904 22.464 21.308 22.488 ;
     RECT  21.265 32.208 21.308 35.4 ;
     RECT  20.189 37.056 21.308 38.184 ;
     RECT  18.904 41.088 21.308 42.6 ;
     RECT  20.009 45.408 21.308 45.96 ;
     RECT  18.904 55.488 21.308 55.512 ;
     RECT  19.957 59.184 21.308 59.88 ;
     RECT  18.904 77.28 21.308 77.304 ;
     RECT  18.904 82.656 21.308 82.68 ;
     RECT  18.904 106.32 21.308 107.544 ;
     RECT  21.308 2.148 21.412 127.452 ;
     RECT  21.412 2.418 21.604 127.182 ;
     RECT  21.604 55.392 21.701 55.512 ;
     RECT  21.604 59.184 22.421 59.88 ;
     RECT  21.604 32.208 22.781 38.184 ;
     RECT  21.701 55.392 22.813 55.416 ;
     RECT  21.604 106.32 22.813 107.544 ;
     RECT  21.604 41.088 22.853 42.6 ;
     RECT  21.604 45.408 22.853 45.96 ;
     RECT  22.813 55.392 22.853 55.512 ;
     RECT  22.781 32.208 22.997 36.12 ;
     RECT  22.781 37.152 23.461 38.184 ;
     RECT  22.997 33.024 23.893 36.12 ;
     RECT  23.461 37.152 23.893 38.808 ;
     RECT  22.853 45.504 23.893 45.96 ;
     RECT  21.604 82.656 23.893 82.68 ;
     RECT  21.604 22.464 24.008 22.488 ;
     RECT  23.893 33.024 24.008 38.808 ;
     RECT  22.853 41.136 24.008 42.6 ;
     RECT  23.893 45.504 24.008 46.056 ;
     RECT  22.853 55.488 24.008 55.512 ;
     RECT  22.421 59.184 24.008 59.208 ;
     RECT  23.929 60.288 24.008 60.312 ;
     RECT  21.604 77.28 24.008 77.304 ;
     RECT  23.893 82.656 24.008 82.776 ;
     RECT  22.813 106.224 24.008 107.544 ;
     RECT  24.008 2.148 24.112 127.452 ;
     RECT  24.112 2.418 24.304 127.182 ;
     RECT  24.304 60.288 24.419 60.312 ;
     RECT  24.304 77.28 24.419 77.304 ;
     RECT  24.304 33.072 24.515 36.552 ;
     RECT  24.304 38.784 24.545 39.912 ;
     RECT  24.515 33.072 24.797 36.12 ;
     RECT  24.797 33.6 24.941 36.12 ;
     RECT  24.545 39.312 25.549 39.912 ;
     RECT  24.941 33.84 25.868 36.12 ;
     RECT  25.549 39.312 25.909 40.056 ;
     RECT  26.269 32.304 26.437 32.328 ;
     RECT  26.437 32.304 26.665 32.376 ;
     RECT  25.801 3.744 26.708 3.768 ;
     RECT  24.304 22.464 26.708 22.488 ;
     RECT  26.665 32.304 26.708 32.616 ;
     RECT  25.868 33.84 26.708 36.504 ;
     RECT  24.304 37.584 26.708 37.656 ;
     RECT  25.909 39.216 26.708 40.056 ;
     RECT  24.304 41.136 26.708 42.6 ;
     RECT  24.304 45.504 26.708 46.056 ;
     RECT  24.304 55.488 26.708 55.512 ;
     RECT  24.304 59.184 26.708 59.208 ;
     RECT  24.304 82.752 26.708 82.776 ;
     RECT  24.304 106.224 26.708 107.544 ;
     RECT  26.708 2.148 26.812 127.452 ;
     RECT  26.812 2.418 27.004 127.182 ;
     RECT  27.004 3.936 27.155 3.96 ;
     RECT  27.004 32.304 27.155 32.616 ;
     RECT  27.155 32.304 27.395 32.328 ;
     RECT  27.004 37.632 27.929 39.576 ;
     RECT  27.004 45.504 27.965 45.96 ;
     RECT  27.004 33.792 27.997 36.6 ;
     RECT  27.965 45.936 28.001 45.96 ;
     RECT  27.929 39.168 28.019 39.576 ;
     RECT  27.004 41.136 28.097 43.368 ;
     RECT  27.004 82.656 28.115 82.68 ;
     RECT  27.004 55.488 28.117 55.512 ;
     RECT  28.033 58.704 28.117 59.256 ;
     RECT  27.997 33.552 28.177 36.6 ;
     RECT  28.097 41.136 28.181 43.896 ;
     RECT  28.181 41.136 28.253 43.368 ;
     RECT  28.177 33.072 28.289 36.6 ;
     RECT  28.117 55.296 28.289 55.512 ;
     RECT  28.019 39.264 28.501 39.576 ;
     RECT  28.289 33.072 28.549 36.504 ;
     RECT  28.549 32.688 28.645 36.504 ;
     RECT  28.537 5.088 29.408 5.112 ;
     RECT  27.004 22.464 29.408 22.488 ;
     RECT  28.645 32.304 29.408 36.504 ;
     RECT  27.929 37.632 29.408 38.184 ;
     RECT  28.501 39.264 29.408 40.056 ;
     RECT  28.253 41.136 29.408 42.6 ;
     RECT  28.069 46.848 29.408 46.872 ;
     RECT  28.289 55.488 29.408 55.512 ;
     RECT  27.004 106.224 29.408 107.544 ;
     RECT  29.408 2.148 29.512 127.452 ;
     RECT  29.512 2.418 29.704 127.182 ;
     RECT  29.704 46.752 29.801 46.872 ;
     RECT  29.704 43.92 29.881 44.568 ;
     RECT  29.704 38.976 29.904 42.6 ;
     RECT  29.704 5.664 29.917 5.688 ;
     RECT  29.881 44.112 30.604 44.568 ;
     RECT  29.704 32.304 30.659 32.328 ;
     RECT  30.604 44.112 30.737 44.136 ;
     RECT  29.801 46.752 30.769 46.776 ;
     RECT  30.769 46.752 30.809 46.872 ;
     RECT  29.704 33.84 31.201 37.656 ;
     RECT  29.904 39.312 31.309 42.6 ;
     RECT  31.309 39.264 31.333 42.6 ;
     RECT  31.201 33.84 31.417 38.28 ;
     RECT  31.333 39.264 31.417 42.888 ;
     RECT  31.417 33.84 31.957 42.888 ;
     RECT  31.861 43.872 31.957 43.896 ;
     RECT  29.704 22.464 32.108 22.488 ;
     RECT  31.957 33.84 32.108 43.896 ;
     RECT  31.813 45.024 32.108 45.048 ;
     RECT  30.809 46.848 32.108 46.872 ;
     RECT  29.704 106.224 32.108 107.544 ;
     RECT  32.108 2.148 32.212 127.452 ;
     RECT  32.212 2.418 32.404 127.182 ;
     RECT  32.404 35.856 32.681 42.552 ;
     RECT  32.681 41.76 33.113 42.552 ;
     RECT  32.681 35.856 33.251 40.68 ;
     RECT  32.404 43.536 33.299 43.896 ;
     RECT  33.251 36.24 33.653 40.68 ;
     RECT  32.404 44.928 34.009 45.624 ;
     RECT  33.113 41.76 34.117 42.504 ;
     RECT  33.299 43.536 34.117 43.56 ;
     RECT  34.117 41.76 34.261 43.56 ;
     RECT  32.404 22.464 34.808 22.488 ;
     RECT  32.404 33.84 34.808 33.864 ;
     RECT  33.653 36.24 34.808 40.056 ;
     RECT  34.261 41.136 34.808 43.56 ;
     RECT  34.009 44.928 34.808 45.816 ;
     RECT  32.404 46.848 34.808 46.872 ;
     RECT  32.404 106.224 34.808 107.544 ;
     RECT  34.808 2.148 34.912 127.452 ;
     RECT  34.912 2.418 35.104 127.182 ;
     RECT  35.104 36.912 35.345 46.872 ;
     RECT  35.345 37.152 35.921 46.872 ;
     RECT  35.921 39.264 36.179 46.872 ;
     RECT  36.179 39.264 36.245 40.536 ;
     RECT  35.921 37.152 36.281 38.28 ;
     RECT  36.281 37.632 36.353 38.28 ;
     RECT  35.104 22.464 37.508 22.488 ;
     RECT  35.104 33.84 37.508 33.864 ;
     RECT  36.353 37.632 37.508 37.656 ;
     RECT  36.245 39.264 37.508 40.056 ;
     RECT  36.179 41.664 37.508 46.872 ;
     RECT  35.104 106.224 37.508 107.544 ;
     RECT  37.508 2.148 37.612 127.452 ;
     RECT  37.612 2.418 37.804 127.182 ;
     RECT  37.804 41.376 38.828 47.928 ;
     RECT  37.804 37.728 38.869 38.28 ;
     RECT  37.804 39.312 38.905 40.056 ;
     RECT  38.828 41.328 38.905 47.928 ;
     RECT  38.905 39.312 39.059 47.928 ;
     RECT  38.869 37.44 39.164 38.28 ;
     RECT  39.059 39.312 39.164 40.2 ;
     RECT  37.804 22.464 40.208 22.488 ;
     RECT  37.804 33.84 40.208 33.864 ;
     RECT  39.164 37.44 40.208 40.2 ;
     RECT  39.059 41.376 40.208 47.928 ;
     RECT  37.804 106.32 40.208 107.544 ;
     RECT  40.208 2.148 40.312 127.452 ;
     RECT  40.312 2.418 40.504 127.182 ;
     RECT  40.504 37.44 41.429 47.832 ;
     RECT  41.429 37.68 41.533 47.832 ;
     RECT  41.533 37.68 42.716 48.024 ;
     RECT  40.504 22.464 42.908 22.488 ;
     RECT  40.504 33.84 42.908 33.864 ;
     RECT  42.716 37.584 42.908 48.024 ;
     RECT  42.908 2.148 43.012 48.024 ;
     RECT  42.908 108.528 43.012 127.452 ;
     RECT  40.504 106.32 43.1 107.544 ;
     RECT  43.012 108.528 43.1 127.182 ;
     RECT  43.012 2.418 43.204 48.024 ;
     RECT  43.1 106.32 43.204 127.182 ;
     RECT  43.204 37.68 43.272 48.024 ;
     RECT  43.204 106.32 43.272 107.544 ;
     RECT  43.272 37.68 44.483 107.544 ;
     RECT  44.483 37.68 45.025 40.68 ;
     RECT  43.204 22.464 45.608 22.488 ;
     RECT  43.204 33.84 45.608 33.864 ;
     RECT  45.025 37.632 45.608 40.68 ;
     RECT  44.483 41.76 45.608 107.544 ;
     RECT  45.608 2.148 45.712 107.544 ;
     RECT  45.608 108.528 45.712 127.452 ;
     RECT  45.712 41.76 45.8 107.544 ;
     RECT  45.712 108.528 45.8 127.182 ;
     RECT  45.712 2.418 45.904 40.782 ;
     RECT  45.8 41.76 45.904 127.182 ;
     RECT  45.904 37.584 46.685 40.68 ;
     RECT  46.685 37.632 46.933 40.68 ;
     RECT  45.904 41.76 46.933 107.544 ;
     RECT  45.904 22.464 48.308 22.488 ;
     RECT  45.904 33.84 48.308 33.864 ;
     RECT  46.933 37.632 48.308 107.544 ;
     RECT  48.308 2.148 48.412 107.544 ;
     RECT  48.308 108.528 48.412 127.452 ;
     RECT  48.412 41.76 48.5 107.544 ;
     RECT  48.412 108.528 48.5 127.182 ;
     RECT  48.412 2.418 48.604 40.782 ;
     RECT  48.5 41.76 48.604 127.182 ;
     RECT  48.604 22.464 51.008 22.488 ;
     RECT  48.604 33.84 51.008 33.864 ;
     RECT  48.604 37.632 51.008 40.68 ;
     RECT  48.604 41.76 51.008 107.544 ;
     RECT  51.008 2.148 51.112 107.544 ;
     RECT  51.008 108.528 51.112 127.452 ;
     RECT  51.112 41.76 51.2 107.544 ;
     RECT  51.112 108.528 51.2 127.182 ;
     RECT  51.112 2.418 51.304 40.782 ;
     RECT  51.2 41.76 51.304 127.182 ;
     RECT  51.304 37.632 51.443 40.728 ;
     RECT  51.443 40.512 52.513 40.728 ;
     RECT  51.304 41.76 52.513 107.544 ;
     RECT  51.443 37.632 52.885 39.336 ;
     RECT  52.513 40.512 53.233 107.544 ;
     RECT  51.304 22.464 53.708 22.488 ;
     RECT  51.304 33.84 53.708 33.864 ;
     RECT  52.885 37.392 53.708 39.336 ;
     RECT  53.233 40.368 53.708 107.544 ;
     RECT  53.708 2.148 53.812 107.544 ;
     RECT  53.708 108.528 53.812 127.452 ;
     RECT  53.812 2.418 53.813 107.544 ;
     RECT  53.813 41.76 53.9 107.544 ;
     RECT  53.812 108.528 53.9 127.182 ;
     RECT  53.813 2.418 54.004 40.782 ;
     RECT  53.9 41.76 54.004 127.182 ;
     RECT  54.004 22.464 56.408 22.488 ;
     RECT  54.004 33.84 56.408 33.864 ;
     RECT  54.004 37.392 56.408 40.68 ;
     RECT  54.004 41.76 56.408 107.544 ;
     RECT  56.408 2.148 56.512 107.544 ;
     RECT  56.408 108.528 56.512 127.452 ;
     RECT  56.512 2.418 56.6 107.544 ;
     RECT  56.512 108.528 56.6 127.182 ;
     RECT  56.6 2.418 56.704 127.182 ;
     RECT  56.704 37.392 57.017 107.544 ;
     RECT  57.017 37.392 58.057 40.68 ;
     RECT  57.017 41.76 58.057 107.544 ;
     RECT  56.704 22.464 59.108 22.488 ;
     RECT  56.704 33.84 59.108 33.864 ;
     RECT  58.057 37.392 59.108 107.544 ;
     RECT  59.108 2.148 59.212 107.544 ;
     RECT  59.108 108.528 59.212 127.452 ;
     RECT  59.212 2.418 59.285 107.544 ;
     RECT  59.285 41.76 59.3 107.544 ;
     RECT  59.212 108.528 59.3 127.182 ;
     RECT  59.285 2.418 59.404 40.782 ;
     RECT  59.3 41.76 59.404 127.182 ;
     RECT  59.404 22.464 61.808 22.488 ;
     RECT  59.404 33.84 61.808 33.864 ;
     RECT  61.525 36.24 61.808 36.264 ;
     RECT  59.404 37.392 61.808 40.68 ;
     RECT  59.404 41.76 61.808 107.544 ;
     RECT  61.808 2.148 61.912 107.544 ;
     RECT  61.808 108.528 61.912 127.452 ;
     RECT  61.912 41.76 62 107.544 ;
     RECT  61.912 108.528 62 127.182 ;
     RECT  61.912 2.418 62.104 40.782 ;
     RECT  62 41.76 62.104 127.182 ;
     RECT  62.104 22.464 64.508 22.488 ;
     RECT  62.104 33.84 64.508 33.864 ;
     RECT  62.104 36.24 64.508 39.528 ;
     RECT  62.104 40.656 64.508 40.68 ;
     RECT  62.104 41.76 64.508 107.544 ;
     RECT  64.508 2.148 64.612 107.544 ;
     RECT  64.508 108.528 64.612 127.452 ;
     RECT  64.612 41.76 64.7 107.544 ;
     RECT  64.612 108.528 64.7 127.182 ;
     RECT  64.612 2.418 64.804 40.782 ;
     RECT  64.7 41.76 64.804 127.182 ;
     RECT  64.804 33.84 65.837 34.152 ;
     RECT  64.804 36.432 66.332 40.68 ;
     RECT  65.837 33.84 66.373 33.864 ;
     RECT  66.265 1.728 66.563 1.752 ;
     RECT  66.589 3.696 67.208 3.72 ;
     RECT  64.804 22.464 67.208 22.488 ;
     RECT  66.373 33.792 67.208 33.864 ;
     RECT  66.332 35.952 67.208 40.68 ;
     RECT  64.804 41.76 67.208 107.544 ;
     RECT  67.208 2.148 67.312 107.544 ;
     RECT  67.208 108.528 67.312 127.452 ;
     RECT  67.312 41.76 67.4 107.544 ;
     RECT  67.312 108.528 67.4 127.182 ;
     RECT  67.312 2.418 67.504 40.782 ;
     RECT  67.4 41.76 67.504 127.182 ;
     RECT  67.504 36.912 67.781 40.68 ;
     RECT  67.781 40.56 69.109 40.68 ;
     RECT  67.781 36.912 69.505 39.336 ;
     RECT  69.109 40.416 69.505 40.68 ;
     RECT  67.504 22.464 69.781 22.488 ;
     RECT  69.781 22.464 69.908 22.776 ;
     RECT  69.721 31.344 69.908 31.368 ;
     RECT  67.504 33.84 69.908 33.864 ;
     RECT  67.504 35.856 69.908 35.88 ;
     RECT  69.505 36.912 69.908 40.68 ;
     RECT  67.504 41.76 69.908 107.544 ;
     RECT  69.908 2.148 70.012 107.544 ;
     RECT  69.908 108.528 70.012 127.452 ;
     RECT  70.012 41.76 70.1 107.544 ;
     RECT  70.012 108.528 70.1 127.182 ;
     RECT  70.012 2.418 70.204 40.782 ;
     RECT  70.1 41.76 70.204 127.182 ;
     RECT  70.204 36.432 71.701 40.68 ;
     RECT  70.204 33.84 72.608 33.864 ;
     RECT  71.701 36.096 72.608 40.68 ;
     RECT  70.204 41.76 72.608 107.544 ;
     RECT  72.608 2.148 72.712 107.544 ;
     RECT  72.608 108.528 72.712 127.452 ;
     RECT  72.712 41.76 72.8 107.544 ;
     RECT  72.712 108.528 72.8 127.182 ;
     RECT  72.712 2.418 72.904 40.782 ;
     RECT  72.8 41.76 72.904 127.182 ;
     RECT  72.904 36.096 72.965 40.68 ;
     RECT  72.904 33.84 75.308 33.864 ;
     RECT  72.965 36.912 75.308 40.68 ;
     RECT  72.904 41.76 75.308 107.544 ;
     RECT  75.308 2.148 75.412 107.544 ;
     RECT  75.308 108.528 75.412 127.452 ;
     RECT  75.412 41.76 75.5 107.544 ;
     RECT  75.412 108.528 75.5 127.182 ;
     RECT  75.412 2.418 75.604 40.782 ;
     RECT  75.5 41.76 75.604 127.182 ;
     RECT  75.604 36.912 75.875 40.68 ;
     RECT  75.875 37.92 76.979 40.68 ;
     RECT  75.604 33.84 78.008 33.864 ;
     RECT  75.875 36.912 78.008 36.936 ;
     RECT  76.979 38.16 78.008 40.68 ;
     RECT  75.604 41.76 78.008 107.544 ;
     RECT  78.008 2.148 78.112 107.544 ;
     RECT  78.008 108.528 78.112 127.452 ;
     RECT  78.112 41.76 78.2 107.544 ;
     RECT  78.112 108.528 78.2 127.182 ;
     RECT  78.112 2.418 78.304 40.782 ;
     RECT  78.2 41.76 78.304 127.182 ;
     RECT  78.304 38.16 80.053 40.68 ;
     RECT  78.304 41.76 80.053 107.544 ;
     RECT  78.304 33.84 80.708 33.864 ;
     RECT  78.304 36.912 80.708 36.936 ;
     RECT  80.053 38.16 80.708 107.544 ;
     RECT  80.708 2.148 80.812 107.544 ;
     RECT  80.708 108.528 80.812 127.452 ;
     RECT  80.812 2.418 80.9 107.544 ;
     RECT  80.812 108.528 80.9 127.182 ;
     RECT  80.9 2.418 81.004 127.182 ;
     RECT  81.004 38.16 81.144 107.544 ;
     RECT  81.144 38.16 81.216 48.024 ;
     RECT  81.216 38.16 81.347 44.184 ;
     RECT  81.347 42 81.497 44.184 ;
     RECT  81.497 42 82.645 44.088 ;
     RECT  81.144 106.32 82.645 107.544 ;
     RECT  81.004 33.84 83.408 33.864 ;
     RECT  81.004 36.912 83.408 36.936 ;
     RECT  81.347 38.16 83.408 40.872 ;
     RECT  82.645 41.952 83.408 44.088 ;
     RECT  81.216 45.696 83.408 45.72 ;
     RECT  81.144 68.112 83.408 68.136 ;
     RECT  81.144 93.6 83.408 93.624 ;
     RECT  81.144 97.92 83.408 97.944 ;
     RECT  82.645 106.224 83.408 107.544 ;
     RECT  83.408 2.148 83.512 127.452 ;
     RECT  83.512 2.418 83.704 127.182 ;
     RECT  83.704 33.84 86.108 33.864 ;
     RECT  83.704 36.912 86.108 36.936 ;
     RECT  83.704 38.256 86.108 40.68 ;
     RECT  83.704 41.952 86.108 43.128 ;
     RECT  83.704 45.696 86.108 45.72 ;
     RECT  83.704 106.224 86.108 107.544 ;
     RECT  86.108 2.148 86.212 127.452 ;
     RECT  86.212 2.418 86.404 127.182 ;
     RECT  86.404 33.84 88.808 33.864 ;
     RECT  86.404 36.912 88.808 36.936 ;
     RECT  86.404 38.256 88.808 40.68 ;
     RECT  86.404 41.952 88.808 43.128 ;
     RECT  86.404 45.696 88.808 45.72 ;
     RECT  86.404 106.224 88.808 107.544 ;
     RECT  88.808 2.148 88.912 127.452 ;
     RECT  88.912 2.418 89.104 127.182 ;
     RECT  89.104 38.256 89.129 40.68 ;
     RECT  89.104 33.84 91.508 33.864 ;
     RECT  89.104 36.912 91.508 36.936 ;
     RECT  89.129 38.496 91.508 40.68 ;
     RECT  89.104 41.952 91.508 43.128 ;
     RECT  89.104 45.696 91.508 45.72 ;
     RECT  89.104 106.224 91.508 107.544 ;
     RECT  91.508 2.148 91.612 127.452 ;
     RECT  91.612 2.418 91.804 127.182 ;
     RECT  91.804 41.952 93.053 43.128 ;
     RECT  93.053 42 94.069 43.128 ;
     RECT  91.804 33.84 94.208 33.864 ;
     RECT  91.804 36.912 94.208 36.936 ;
     RECT  91.804 38.496 94.208 40.68 ;
     RECT  94.069 42 94.208 43.56 ;
     RECT  91.804 45.696 94.208 45.72 ;
     RECT  91.804 106.224 94.208 107.544 ;
     RECT  94.208 2.148 94.312 127.452 ;
     RECT  94.312 2.418 94.504 127.182 ;
     RECT  94.504 33.84 96.908 33.864 ;
     RECT  94.504 36.912 96.908 36.936 ;
     RECT  94.504 38.496 96.908 39.336 ;
     RECT  94.504 40.656 96.908 40.68 ;
     RECT  94.504 42 96.908 43.56 ;
     RECT  94.504 45.696 96.908 45.72 ;
     RECT  94.504 106.32 96.908 107.544 ;
     RECT  96.908 2.148 97.012 127.452 ;
     RECT  97.012 2.418 97.204 127.182 ;
     RECT  97.204 106.32 98.593 107.544 ;
     RECT  99.385 77.472 99.493 77.496 ;
     RECT  97.204 33.84 99.608 33.864 ;
     RECT  97.204 36.912 99.608 36.936 ;
     RECT  97.204 38.496 99.608 39.336 ;
     RECT  97.204 40.656 99.608 40.68 ;
     RECT  97.204 42 99.608 43.56 ;
     RECT  97.204 45.696 99.608 45.72 ;
     RECT  99.493 76.944 99.608 77.496 ;
     RECT  98.593 106.176 99.608 107.544 ;
     RECT  99.608 2.148 99.712 127.452 ;
     RECT  99.712 2.418 99.904 127.182 ;
     RECT  99.904 38.112 100.109 40.68 ;
     RECT  99.904 67.248 100.211 67.272 ;
     RECT  100.109 40.656 100.325 40.68 ;
     RECT  99.904 45.12 100.433 45.72 ;
     RECT  100.109 38.112 101.081 39.336 ;
     RECT  100.433 45.696 101.393 45.72 ;
     RECT  99.904 42.24 101.413 43.56 ;
     RECT  101.413 42.24 101.473 44.424 ;
     RECT  101.393 45.696 101.473 46.2 ;
     RECT  101.317 40.704 101.653 40.728 ;
     RECT  101.081 38.112 102.049 39.048 ;
     RECT  102.049 38.112 102.157 39.144 ;
     RECT  101.653 40.704 102.157 40.968 ;
     RECT  99.904 33.84 102.308 34.728 ;
     RECT  99.904 36.912 102.308 36.936 ;
     RECT  102.157 38.112 102.308 40.968 ;
     RECT  101.473 42.24 102.308 46.2 ;
     RECT  101.329 76.896 102.308 76.92 ;
     RECT  99.904 106.176 102.308 107.544 ;
     RECT  102.308 2.148 102.412 127.452 ;
     RECT  102.412 2.418 102.604 127.182 ;
     RECT  102.604 76.896 102.961 76.92 ;
     RECT  102.604 42.144 103.235 45.72 ;
     RECT  103.235 42.144 103.241 44.52 ;
     RECT  102.604 40.944 103.283 40.968 ;
     RECT  102.604 77.952 103.379 77.976 ;
     RECT  102.604 38.928 103.529 39.912 ;
     RECT  103.241 42.24 103.789 44.52 ;
     RECT  103.724 80.112 103.811 80.136 ;
     RECT  103.877 80.352 103.961 80.376 ;
     RECT  103.235 45.504 104.749 45.72 ;
     RECT  102.604 33.84 105.008 33.864 ;
     RECT  102.604 36.912 105.008 36.936 ;
     RECT  103.529 38.928 105.008 38.952 ;
     RECT  103.789 42.24 105.008 44.472 ;
     RECT  104.749 45.504 105.008 45.768 ;
     RECT  102.604 46.8 105.008 46.824 ;
     RECT  104.245 81.744 105.008 81.768 ;
     RECT  104.156 83.616 105.008 83.64 ;
     RECT  102.604 106.032 105.008 107.544 ;
     RECT  105.008 2.148 105.112 127.452 ;
     RECT  105.112 2.418 105.304 127.182 ;
     RECT  105.304 106.032 105.365 107.352 ;
     RECT  105.304 42.24 106.121 45.72 ;
     RECT  105.365 106.224 106.657 107.352 ;
     RECT  106.121 44.88 106.741 45.72 ;
     RECT  106.7 47.328 106.741 47.352 ;
     RECT  106.121 42.24 107.377 43.56 ;
     RECT  106.741 44.88 107.377 47.352 ;
     RECT  105.304 38.928 107.593 38.952 ;
     RECT  105.304 33.84 107.708 33.864 ;
     RECT  105.304 36.912 107.708 36.936 ;
     RECT  107.593 38.784 107.708 38.952 ;
     RECT  107.377 42.24 107.708 47.352 ;
     RECT  106.657 106.176 107.708 107.352 ;
     RECT  107.708 2.148 107.812 127.452 ;
     RECT  107.812 2.418 108.004 127.182 ;
     RECT  65.365 0.144 108.029 0.168 ;
     RECT  108.004 42.24 108.065 47.88 ;
     RECT  108.065 42.24 108.419 43.512 ;
     RECT  108.419 42.288 108.563 43.512 ;
     RECT  108.065 44.88 109.141 47.88 ;
     RECT  108.004 36.912 110.408 36.936 ;
     RECT  108.004 38.784 110.408 38.808 ;
     RECT  108.563 42.288 110.408 43.128 ;
     RECT  109.141 44.448 110.408 47.88 ;
     RECT  108.004 106.176 110.408 107.352 ;
     RECT  110.408 2.148 110.512 127.452 ;
     RECT  110.512 2.418 110.704 127.182 ;
     RECT  110.704 42.288 111.161 43.416 ;
     RECT  110.704 44.592 111.665 47.16 ;
     RECT  111.665 44.592 111.989 46.152 ;
     RECT  111.161 42.288 112.357 43.32 ;
     RECT  111.989 45.216 112.993 46.152 ;
     RECT  111.665 47.136 112.993 47.16 ;
     RECT  110.704 36.912 113.108 36.936 ;
     RECT  110.704 39.024 113.108 39.048 ;
     RECT  112.357 42.288 113.108 43.944 ;
     RECT  112.993 45.216 113.108 47.16 ;
     RECT  110.704 106.176 113.108 107.352 ;
     RECT  113.108 2.148 113.212 127.452 ;
     RECT  113.212 2.418 113.404 127.182 ;
     RECT  113.404 42.288 113.825 47.976 ;
     RECT  113.825 45.12 114.397 47.976 ;
     RECT  114.397 45.12 114.617 48.024 ;
     RECT  113.825 42.288 114.653 43.896 ;
     RECT  113.404 39.024 115.141 39.048 ;
     RECT  114.617 45.12 115.405 47.976 ;
     RECT  113.404 36.912 115.808 36.936 ;
     RECT  115.141 39.024 115.808 39.768 ;
     RECT  114.653 42.288 115.808 43.368 ;
     RECT  115.405 44.688 115.808 47.976 ;
     RECT  113.404 106.176 115.808 107.352 ;
     RECT  115.808 2.148 115.912 127.452 ;
     RECT  115.912 2.418 116.104 127.182 ;
     RECT  116.104 36.912 116.785 37.032 ;
     RECT  116.104 42.192 117.205 47.688 ;
     RECT  117.205 42.144 117.251 47.688 ;
     RECT  116.785 36.912 118.508 36.936 ;
     RECT  116.104 39.744 118.508 39.768 ;
     RECT  117.251 42.144 118.508 43.272 ;
     RECT  117.251 44.4 118.508 47.688 ;
     RECT  116.104 106.176 118.508 107.352 ;
     RECT  118.508 2.148 118.612 127.452 ;
     RECT  118.612 2.418 118.804 127.182 ;
     RECT  118.804 42.192 119.123 47.688 ;
     RECT  119.123 45.6 119.225 47.16 ;
     RECT  119.123 42.192 120.013 44.616 ;
     RECT  120.013 41.904 120.121 44.616 ;
     RECT  119.225 45.6 120.121 45.72 ;
     RECT  119.225 46.704 120.125 47.16 ;
     RECT  120.121 41.904 120.553 45.72 ;
     RECT  120.553 41.472 120.985 45.72 ;
     RECT  120.985 41.472 121.093 45.816 ;
     RECT  118.804 36.912 121.208 36.936 ;
     RECT  118.804 39.744 121.208 39.768 ;
     RECT  121.093 41.472 121.208 46.008 ;
     RECT  120.125 47.136 121.208 47.16 ;
     RECT  118.804 106.176 121.208 107.352 ;
     RECT  121.208 2.148 121.312 127.452 ;
     RECT  121.312 2.418 121.504 127.182 ;
     RECT  121.504 37.968 121.619 37.992 ;
     RECT  121.504 36.768 122.003 36.936 ;
     RECT  121.504 106.224 122.533 107.352 ;
     RECT  121.504 41.184 122.569 47.448 ;
     RECT  122.003 36.768 122.573 36.888 ;
     RECT  122.569 41.184 122.681 47.64 ;
     RECT  122.681 46.224 122.821 47.64 ;
     RECT  122.821 46.224 123.361 47.88 ;
     RECT  122.681 41.184 123.749 45 ;
     RECT  123.361 46.224 123.749 48.456 ;
     RECT  122.573 36.864 123.908 36.888 ;
     RECT  121.504 39.744 123.908 39.768 ;
     RECT  123.749 41.184 123.908 48.456 ;
     RECT  122.533 106.176 123.908 107.352 ;
     RECT  123.908 2.148 124.012 127.452 ;
     RECT  124.012 2.418 124.204 127.182 ;
     RECT  124.204 41.616 124.445 48.648 ;
     RECT  124.445 41.616 124.835 47.928 ;
     RECT  124.835 44.4 124.913 47.928 ;
     RECT  124.913 44.4 125.201 45.72 ;
     RECT  124.835 41.616 125.305 43.416 ;
     RECT  124.913 46.704 125.489 47.928 ;
     RECT  125.305 40.992 125.809 43.416 ;
     RECT  125.201 44.4 125.809 45.48 ;
     RECT  124.204 39.744 126.313 39.768 ;
     RECT  125.809 40.992 126.313 45.48 ;
     RECT  124.204 36.864 126.608 36.888 ;
     RECT  126.469 38.736 126.608 38.76 ;
     RECT  126.313 39.744 126.608 45.48 ;
     RECT  125.489 46.8 126.608 47.928 ;
     RECT  124.204 106.176 126.608 107.352 ;
     RECT  126.608 2.148 126.712 127.452 ;
     RECT  126.712 2.418 126.904 127.182 ;
     RECT  126.904 42.288 127.001 45.48 ;
     RECT  127.001 42.432 127.145 45.48 ;
     RECT  127.145 44.064 127.181 45.48 ;
     RECT  126.904 46.56 128.221 47.928 ;
     RECT  127.181 44.064 128.257 45.432 ;
     RECT  128.221 46.464 128.257 47.928 ;
     RECT  126.904 36.864 129.308 36.888 ;
     RECT  126.904 38.736 129.308 38.76 ;
     RECT  126.904 39.744 129.308 40.056 ;
     RECT  128.257 44.064 129.337 47.928 ;
     RECT  129.337 43.968 129.373 47.928 ;
     RECT  129.308 2.148 129.412 41.052 ;
     RECT  129.308 108.528 129.412 127.452 ;
     RECT  126.904 106.224 129.5 107.352 ;
     RECT  129.412 108.528 129.5 127.182 ;
     RECT  129.412 2.418 129.604 40.782 ;
     RECT  129.5 106.224 129.604 127.182 ;
     RECT  127.145 42.432 129.672 42.744 ;
     RECT  129.373 43.968 129.672 48.024 ;
     RECT  129.604 106.224 129.672 107.352 ;
     RECT  129.604 36.768 130.565 36.888 ;
     RECT  130.565 36.864 132.008 36.888 ;
     RECT  129.604 38.736 132.008 38.76 ;
     RECT  129.604 39.744 132.008 40.056 ;
     RECT  132.008 2.148 132.112 41.052 ;
     RECT  132.008 108.528 132.112 127.452 ;
     RECT  129.672 42.432 132.2 107.352 ;
     RECT  132.112 108.528 132.2 127.182 ;
     RECT  132.112 2.418 132.304 40.782 ;
     RECT  132.2 42.432 132.304 127.182 ;
     RECT  132.304 36.864 134.708 36.888 ;
     RECT  132.304 38.736 134.708 38.76 ;
     RECT  132.304 39.744 134.708 40.056 ;
     RECT  134.708 2.148 134.812 41.052 ;
     RECT  134.708 108.528 134.812 127.452 ;
     RECT  132.304 42.432 134.9 107.352 ;
     RECT  134.812 108.528 134.9 127.182 ;
     RECT  134.812 2.418 135.004 40.782 ;
     RECT  134.9 42.432 135.004 127.182 ;
     RECT  135.004 36.864 137.408 36.888 ;
     RECT  135.004 38.736 137.408 38.76 ;
     RECT  135.004 39.744 137.408 40.056 ;
     RECT  137.408 2.148 137.512 41.052 ;
     RECT  137.408 108.528 137.512 127.452 ;
     RECT  135.004 42.432 137.6 107.352 ;
     RECT  137.512 108.528 137.6 127.182 ;
     RECT  137.512 2.418 137.704 40.782 ;
     RECT  137.6 42.432 137.704 127.182 ;
     RECT  137.704 36.768 138.557 36.888 ;
     RECT  138.557 36.864 140.108 36.888 ;
     RECT  137.704 38.736 140.108 38.76 ;
     RECT  137.704 39.744 140.108 40.056 ;
     RECT  140.108 2.148 140.212 41.052 ;
     RECT  140.108 108.528 140.212 127.452 ;
     RECT  137.704 42.432 140.3 107.352 ;
     RECT  140.212 108.528 140.3 127.182 ;
     RECT  140.212 2.418 140.404 40.782 ;
     RECT  140.3 42.432 140.404 127.182 ;
     RECT  140.404 36.864 142.808 36.888 ;
     RECT  140.404 38.688 142.808 38.76 ;
     RECT  140.404 39.744 142.808 40.056 ;
     RECT  142.808 2.148 142.912 41.052 ;
     RECT  142.808 108.528 142.912 127.452 ;
     RECT  140.404 42.432 143 107.352 ;
     RECT  142.912 108.528 143 127.182 ;
     RECT  142.912 2.418 143.104 40.782 ;
     RECT  143 42.432 143.104 127.182 ;
     RECT  143.104 36.864 145.508 36.888 ;
     RECT  143.104 38.688 145.508 38.76 ;
     RECT  143.104 39.744 145.508 40.056 ;
     RECT  145.508 2.148 145.612 41.052 ;
     RECT  145.508 108.528 145.612 127.452 ;
     RECT  143.104 42.432 145.7 107.352 ;
     RECT  145.612 108.528 145.7 127.182 ;
     RECT  145.612 2.418 145.804 40.782 ;
     RECT  145.7 42.432 145.804 127.182 ;
     RECT  145.804 38.544 145.901 38.76 ;
     RECT  145.804 36.768 146.513 36.888 ;
     RECT  146.513 36.864 148.208 36.888 ;
     RECT  145.901 38.544 148.208 38.712 ;
     RECT  145.804 39.744 148.208 40.056 ;
     RECT  148.208 2.148 148.312 41.052 ;
     RECT  148.208 108.528 148.312 127.452 ;
     RECT  145.804 42.432 148.4 107.352 ;
     RECT  148.312 108.528 148.4 127.182 ;
     RECT  148.312 2.418 148.504 40.782 ;
     RECT  148.4 42.432 148.504 127.182 ;
     RECT  149.209 0.192 149.507 0.216 ;
     RECT  149.557 3.936 149.644 3.96 ;
     RECT  148.504 36.864 150.908 36.888 ;
     RECT  148.504 38.448 150.908 38.712 ;
     RECT  148.504 39.744 150.908 40.056 ;
     RECT  150.908 2.148 151.012 41.052 ;
     RECT  150.908 108.528 151.012 127.452 ;
     RECT  148.504 42.432 151.1 107.352 ;
     RECT  151.012 108.528 151.1 127.182 ;
     RECT  151.012 2.418 151.204 40.782 ;
     RECT  151.1 42.432 151.204 127.182 ;
     RECT  151.204 36.864 153.608 36.888 ;
     RECT  151.204 38.448 153.608 38.712 ;
     RECT  151.204 39.744 153.608 40.056 ;
     RECT  153.608 2.148 153.712 41.052 ;
     RECT  153.608 108.528 153.712 127.452 ;
     RECT  151.204 42.432 153.8 107.352 ;
     RECT  153.712 108.528 153.8 127.182 ;
     RECT  153.712 2.418 153.904 40.782 ;
     RECT  153.8 42.432 153.904 127.182 ;
     RECT  153.904 36.768 154.505 36.888 ;
     RECT  154.505 36.864 156.308 36.888 ;
     RECT  153.904 38.448 156.308 38.712 ;
     RECT  153.904 39.744 156.308 40.056 ;
     RECT  156.308 2.148 156.412 41.052 ;
     RECT  156.308 108.528 156.412 127.452 ;
     RECT  153.904 42.432 156.5 107.352 ;
     RECT  156.412 108.528 156.5 127.182 ;
     RECT  156.412 2.418 156.604 40.782 ;
     RECT  156.5 42.432 156.604 127.182 ;
     RECT  156.604 39.744 157.205 40.056 ;
     RECT  157.205 40.032 158.684 40.056 ;
     RECT  156.604 36.864 159.008 36.888 ;
     RECT  156.604 38.448 159.008 38.712 ;
     RECT  158.684 39.888 159.008 40.056 ;
     RECT  159.008 2.148 159.112 41.052 ;
     RECT  159.008 108.528 159.112 127.452 ;
     RECT  156.604 42.432 159.2 107.352 ;
     RECT  159.112 108.528 159.2 127.182 ;
     RECT  159.112 2.418 159.304 40.782 ;
     RECT  159.2 42.432 159.304 127.182 ;
     RECT  159.304 36.864 161.708 36.888 ;
     RECT  159.304 38.448 161.708 38.712 ;
     RECT  159.304 40.032 161.708 40.056 ;
     RECT  161.708 2.148 161.812 41.052 ;
     RECT  161.708 108.528 161.812 127.452 ;
     RECT  159.304 42.432 161.9 107.352 ;
     RECT  161.812 108.528 161.9 127.182 ;
     RECT  161.812 2.418 162.004 40.782 ;
     RECT  161.9 42.432 162.004 127.182 ;
     RECT  162.004 36.768 162.497 36.888 ;
     RECT  162.497 36.864 164.408 36.888 ;
     RECT  162.004 38.448 164.408 38.712 ;
     RECT  162.004 40.032 164.408 40.056 ;
     RECT  164.408 2.148 164.512 41.052 ;
     RECT  164.408 108.528 164.512 127.452 ;
     RECT  162.004 42.432 164.6 107.352 ;
     RECT  164.512 108.528 164.6 127.182 ;
     RECT  164.512 2.418 164.704 40.782 ;
     RECT  164.6 42.432 164.704 127.182 ;
     RECT  164.704 36.864 167.108 36.888 ;
     RECT  164.704 38.448 167.108 38.712 ;
     RECT  164.704 40.032 167.108 40.056 ;
     RECT  167.108 2.148 167.212 41.052 ;
     RECT  167.108 108.528 167.212 127.452 ;
     RECT  164.704 42.432 167.3 107.352 ;
     RECT  167.212 108.528 167.3 127.182 ;
     RECT  167.212 2.418 167.404 40.782 ;
     RECT  167.3 42.432 167.404 127.182 ;
     RECT  167.404 42.432 167.544 107.352 ;
     RECT  167.544 43.968 167.616 48.024 ;
     RECT  167.544 42.432 167.843 42.744 ;
     RECT  167.404 36.864 169.808 36.888 ;
     RECT  167.404 38.448 169.808 38.712 ;
     RECT  167.404 40.032 169.808 40.056 ;
     RECT  167.843 42.528 169.808 42.744 ;
     RECT  167.616 43.968 169.808 44.184 ;
     RECT  167.544 58.752 169.808 58.776 ;
     RECT  167.544 106.224 169.808 107.352 ;
     RECT  169.808 2.148 169.912 127.452 ;
     RECT  169.912 2.418 170.104 127.182 ;
     RECT  170.104 38.448 170.243 38.712 ;
     RECT  170.104 42.528 170.243 44.376 ;
     RECT  170.104 36.768 170.453 36.888 ;
     RECT  170.104 58.896 170.453 59.016 ;
     RECT  170.243 44.112 171.961 44.136 ;
     RECT  170.453 36.864 172.429 36.888 ;
     RECT  172.429 36.24 172.508 36.888 ;
     RECT  170.243 38.688 172.508 38.712 ;
     RECT  170.104 40.032 172.508 40.056 ;
     RECT  170.243 42.528 172.508 42.744 ;
     RECT  171.961 44.112 172.508 44.376 ;
     RECT  170.453 58.992 172.508 59.016 ;
     RECT  170.104 106.176 172.508 107.352 ;
     RECT  172.508 2.148 172.612 127.452 ;
     RECT  172.612 2.418 172.804 127.182 ;
     RECT  172.804 38.688 172.931 38.712 ;
     RECT  172.804 33.792 174.409 33.816 ;
     RECT  174.409 33.792 175.208 33.912 ;
     RECT  172.804 36.24 175.208 36.888 ;
     RECT  172.804 40.032 175.208 40.056 ;
     RECT  172.804 42.528 175.208 42.744 ;
     RECT  172.804 44.352 175.208 44.376 ;
     RECT  172.804 58.992 175.208 59.016 ;
     RECT  172.804 106.176 175.208 107.352 ;
     RECT  175.208 2.148 175.312 127.452 ;
     RECT  175.312 2.418 175.504 127.182 ;
     RECT  175.504 33.888 177.908 33.912 ;
     RECT  175.504 36.24 177.908 36.888 ;
     RECT  175.504 40.032 177.908 40.056 ;
     RECT  175.504 42.528 177.908 42.744 ;
     RECT  175.504 44.352 177.908 44.376 ;
     RECT  175.504 58.992 177.908 59.016 ;
     RECT  175.504 106.176 177.908 107.352 ;
     RECT  177.908 2.148 178.012 127.452 ;
     RECT  178.012 2.418 178.204 127.182 ;
     RECT  178.204 33.792 178.301 33.912 ;
     RECT  178.204 58.896 178.445 59.016 ;
     RECT  178.301 33.792 180.608 33.816 ;
     RECT  178.204 36.24 180.608 36.888 ;
     RECT  178.204 40.032 180.608 40.056 ;
     RECT  178.204 42.528 180.608 42.744 ;
     RECT  178.204 44.352 180.608 44.376 ;
     RECT  178.445 58.992 180.608 59.016 ;
     RECT  178.204 106.176 180.608 107.352 ;
     RECT  180.608 2.148 180.712 127.452 ;
     RECT  180.712 2.418 180.904 127.182 ;
     RECT  180.904 33.792 182.401 33.816 ;
     RECT  182.401 33.792 183.308 33.912 ;
     RECT  180.904 36.24 183.308 36.888 ;
     RECT  180.904 40.032 183.308 40.056 ;
     RECT  180.904 42.528 183.308 42.552 ;
     RECT  180.904 44.352 183.308 44.376 ;
     RECT  180.904 58.992 183.308 59.016 ;
     RECT  180.904 106.176 183.308 107.352 ;
     RECT  183.308 2.148 183.412 127.452 ;
     RECT  183.412 2.418 183.604 127.182 ;
     RECT  183.604 33.888 186.008 33.912 ;
     RECT  183.604 36.24 186.008 36.888 ;
     RECT  183.604 40.032 186.008 40.056 ;
     RECT  183.604 42.528 186.008 42.552 ;
     RECT  183.604 44.352 186.008 44.376 ;
     RECT  183.604 58.992 186.008 59.016 ;
     RECT  185.893 77.088 186.008 77.112 ;
     RECT  183.604 106.176 186.008 107.352 ;
     RECT  186.008 2.148 186.112 127.452 ;
     RECT  186.112 2.418 186.304 127.182 ;
     RECT  186.304 33.792 186.401 33.912 ;
     RECT  186.304 76.992 186.401 77.112 ;
     RECT  186.401 76.992 187.573 77.016 ;
     RECT  186.304 106.224 188.549 107.352 ;
     RECT  187.573 76.992 188.581 77.304 ;
     RECT  186.401 33.792 188.708 33.816 ;
     RECT  186.304 36.24 188.708 36.792 ;
     RECT  186.304 40.032 188.708 40.056 ;
     RECT  186.304 42.528 188.708 42.552 ;
     RECT  186.304 44.352 188.708 44.376 ;
     RECT  186.304 58.896 188.708 58.92 ;
     RECT  188.581 76.992 188.708 77.928 ;
     RECT  188.549 106.032 188.708 107.352 ;
     RECT  188.708 2.148 188.812 127.452 ;
     RECT  188.812 2.418 189.004 127.182 ;
     RECT  189.004 106.224 190.105 107.016 ;
     RECT  189.004 76.992 190.117 77.832 ;
     RECT  190.105 106.032 190.189 107.016 ;
     RECT  189.004 33.792 190.393 33.816 ;
     RECT  189.004 36.24 190.393 36.792 ;
     RECT  189.004 58.896 190.393 58.92 ;
     RECT  190.393 58.896 190.433 59.016 ;
     RECT  190.117 76.992 190.433 78.456 ;
     RECT  190.189 106.272 190.433 107.016 ;
     RECT  189.004 32.736 191.228 32.76 ;
     RECT  190.393 33.792 191.228 33.912 ;
     RECT  191.041 4.128 191.408 4.152 ;
     RECT  191.269 28.944 191.408 28.968 ;
     RECT  191.228 32.736 191.408 33.912 ;
     RECT  190.393 36.24 191.408 36.888 ;
     RECT  189.004 40.032 191.408 40.056 ;
     RECT  189.004 42.528 191.408 42.552 ;
     RECT  189.004 44.352 191.408 44.376 ;
     RECT  190.433 58.992 191.408 59.016 ;
     RECT  190.433 77.088 191.408 78.456 ;
     RECT  190.433 106.32 191.408 107.016 ;
     RECT  191.408 2.148 191.512 127.452 ;
     RECT  191.512 2.418 191.704 127.182 ;
     RECT  191.704 36.48 191.939 36.888 ;
     RECT  191.704 4.128 191.945 5.112 ;
     RECT  191.939 36.864 192.161 36.888 ;
     RECT  191.704 42.528 192.227 42.648 ;
     RECT  191.704 106.032 192.601 107.016 ;
     RECT  192.227 42.528 192.701 42.552 ;
     RECT  191.945 4.128 194.108 4.152 ;
     RECT  191.704 28.944 194.108 28.968 ;
     RECT  191.704 32.736 194.108 32.76 ;
     RECT  191.704 33.888 194.108 33.912 ;
     RECT  191.704 40.032 194.108 40.056 ;
     RECT  191.704 44.352 194.108 44.376 ;
     RECT  191.704 58.992 194.108 59.016 ;
     RECT  191.704 67.68 194.108 67.704 ;
     RECT  191.704 77.088 194.108 78.456 ;
     RECT  191.704 80.592 194.108 80.616 ;
     RECT  193.525 81.888 194.108 81.912 ;
     RECT  192.601 106.464 194.108 107.016 ;
     RECT  194.108 2.148 194.212 127.452 ;
     RECT  194.212 2.418 194.404 127.182 ;
     RECT  194.404 4.128 196.808 4.152 ;
     RECT  194.404 28.944 196.808 28.968 ;
     RECT  194.404 32.736 196.808 32.76 ;
     RECT  194.404 33.888 196.808 33.912 ;
     RECT  194.404 40.032 196.808 40.056 ;
     RECT  194.404 44.352 196.808 44.376 ;
     RECT  194.404 58.992 196.808 59.016 ;
     RECT  194.404 67.68 196.808 67.704 ;
     RECT  194.404 77.088 196.808 78.36 ;
     RECT  194.404 80.592 196.808 80.616 ;
     RECT  194.404 81.888 196.808 81.912 ;
     RECT  194.404 106.416 196.808 106.488 ;
     RECT  196.808 2.148 196.912 127.452 ;
     RECT  196.912 2.418 197.104 127.182 ;
     RECT  197.104 33.792 197.201 33.912 ;
     RECT  197.104 58.992 197.921 59.016 ;
     RECT  197.201 33.792 198.349 33.816 ;
     RECT  198.349 33.792 198.389 33.912 ;
     RECT  197.104 106.416 199.141 106.488 ;
     RECT  197.104 4.128 199.508 4.152 ;
     RECT  197.104 28.944 199.508 28.968 ;
     RECT  197.104 32.736 199.508 32.76 ;
     RECT  198.389 33.888 199.508 33.912 ;
     RECT  197.104 40.032 199.508 40.056 ;
     RECT  197.104 44.352 199.508 44.376 ;
     RECT  199.349 58.896 199.508 58.92 ;
     RECT  197.104 67.68 199.508 67.704 ;
     RECT  197.104 76.992 199.508 78.36 ;
     RECT  197.104 80.592 199.508 80.616 ;
     RECT  197.104 81.888 199.508 81.912 ;
     RECT  199.1 83.616 199.508 83.64 ;
     RECT  199.381 90.528 199.508 90.552 ;
     RECT  199.141 106.032 199.508 106.488 ;
     RECT  199.508 2.148 199.612 127.452 ;
     RECT  199.612 2.418 199.804 127.182 ;
     RECT  199.804 77.904 200.225 77.928 ;
     RECT  199.804 67.68 200.333 67.704 ;
     RECT  199.804 58.656 200.833 58.68 ;
     RECT  199.804 54.768 200.837 54.792 ;
     RECT  200.833 58.56 200.941 58.68 ;
     RECT  200.941 58.56 201.161 58.728 ;
     RECT  201.161 58.56 201.197 58.584 ;
     RECT  199.804 4.128 202.208 4.152 ;
     RECT  199.804 28.944 202.208 28.968 ;
     RECT  199.804 33.888 202.208 33.912 ;
     RECT  199.804 40.032 202.208 40.056 ;
     RECT  199.804 44.352 202.208 44.376 ;
     RECT  199.804 90.528 202.208 90.552 ;
     RECT  199.804 106.464 202.208 106.488 ;
     RECT  202.208 2.148 202.312 127.452 ;
     RECT  202.312 2.418 202.504 127.182 ;
     RECT  202.504 4.128 204.908 4.152 ;
     RECT  202.504 28.944 204.908 28.968 ;
     RECT  202.504 33.888 204.908 33.912 ;
     RECT  202.504 40.032 204.908 40.056 ;
     RECT  202.504 44.352 204.908 44.376 ;
     RECT  202.504 90.528 204.908 90.552 ;
     RECT  202.504 106.464 204.908 106.488 ;
     RECT  204.908 2.148 205.012 127.452 ;
     RECT  205.012 2.418 205.204 127.182 ;
     RECT  205.204 44.352 205.523 44.376 ;
     RECT  205.204 81.552 205.523 81.624 ;
     RECT  205.204 4.128 206.051 4.152 ;
     RECT  205.204 33.744 206.291 33.768 ;
     RECT  205.204 28.944 206.421 29.496 ;
     RECT  205.204 40.032 206.483 40.056 ;
     RECT  205.204 25.056 206.561 25.08 ;
     RECT  206.421 28.944 206.579 29.544 ;
     RECT  206.245 35.904 206.579 35.928 ;
     RECT  206.521 57.6 206.605 57.624 ;
     RECT  206.521 68.928 206.605 68.952 ;
     RECT  206.521 101.904 206.665 101.928 ;
     RECT  206.521 112.944 206.665 112.968 ;
     RECT  206.521 123.984 206.665 124.008 ;
     RECT  205.204 90.528 206.701 90.552 ;
     RECT  205.204 106.464 206.917 106.488 ;
     RECT  206.869 11.184 207.608 11.208 ;
     RECT  205.204 14.4 207.608 14.424 ;
     RECT  206.665 25.2 207.608 25.224 ;
     RECT  206.579 28.944 207.608 28.968 ;
     RECT  206.665 36.096 207.608 36.12 ;
     RECT  206.492 47.136 207.608 47.16 ;
     RECT  206.533 55.248 207.608 55.272 ;
     RECT  206.665 58.128 207.608 58.152 ;
     RECT  206.665 68.976 207.608 69 ;
     RECT  206.492 80.112 207.608 80.136 ;
     RECT  205.523 81.6 207.608 81.624 ;
     RECT  205.204 86.208 207.608 86.232 ;
     RECT  206.533 88.176 207.608 88.2 ;
     RECT  206.701 90.528 207.608 91.08 ;
     RECT  207.169 94.032 207.608 94.056 ;
     RECT  207.205 99.744 207.608 100.152 ;
     RECT  206.665 101.904 207.608 102.168 ;
     RECT  206.917 106.464 207.608 106.584 ;
     RECT  206.665 112.944 207.608 113.064 ;
     RECT  207.493 121.392 207.608 121.416 ;
     RECT  207.313 122.544 207.608 122.568 ;
     RECT  206.665 123.984 207.608 124.104 ;
     RECT  207.608 2.148 207.712 127.452 ;
     RECT  207.712 2.418 207.904 127.182 ;
     RECT  207.904 55.248 208.109 55.32 ;
     RECT  207.904 121.392 208.109 121.608 ;
     RECT  207.904 101.904 208.115 102.168 ;
     RECT  207.904 110.304 208.115 110.424 ;
     RECT  207.904 112.944 208.115 113.064 ;
     RECT  207.904 88.128 208.145 88.2 ;
     RECT  207.904 90.912 208.163 91.08 ;
     RECT  207.904 98.64 208.163 99.768 ;
     RECT  207.904 93.984 208.189 94.008 ;
     RECT  207.904 28.944 208.933 28.968 ;
     RECT  207.904 95.184 208.981 95.208 ;
     RECT  208.163 99.168 209.027 99.768 ;
     RECT  208.163 90.912 209.041 90.936 ;
     RECT  207.904 81.6 209.123 81.624 ;
     RECT  208.981 95.184 209.123 95.64 ;
     RECT  208.145 88.128 209.125 88.152 ;
     RECT  209.041 90.576 209.125 90.936 ;
     RECT  209.123 95.616 209.171 95.64 ;
     RECT  207.904 22.368 209.315 22.392 ;
     RECT  207.904 25.2 209.545 25.224 ;
     RECT  207.904 47.136 209.545 47.16 ;
     RECT  207.904 86.208 209.66 86.232 ;
     RECT  207.904 58.128 209.761 58.152 ;
     RECT  207.904 36.096 209.797 36.12 ;
     RECT  209.66 74.64 209.869 74.664 ;
     RECT  209.66 8.496 210.308 8.52 ;
     RECT  207.904 11.088 210.308 11.208 ;
     RECT  209.269 19.632 210.308 19.656 ;
     RECT  209.545 24.912 210.308 25.224 ;
     RECT  208.933 28.944 210.308 29.256 ;
     RECT  209.689 30.672 210.308 30.696 ;
     RECT  207.904 33.36 210.308 33.384 ;
     RECT  209.797 36.096 210.308 36.312 ;
     RECT  209.701 41.328 210.308 41.352 ;
     RECT  207.904 44.4 210.308 44.424 ;
     RECT  209.545 47.088 210.308 47.16 ;
     RECT  209.689 52.464 210.308 52.488 ;
     RECT  208.109 55.296 210.308 55.32 ;
     RECT  209.761 57.936 210.308 58.152 ;
     RECT  209.689 63.792 210.308 63.816 ;
     RECT  207.904 66.192 210.308 66.36 ;
     RECT  207.904 68.976 210.308 69 ;
     RECT  209.869 74.64 210.308 74.712 ;
     RECT  207.904 77.424 210.308 77.592 ;
     RECT  207.904 80.112 210.308 80.136 ;
     RECT  209.66 85.392 210.308 86.232 ;
     RECT  209.125 88.128 210.308 88.2 ;
     RECT  209.125 90.912 210.308 90.936 ;
     RECT  209.66 96.576 210.308 96.6 ;
     RECT  209.027 99.168 210.308 99.192 ;
     RECT  208.115 102.144 210.308 102.168 ;
     RECT  209.701 107.712 210.308 107.736 ;
     RECT  208.115 110.4 210.308 110.424 ;
     RECT  208.115 113.04 210.308 113.064 ;
     RECT  209.681 118.56 210.308 118.584 ;
     RECT  208.109 121.584 210.308 121.608 ;
     RECT  207.904 124.08 210.308 124.104 ;
     RECT  210.308 2.148 210.412 127.452 ;
     RECT  210.412 2.418 210.604 127.182 ;
     RECT  210.604 88.128 210.665 88.344 ;
     RECT  210.604 99.168 210.665 99.192 ;
     RECT  210.604 121.584 210.665 121.608 ;
     RECT  210.604 8.496 210.755 8.52 ;
     RECT  210.604 11.184 210.755 11.208 ;
     RECT  210.604 77.472 210.845 77.592 ;
     RECT  210.604 66.336 211.097 66.504 ;
     RECT  210.604 27.696 211.133 29.256 ;
     RECT  210.604 124.08 211.205 124.248 ;
     RECT  210.604 60.72 211.283 60.744 ;
     RECT  210.665 88.176 211.349 88.344 ;
     RECT  210.604 104.832 211.393 104.952 ;
     RECT  210.604 115.152 211.393 115.176 ;
     RECT  210.604 82.656 211.42 82.872 ;
     RECT  210.604 30.672 211.427 30.696 ;
     RECT  210.604 38.64 211.427 38.664 ;
     RECT  210.604 49.584 211.427 49.608 ;
     RECT  210.604 71.712 211.427 71.736 ;
     RECT  210.604 93.696 211.427 93.72 ;
     RECT  211.393 104.832 211.427 104.856 ;
     RECT  211.42 82.656 211.429 82.68 ;
     RECT  211.133 27.696 211.457 28.44 ;
     RECT  211.457 28.416 211.468 28.44 ;
     RECT  210.604 6.096 211.475 6.168 ;
     RECT  210.604 16.8 211.475 16.824 ;
     RECT  210.604 85.44 211.601 85.512 ;
     RECT  211.349 88.224 211.673 88.344 ;
     RECT  210.604 74.688 211.705 74.712 ;
     RECT  210.604 41.616 211.741 41.64 ;
     RECT  211.705 74.64 211.853 74.712 ;
     RECT  211.741 41.472 211.925 41.64 ;
     RECT  211.475 6.096 213.008 6.12 ;
     RECT  210.604 24.912 213.008 24.936 ;
     RECT  210.604 36.288 213.008 36.312 ;
     RECT  211.925 41.472 213.008 41.496 ;
     RECT  210.604 47.088 213.008 47.112 ;
     RECT  210.604 55.248 213.008 55.272 ;
     RECT  210.604 57.936 213.008 57.96 ;
     RECT  211.097 66.48 213.008 66.504 ;
     RECT  210.604 68.928 213.008 68.952 ;
     RECT  211.853 74.64 213.008 74.664 ;
     RECT  210.845 77.472 213.008 77.496 ;
     RECT  210.604 80.16 213.008 80.184 ;
     RECT  211.601 85.44 213.008 85.464 ;
     RECT  211.673 88.32 213.008 88.344 ;
     RECT  210.604 90.96 213.008 90.984 ;
     RECT  211.633 99.168 213.008 99.192 ;
     RECT  210.604 102 213.008 102.024 ;
     RECT  210.604 110.4 213.008 110.424 ;
     RECT  210.604 113.184 213.008 113.208 ;
     RECT  211.633 121.392 213.008 121.416 ;
     RECT  211.205 124.224 213.008 124.248 ;
     RECT  213.008 2.148 213.112 127.452 ;
     RECT  213.112 2.418 213.304 127.182 ;
     RECT  213.304 74.64 213.365 74.664 ;
     RECT  213.304 41.472 213.545 41.496 ;
     RECT  213.304 66.192 213.545 66.504 ;
     RECT  214.873 5.712 215.82 5.736 ;
     RECT  214.333 8.448 215.82 8.472 ;
     RECT  214.333 11.184 215.82 11.208 ;
     RECT  214.333 13.968 215.82 13.992 ;
     RECT  214.333 16.704 215.82 16.728 ;
     RECT  213.304 19.44 215.82 19.464 ;
     RECT  214.873 22.224 215.82 22.248 ;
     RECT  213.304 24.96 215.82 24.984 ;
     RECT  214.333 27.696 215.82 27.72 ;
     RECT  214.333 30.432 215.82 30.456 ;
     RECT  213.304 33.216 215.82 33.24 ;
     RECT  213.304 35.952 215.82 35.976 ;
     RECT  214.333 38.688 215.82 38.712 ;
     RECT  214.297 41.424 215.82 41.448 ;
     RECT  214.333 44.208 215.82 44.232 ;
     RECT  214.333 46.944 215.82 46.968 ;
     RECT  214.333 49.68 215.82 49.704 ;
     RECT  214.333 52.464 215.82 52.488 ;
     RECT  214.333 55.2 215.82 55.224 ;
     RECT  214.297 57.936 215.82 57.96 ;
     RECT  213.304 60.672 215.82 60.696 ;
     RECT  213.304 63.456 215.82 63.48 ;
     RECT  213.545 66.192 215.82 66.216 ;
     RECT  213.304 68.928 215.82 68.952 ;
     RECT  214.333 71.664 215.82 71.688 ;
     RECT  214.333 74.448 215.82 74.472 ;
     RECT  214.333 77.184 215.82 77.208 ;
     RECT  213.304 79.92 215.82 79.944 ;
     RECT  214.333 82.704 215.82 82.728 ;
     RECT  214.333 85.44 215.82 85.464 ;
     RECT  214.333 88.176 215.82 88.2 ;
     RECT  213.304 90.912 215.82 90.936 ;
     RECT  213.304 93.696 215.82 93.72 ;
     RECT  214.333 96.432 215.82 96.456 ;
     RECT  214.873 99.168 215.82 99.192 ;
     RECT  214.297 101.904 215.82 101.928 ;
     RECT  214.333 104.688 215.82 104.712 ;
     RECT  214.297 107.424 215.82 107.448 ;
     RECT  213.304 110.16 215.82 110.184 ;
     RECT  214.297 112.944 215.82 112.968 ;
     RECT  214.333 115.68 215.82 115.704 ;
     RECT  214.297 118.416 215.82 118.44 ;
     RECT  213.304 121.152 215.82 121.176 ;
     RECT  213.304 123.936 215.82 123.96 ;
    LAYER M5 ;
     RECT  149.472 0.144 149.496 0.227 ;
     RECT  66.528 0.144 66.552 1.763 ;
     RECT  65.376 0.133 65.4 2.137 ;
     RECT  2.4 2.137 2.52 2.151 ;
     RECT  5.1 2.137 5.22 2.151 ;
     RECT  7.8 2.137 7.92 2.151 ;
     RECT  10.5 2.137 10.62 2.151 ;
     RECT  13.2 2.137 13.32 2.151 ;
     RECT  15.9 2.137 16.02 2.151 ;
     RECT  18.6 2.137 18.72 2.151 ;
     RECT  21.3 2.137 21.42 2.151 ;
     RECT  24 2.137 24.12 2.151 ;
     RECT  26.7 2.137 26.82 2.151 ;
     RECT  29.4 2.137 29.52 2.151 ;
     RECT  32.1 2.137 32.22 2.151 ;
     RECT  34.8 2.137 34.92 2.151 ;
     RECT  37.5 2.137 37.62 2.151 ;
     RECT  40.2 2.137 40.32 2.151 ;
     RECT  42.9 2.137 43.02 2.151 ;
     RECT  45.6 2.137 45.72 2.151 ;
     RECT  48.3 2.137 48.42 2.151 ;
     RECT  51 2.137 51.12 2.151 ;
     RECT  53.7 2.137 53.82 2.151 ;
     RECT  56.4 2.137 56.52 2.151 ;
     RECT  59.1 2.137 59.22 2.151 ;
     RECT  61.8 2.137 61.92 2.151 ;
     RECT  67.2 2.137 67.32 2.151 ;
     RECT  69.9 2.137 70.02 2.151 ;
     RECT  72.6 2.137 72.72 2.151 ;
     RECT  75.3 2.137 75.42 2.151 ;
     RECT  78 2.137 78.12 2.151 ;
     RECT  80.7 2.137 80.82 2.151 ;
     RECT  83.4 2.137 83.52 2.151 ;
     RECT  86.1 2.137 86.22 2.151 ;
     RECT  88.8 2.137 88.92 2.151 ;
     RECT  91.5 2.137 91.62 2.151 ;
     RECT  94.2 2.137 94.32 2.151 ;
     RECT  96.9 2.137 97.02 2.151 ;
     RECT  99.6 2.137 99.72 2.151 ;
     RECT  102.3 2.137 102.42 2.151 ;
     RECT  105 2.137 105.12 2.151 ;
     RECT  107.7 2.137 107.82 2.151 ;
     RECT  110.4 2.137 110.52 2.151 ;
     RECT  113.1 2.137 113.22 2.151 ;
     RECT  115.8 2.137 115.92 2.151 ;
     RECT  118.5 2.137 118.62 2.151 ;
     RECT  121.2 2.137 121.32 2.151 ;
     RECT  123.9 2.137 124.02 2.151 ;
     RECT  126.6 2.137 126.72 2.151 ;
     RECT  129.3 2.137 129.42 2.151 ;
     RECT  132 2.137 132.12 2.151 ;
     RECT  134.7 2.137 134.82 2.151 ;
     RECT  137.4 2.137 137.52 2.151 ;
     RECT  140.1 2.137 140.22 2.151 ;
     RECT  142.8 2.137 142.92 2.151 ;
     RECT  145.5 2.137 145.62 2.151 ;
     RECT  148.2 2.137 148.32 2.151 ;
     RECT  150.9 2.137 151.02 2.151 ;
     RECT  153.6 2.137 153.72 2.151 ;
     RECT  156.3 2.137 156.42 2.151 ;
     RECT  159 2.137 159.12 2.151 ;
     RECT  161.7 2.137 161.82 2.151 ;
     RECT  164.4 2.137 164.52 2.151 ;
     RECT  167.1 2.137 167.22 2.151 ;
     RECT  169.8 2.137 169.92 2.151 ;
     RECT  172.5 2.137 172.62 2.151 ;
     RECT  175.2 2.137 175.32 2.151 ;
     RECT  177.9 2.137 178.02 2.151 ;
     RECT  180.6 2.137 180.72 2.151 ;
     RECT  183.3 2.137 183.42 2.151 ;
     RECT  186 2.137 186.12 2.151 ;
     RECT  188.7 2.137 188.82 2.151 ;
     RECT  191.4 2.137 191.52 2.151 ;
     RECT  194.1 2.137 194.22 2.151 ;
     RECT  196.8 2.137 196.92 2.151 ;
     RECT  199.5 2.137 199.62 2.151 ;
     RECT  202.2 2.137 202.32 2.151 ;
     RECT  204.9 2.137 205.02 2.151 ;
     RECT  207.6 2.137 207.72 2.151 ;
     RECT  210.3 2.137 210.42 2.151 ;
     RECT  213 2.137 213.12 2.151 ;
     RECT  67.2 2.151 67.512 3.685 ;
     RECT  26.7 2.151 27.012 3.733 ;
     RECT  26.448 3.733 27.012 3.925 ;
     RECT  204.9 2.151 205.212 4.117 ;
     RECT  29.4 2.151 29.712 5.077 ;
     RECT  191.4 2.151 191.712 5.077 ;
     RECT  28.56 5.077 29.712 5.653 ;
     RECT  2.4 2.151 2.712 5.893 ;
     RECT  210.3 2.151 210.612 6.085 ;
     RECT  210.3 6.085 210.744 6.133 ;
     RECT  2.4 5.893 3.48 6.229 ;
     RECT  5.1 2.151 5.412 8.341 ;
     RECT  210.3 6.133 211.464 8.485 ;
     RECT  204.9 4.117 206.04 11.173 ;
     RECT  207.6 2.151 207.912 11.173 ;
     RECT  7.8 2.151 8.112 11.221 ;
     RECT  204.9 11.173 207.912 14.435 ;
     RECT  4.848 8.341 5.412 16.501 ;
     RECT  209.712 8.485 211.464 16.835 ;
     RECT  4.848 16.501 5.688 17.699 ;
     RECT  7.344 11.221 8.112 18.085 ;
     RECT  209.712 16.835 211.368 19.621 ;
     RECT  209.28 19.621 211.368 19.667 ;
     RECT  2.4 6.229 3.816 22.499 ;
     RECT  69.9 2.151 70.212 22.741 ;
     RECT  7.248 18.085 8.112 23.317 ;
     RECT  9.216 16.069 9.24 23.317 ;
     RECT  3.792 22.499 3.816 26.291 ;
     RECT  210.3 19.667 211.368 28.405 ;
     RECT  191.4 5.077 191.928 28.933 ;
     RECT  4.992 17.699 5.688 28.979 ;
     RECT  204.9 14.435 206.568 29.555 ;
     RECT  0.192 30.757 0.216 30.899 ;
     RECT  69.792 22.741 70.212 31.379 ;
     RECT  5.1 28.979 5.688 31.621 ;
     RECT  7.248 23.317 9.24 31.621 ;
     RECT  21.3 2.151 21.612 32.197 ;
     RECT  5.1 31.621 9.24 32.245 ;
     RECT  10.5 2.151 10.812 32.245 ;
     RECT  26.448 3.925 27.144 32.293 ;
     RECT  28.56 5.653 29.88 32.293 ;
     RECT  26.448 32.293 27.384 32.387 ;
     RECT  199.5 2.151 199.812 32.725 ;
     RECT  28.56 32.293 30.648 33.107 ;
     RECT  209.28 19.667 209.304 33.349 ;
     RECT  210.3 28.405 211.416 33.349 ;
     RECT  209.28 33.349 211.416 33.395 ;
     RECT  24 2.151 24.312 33.589 ;
     RECT  5.1 32.245 10.812 33.683 ;
     RECT  204.9 29.555 206.472 33.779 ;
     RECT  26.544 32.387 27.384 33.781 ;
     RECT  66.672 3.685 67.512 33.781 ;
     RECT  172.5 2.151 172.812 33.781 ;
     RECT  18.6 2.151 18.912 34.069 ;
     RECT  3.744 26.629 3.768 34.117 ;
     RECT  5.1 33.683 8.232 34.117 ;
     RECT  21.3 32.197 22.056 34.117 ;
     RECT  64.5 2.137 65.4 34.117 ;
     RECT  66.384 33.781 67.512 34.117 ;
     RECT  15.9 2.151 16.212 34.165 ;
     RECT  24 33.589 24.888 34.213 ;
     RECT  3.744 34.117 8.232 34.403 ;
     RECT  102.3 2.151 102.612 34.693 ;
     RECT  32.1 2.151 32.412 34.741 ;
     RECT  15.9 34.165 16.728 34.835 ;
     RECT  26.544 33.781 27.624 34.837 ;
     RECT  18.6 34.069 19.368 34.933 ;
     RECT  9.216 33.683 10.812 34.981 ;
     RECT  23.904 34.213 24.888 35.075 ;
     RECT  9.216 34.981 11.256 35.315 ;
     RECT  13.2 2.151 13.512 35.317 ;
     RECT  20.976 34.117 22.056 35.317 ;
     RECT  3.744 34.403 6.456 35.411 ;
     RECT  20.976 35.317 22.248 35.411 ;
     RECT  25.92 34.837 27.624 35.411 ;
     RECT  18.432 34.933 19.368 35.413 ;
     RECT  29.04 33.107 30.648 35.845 ;
     RECT  31.92 34.741 32.412 35.845 ;
     RECT  206.256 33.779 206.472 35.893 ;
     RECT  206.256 35.893 206.568 35.939 ;
     RECT  64.5 34.117 67.512 35.987 ;
     RECT  61.8 2.151 62.112 36.229 ;
     RECT  23.904 35.075 24.504 36.275 ;
     RECT  191.28 28.933 191.928 36.275 ;
     RECT  69.9 31.379 70.212 36.421 ;
     RECT  64.5 35.987 65.448 36.467 ;
     RECT  27.984 35.605 28.008 36.469 ;
     RECT  29.04 35.845 30.84 36.469 ;
     RECT  21.3 35.411 22.248 36.515 ;
     RECT  25.92 35.411 27.012 36.515 ;
     RECT  191.4 36.275 191.928 36.515 ;
     RECT  13.056 35.317 13.512 36.517 ;
     RECT  15.9 34.835 16.212 36.517 ;
     RECT  18.432 35.413 19.992 36.659 ;
     RECT  121.2 2.151 121.512 36.757 ;
     RECT  27.984 36.469 30.84 36.899 ;
     RECT  12.96 36.517 13.512 36.901 ;
     RECT  34.8 2.151 35.112 36.901 ;
     RECT  9.504 35.315 11.256 36.947 ;
     RECT  121.2 36.757 121.992 36.947 ;
     RECT  15.9 36.517 16.44 36.997 ;
     RECT  115.8 2.151 116.112 36.997 ;
     RECT  53.7 2.151 54.012 37.381 ;
     RECT  61.536 36.229 62.112 37.429 ;
     RECT  26.7 36.515 27.012 37.573 ;
     RECT  38.88 37.429 38.904 37.573 ;
     RECT  40.2 2.151 40.512 37.573 ;
     RECT  42.9 2.151 43.212 37.573 ;
     RECT  45.6 2.151 45.912 37.573 ;
     RECT  67.2 35.987 67.512 37.573 ;
     RECT  75.3 2.151 75.612 37.573 ;
     RECT  18.6 36.659 19.992 37.717 ;
     RECT  21.3 36.515 21.612 37.717 ;
     RECT  75.168 37.573 75.612 37.861 ;
     RECT  9.504 36.947 10.812 37.907 ;
     RECT  15.312 36.997 16.44 37.907 ;
     RECT  18.6 37.717 21.612 37.907 ;
     RECT  21.12 37.907 21.612 37.955 ;
     RECT  67.2 37.573 67.608 37.957 ;
     RECT  121.2 36.947 121.608 38.003 ;
     RECT  64.5 36.467 65.4 38.005 ;
     RECT  66.72 37.957 67.608 38.005 ;
     RECT  34.272 36.901 35.112 38.149 ;
     RECT  55.2 37.573 55.224 38.149 ;
     RECT  83.4 2.151 83.712 38.149 ;
     RECT  7.68 34.403 8.232 38.197 ;
     RECT  9.504 37.907 9.528 38.197 ;
     RECT  7.68 38.197 9.528 38.243 ;
     RECT  64.5 38.005 67.608 38.243 ;
     RECT  10.5 37.907 10.812 38.389 ;
     RECT  76.944 37.909 76.968 38.389 ;
     RECT  78 2.151 78.312 38.389 ;
     RECT  52.896 37.381 54.012 38.435 ;
     RECT  76.944 38.389 78.312 38.435 ;
     RECT  48.3 2.151 48.612 38.437 ;
     RECT  169.8 2.151 170.112 38.437 ;
     RECT  63.168 36.997 63.192 38.483 ;
     RECT  149.568 3.925 149.592 38.483 ;
     RECT  5.1 35.411 6.456 38.629 ;
     RECT  7.68 38.243 9.384 38.629 ;
     RECT  5.1 38.629 9.384 38.675 ;
     RECT  18.6 37.907 19.992 38.723 ;
     RECT  172.5 33.781 172.92 38.723 ;
     RECT  5.1 38.675 5.544 38.725 ;
     RECT  31.92 35.845 33.24 38.725 ;
     RECT  126.6 2.151 126.912 38.725 ;
     RECT  15.9 37.907 16.44 38.771 ;
     RECT  38.88 37.573 40.512 38.773 ;
     RECT  24 36.275 24.504 38.819 ;
     RECT  45.6 37.573 46.2 38.819 ;
     RECT  102.144 34.693 102.612 38.819 ;
     RECT  75.168 37.861 75.864 38.869 ;
     RECT  115.8 36.997 116.76 39.013 ;
     RECT  42.768 37.573 43.212 39.061 ;
     RECT  44.448 38.725 44.472 39.061 ;
     RECT  66.144 38.243 67.608 39.061 ;
     RECT  61.152 37.429 62.112 39.109 ;
     RECT  37.5 2.151 37.812 39.253 ;
     RECT  34.272 38.149 35.544 39.299 ;
     RECT  31.92 38.725 33.288 39.539 ;
     RECT  64.5 38.243 65.016 39.539 ;
     RECT  75.168 38.869 76.152 39.539 ;
     RECT  34.368 39.299 35.544 39.589 ;
     RECT  48.3 38.437 48.984 39.635 ;
     RECT  55.2 38.149 55.272 39.731 ;
     RECT  77.184 38.435 78.312 39.731 ;
     RECT  94.2 2.151 94.512 39.733 ;
     RECT  115.152 39.013 116.76 39.779 ;
     RECT  56.4 2.151 56.712 39.781 ;
     RECT  55.248 39.731 55.272 39.827 ;
     RECT  37.008 39.253 37.812 39.877 ;
     RECT  38.88 38.773 41.016 39.877 ;
     RECT  99.6 2.151 99.912 39.877 ;
     RECT  159 2.151 159.312 39.877 ;
     RECT  37.008 39.877 41.016 39.923 ;
     RECT  61.008 39.109 62.112 39.923 ;
     RECT  25.92 37.573 27.012 40.067 ;
     RECT  42.768 39.061 44.472 40.067 ;
     RECT  206.448 35.939 206.568 40.067 ;
     RECT  51 2.151 51.312 40.117 ;
     RECT  66.144 39.061 68.328 40.163 ;
     RECT  69.9 36.421 70.68 40.163 ;
     RECT  4.848 38.725 5.544 40.259 ;
     RECT  12.576 36.901 13.512 40.307 ;
     RECT  12.816 40.307 13.512 40.499 ;
     RECT  47.28 38.533 47.304 40.499 ;
     RECT  56.4 39.781 56.808 40.499 ;
     RECT  6.816 38.675 9.384 40.547 ;
     RECT  51 40.117 51.432 40.547 ;
     RECT  10.5 38.389 11.208 40.595 ;
     RECT  66.96 40.163 68.328 40.691 ;
     RECT  102.192 38.819 102.612 40.693 ;
     RECT  101.328 40.693 102.612 40.933 ;
     RECT  27.984 36.899 30.6 40.981 ;
     RECT  32.1 39.539 33.288 40.981 ;
     RECT  126.48 38.725 126.912 40.981 ;
     RECT  123.9 2.151 124.212 41.173 ;
     RECT  34.368 39.589 35.976 41.269 ;
     RECT  37.008 39.923 40.512 41.269 ;
     RECT  34.368 41.269 40.512 41.315 ;
     RECT  44.448 40.067 44.472 41.411 ;
     RECT  27.984 40.981 33.288 41.651 ;
     RECT  80.7 2.151 81.012 41.749 ;
     RECT  4.848 40.259 5.412 41.893 ;
     RECT  121.2 38.003 121.512 41.893 ;
     RECT  123.696 41.173 124.212 41.893 ;
     RECT  125.328 40.981 126.912 41.893 ;
     RECT  22.8 41.749 22.824 41.939 ;
     RECT  123.696 41.893 126.912 41.939 ;
     RECT  6.816 40.547 8.616 41.989 ;
     RECT  24 38.819 24.312 41.989 ;
     RECT  75.3 39.539 76.152 42.083 ;
     RECT  99.6 39.877 100.008 42.085 ;
     RECT  115.44 39.779 116.76 42.133 ;
     RECT  99.504 42.085 100.008 42.229 ;
     RECT  101.328 40.933 103.272 42.229 ;
     RECT  107.7 2.151 108.012 42.229 ;
     RECT  120.912 41.893 121.512 42.277 ;
     RECT  122.496 41.557 122.52 42.277 ;
     RECT  99.504 42.229 103.272 42.371 ;
     RECT  66.96 40.691 67.512 42.421 ;
     RECT  101.328 42.371 103.272 42.421 ;
     RECT  167.1 2.151 167.412 42.421 ;
     RECT  158.736 39.877 159.312 42.467 ;
     RECT  36.144 41.315 40.512 42.469 ;
     RECT  115.44 42.133 117.24 42.515 ;
     RECT  18.6 38.723 18.912 42.517 ;
     RECT  19.968 38.723 19.992 42.517 ;
     RECT  34.368 41.315 35.112 42.517 ;
     RECT  36.144 42.469 41.016 42.517 ;
     RECT  66.72 42.421 67.512 42.563 ;
     RECT  191.4 36.515 191.712 42.613 ;
     RECT  113.1 2.151 113.412 42.661 ;
     RECT  6.816 41.989 9.048 42.757 ;
     RECT  80.7 41.749 81.336 42.757 ;
     RECT  6.672 42.757 9.048 42.803 ;
     RECT  34.368 42.517 41.016 42.803 ;
     RECT  110.4 2.151 110.712 42.853 ;
     RECT  29.4 41.651 33.288 42.899 ;
     RECT  101.328 42.421 103.752 42.995 ;
     RECT  83.04 38.149 83.712 43.043 ;
     RECT  123.792 41.939 126.912 43.043 ;
     RECT  105 2.151 105.312 43.285 ;
     RECT  120.912 42.277 122.52 43.333 ;
     RECT  27.984 41.651 28.008 43.379 ;
     RECT  34.368 42.803 36.168 43.379 ;
     RECT  107.7 42.229 108.408 43.477 ;
     RECT  83.232 43.043 83.712 43.571 ;
     RECT  94.08 39.733 94.512 43.571 ;
     RECT  119.808 42.181 119.832 43.571 ;
     RECT  118.5 2.151 118.812 43.669 ;
     RECT  31.872 42.899 33.288 43.907 ;
     RECT  105 43.285 106.056 43.955 ;
     RECT  120.816 43.333 122.52 43.955 ;
     RECT  123.792 43.043 124.212 44.149 ;
     RECT  125.28 43.043 126.912 44.149 ;
     RECT  115.44 42.515 116.112 44.341 ;
     RECT  204.9 33.779 205.212 44.341 ;
     RECT  169.8 38.437 170.232 44.387 ;
     RECT  36.144 43.379 36.168 44.437 ;
     RECT  120.912 43.955 122.52 44.437 ;
     RECT  123.792 44.149 126.912 44.437 ;
     RECT  109.68 42.853 110.712 44.483 ;
     RECT  117.216 42.515 117.24 44.483 ;
     RECT  120.912 44.437 126.912 44.483 ;
     RECT  101.424 42.995 103.752 44.531 ;
     RECT  29.4 42.899 30.552 44.579 ;
     RECT  115.44 44.341 116.232 44.581 ;
     RECT  36.144 44.437 36.504 44.869 ;
     RECT  37.5 42.803 41.016 44.869 ;
     RECT  107.7 43.477 108.552 44.869 ;
     RECT  120.912 44.483 121.848 45.011 ;
     RECT  31.872 43.907 33.144 45.059 ;
     RECT  121.104 45.011 121.848 45.059 ;
     RECT  34.368 43.379 35.112 45.155 ;
     RECT  122.928 44.483 126.912 45.155 ;
     RECT  126.192 45.155 126.912 45.443 ;
     RECT  112.368 42.661 113.412 45.491 ;
     RECT  3.744 35.411 3.768 45.541 ;
     RECT  4.848 41.893 5.64 45.541 ;
     RECT  32.1 45.059 33.144 45.635 ;
     RECT  106.752 44.869 108.552 45.635 ;
     RECT  115.44 44.581 116.808 45.635 ;
     RECT  80.7 42.757 81.384 45.731 ;
     RECT  24 41.989 24.408 45.925 ;
     RECT  121.104 45.059 121.512 46.019 ;
     RECT  23.904 45.925 24.408 46.067 ;
     RECT  101.424 44.531 103.224 46.211 ;
     RECT  115.8 45.635 116.808 46.211 ;
     RECT  3.744 45.541 5.64 46.259 ;
     RECT  36.144 44.869 41.016 46.499 ;
     RECT  115.8 46.211 116.232 46.645 ;
     RECT  122.928 45.155 125.112 46.739 ;
     RECT  18.6 42.517 19.992 46.787 ;
     RECT  36.144 46.499 36.168 46.787 ;
     RECT  102.3 46.211 103.224 46.835 ;
     RECT  114.816 46.645 116.232 46.835 ;
     RECT  123.792 46.739 125.112 46.835 ;
     RECT  28.128 43.861 28.152 46.837 ;
     RECT  126.6 45.443 126.912 46.885 ;
     RECT  123.792 46.835 124.824 47.027 ;
     RECT  3.936 46.259 5.64 47.269 ;
     RECT  37.5 46.499 41.016 47.363 ;
     RECT  106.752 45.635 108.012 47.363 ;
     RECT  118.5 43.669 119.112 47.699 ;
     RECT  37.5 47.363 40.512 47.891 ;
     RECT  109.968 44.483 110.712 47.891 ;
     RECT  38.88 47.891 40.512 47.939 ;
     RECT  126.192 46.885 126.912 47.939 ;
     RECT  114.816 46.835 116.112 47.987 ;
     RECT  123.792 47.027 124.392 48.275 ;
     RECT  123.9 48.275 124.392 48.659 ;
     RECT  209.712 33.395 211.416 49.619 ;
     RECT  6.672 42.803 6.696 50.771 ;
     RECT  7.8 42.803 9.048 50.965 ;
     RECT  209.712 49.619 210.612 52.499 ;
     RECT  7.8 50.965 9.096 53.075 ;
     RECT  28.08 46.837 28.152 55.331 ;
     RECT  3.744 47.269 5.64 55.907 ;
     RECT  206.544 40.067 206.568 57.635 ;
     RECT  167.1 42.421 167.832 58.787 ;
     RECT  15.9 38.771 16.212 59.173 ;
     RECT  19.968 46.787 19.992 59.891 ;
     RECT  210.3 52.499 210.612 60.709 ;
     RECT  210.3 60.709 211.272 63.781 ;
     RECT  2.4 22.499 2.712 66.757 ;
     RECT  3.936 55.907 5.64 66.757 ;
     RECT  2.4 66.757 5.64 66.803 ;
     RECT  99.504 42.371 100.2 67.283 ;
     RECT  191.4 42.613 192.216 67.715 ;
     RECT  80.7 45.731 81.336 68.147 ;
     RECT  6.624 55.381 6.648 68.773 ;
     RECT  7.8 53.075 9.048 69.011 ;
     RECT  6.432 68.773 6.648 70.933 ;
     RECT  7.8 69.011 8.232 70.933 ;
     RECT  209.712 63.781 211.272 71.701 ;
     RECT  6.432 70.933 8.232 76.309 ;
     RECT  102.3 46.835 102.612 76.885 ;
     RECT  186 2.151 186.312 77.077 ;
     RECT  24 46.067 24.408 77.315 ;
     RECT  99.504 67.283 99.912 77.461 ;
     RECT  188.7 2.151 189.012 77.893 ;
     RECT  101.376 76.885 102.936 77.941 ;
     RECT  101.376 77.941 103.368 80.101 ;
     RECT  101.376 80.101 103.8 80.341 ;
     RECT  191.4 67.715 191.712 80.581 ;
     RECT  6.432 76.309 8.376 80.963 ;
     RECT  209.712 71.701 211.416 81.589 ;
     RECT  101.376 80.341 103.944 81.733 ;
     RECT  105 43.955 105.312 81.733 ;
     RECT  194.1 2.151 194.412 81.877 ;
     RECT  24 77.315 24.312 82.645 ;
     RECT  28.08 55.331 28.104 82.691 ;
     RECT  209.088 81.589 211.416 82.691 ;
     RECT  23.904 82.645 24.312 82.787 ;
     RECT  199.392 32.725 199.812 83.605 ;
     RECT  204.9 44.341 205.512 86.243 ;
     RECT  2.4 66.803 5.412 86.627 ;
     RECT  206.544 68.917 206.568 88.165 ;
     RECT  207.6 14.435 207.912 88.165 ;
     RECT  206.544 88.165 207.912 88.211 ;
     RECT  209.088 82.691 211.368 88.213 ;
     RECT  6.48 80.963 8.376 88.789 ;
     RECT  14.976 59.173 16.212 90.659 ;
     RECT  206.88 88.211 207.912 91.045 ;
     RECT  209.088 88.213 211.416 91.045 ;
     RECT  206.88 91.045 211.416 91.091 ;
     RECT  10.5 40.595 10.812 93.445 ;
     RECT  80.7 68.147 81.012 93.589 ;
     RECT  207.6 91.091 211.416 94.021 ;
     RECT  80.7 93.589 81.288 97.909 ;
     RECT  207.216 94.021 211.416 99.779 ;
     RECT  207.216 99.779 208.104 100.163 ;
     RECT  6.432 88.789 8.376 100.787 ;
     RECT  209.712 99.779 211.416 104.867 ;
     RECT  188.592 77.893 189.012 106.067 ;
     RECT  190.128 78.421 190.152 106.067 ;
     RECT  191.4 80.581 192.552 106.067 ;
     RECT  199.152 83.605 199.812 106.067 ;
     RECT  101.376 81.733 105.312 106.307 ;
     RECT  24 82.787 24.312 106.405 ;
     RECT  80.7 97.909 81.336 106.451 ;
     RECT  114.528 106.357 114.552 106.499 ;
     RECT  23.904 106.405 24.312 106.547 ;
     RECT  193.536 81.877 194.412 106.643 ;
     RECT  9.792 93.445 10.812 107.027 ;
     RECT  80.7 106.451 81.288 107.027 ;
     RECT  103.92 106.307 105.312 107.027 ;
     RECT  101.376 106.307 102.936 107.219 ;
     RECT  103.92 107.027 103.944 107.219 ;
     RECT  185.904 77.077 186.312 107.219 ;
     RECT  187.584 77.269 187.608 107.219 ;
     RECT  101.376 107.219 102.612 107.315 ;
     RECT  99.408 77.461 99.912 107.363 ;
     RECT  6.48 100.787 8.376 107.411 ;
     RECT  6.48 107.411 8.232 107.555 ;
     RECT  6.48 107.555 6.648 111.779 ;
     RECT  207.36 100.163 208.104 112.979 ;
     RECT  7.8 107.555 8.232 114.035 ;
     RECT  209.712 104.867 211.368 115.187 ;
     RECT  3.936 86.627 5.412 116.963 ;
     RECT  4.512 116.963 5.412 118.595 ;
     RECT  209.712 115.187 210.612 118.595 ;
     RECT  6.624 111.779 6.648 121.475 ;
     RECT  7.8 114.035 8.112 121.957 ;
     RECT  207.36 112.979 207.912 122.579 ;
     RECT  4.752 118.595 5.412 122.675 ;
     RECT  7.44 121.957 8.112 123.779 ;
     RECT  207.504 122.579 207.912 124.019 ;
     RECT  2.4 86.627 2.712 127.449 ;
     RECT  5.1 122.675 5.412 127.449 ;
     RECT  7.8 123.779 8.112 127.449 ;
     RECT  10.5 107.027 10.812 127.449 ;
     RECT  13.2 40.499 13.512 127.449 ;
     RECT  15.9 90.659 16.212 127.449 ;
     RECT  18.6 46.787 18.912 127.449 ;
     RECT  21.3 37.955 21.612 127.449 ;
     RECT  24 106.547 24.312 127.449 ;
     RECT  26.7 40.067 27.012 127.449 ;
     RECT  29.4 44.579 29.712 127.449 ;
     RECT  32.1 45.635 32.412 127.449 ;
     RECT  34.8 45.155 35.112 127.449 ;
     RECT  37.5 47.891 37.812 127.449 ;
     RECT  40.2 47.939 40.512 127.449 ;
     RECT  42.9 40.067 43.212 127.449 ;
     RECT  45.6 38.819 45.912 127.449 ;
     RECT  48.3 39.635 48.612 127.449 ;
     RECT  51 40.547 51.312 127.449 ;
     RECT  53.7 38.435 54.012 127.449 ;
     RECT  56.4 40.499 56.712 127.449 ;
     RECT  59.1 2.151 59.412 127.449 ;
     RECT  61.8 39.923 62.112 127.449 ;
     RECT  64.5 39.539 64.812 127.449 ;
     RECT  67.2 42.563 67.512 127.449 ;
     RECT  69.9 40.163 70.212 127.449 ;
     RECT  72.6 2.151 72.912 127.449 ;
     RECT  75.3 42.083 75.612 127.449 ;
     RECT  78 39.731 78.312 127.449 ;
     RECT  80.7 107.027 81.012 127.449 ;
     RECT  83.4 43.571 83.712 127.449 ;
     RECT  86.1 2.151 86.412 127.449 ;
     RECT  88.8 2.151 89.112 127.449 ;
     RECT  91.5 2.151 91.812 127.449 ;
     RECT  94.2 43.571 94.512 127.449 ;
     RECT  96.9 2.151 97.212 127.449 ;
     RECT  99.6 107.363 99.912 127.449 ;
     RECT  102.3 107.315 102.612 127.449 ;
     RECT  105 107.027 105.312 127.449 ;
     RECT  107.7 47.363 108.012 127.449 ;
     RECT  110.4 47.891 110.712 127.449 ;
     RECT  113.1 45.491 113.412 127.449 ;
     RECT  115.8 47.987 116.112 127.449 ;
     RECT  118.5 47.699 118.812 127.449 ;
     RECT  121.2 46.019 121.512 127.449 ;
     RECT  123.9 48.659 124.212 127.449 ;
     RECT  126.6 47.939 126.912 127.449 ;
     RECT  129.3 2.151 129.612 127.449 ;
     RECT  132 2.151 132.312 127.449 ;
     RECT  134.7 2.151 135.012 127.449 ;
     RECT  137.4 2.151 137.712 127.449 ;
     RECT  140.1 2.151 140.412 127.449 ;
     RECT  142.8 2.151 143.112 127.449 ;
     RECT  145.5 2.151 145.812 127.449 ;
     RECT  148.2 2.151 148.512 127.449 ;
     RECT  150.9 2.151 151.212 127.449 ;
     RECT  153.6 2.151 153.912 127.449 ;
     RECT  156.3 2.151 156.612 127.449 ;
     RECT  159 42.467 159.312 127.449 ;
     RECT  161.7 2.151 162.012 127.449 ;
     RECT  164.4 2.151 164.712 127.449 ;
     RECT  167.1 58.787 167.412 127.449 ;
     RECT  169.8 44.387 170.112 127.449 ;
     RECT  172.5 38.723 172.812 127.449 ;
     RECT  175.2 2.151 175.512 127.449 ;
     RECT  177.9 2.151 178.212 127.449 ;
     RECT  180.6 2.151 180.912 127.449 ;
     RECT  183.3 2.151 183.612 127.449 ;
     RECT  186 107.219 186.312 127.449 ;
     RECT  188.7 106.067 189.012 127.449 ;
     RECT  191.4 106.067 191.712 127.449 ;
     RECT  194.1 106.643 194.412 127.449 ;
     RECT  196.8 2.151 197.112 127.449 ;
     RECT  199.5 106.067 199.812 127.449 ;
     RECT  202.2 2.151 202.512 127.449 ;
     RECT  204.9 86.243 205.212 127.449 ;
     RECT  207.6 124.019 207.912 127.449 ;
     RECT  210.3 118.595 210.612 127.449 ;
     RECT  213 2.151 213.312 127.449 ;
     RECT  2.4 127.449 2.52 127.463 ;
     RECT  5.1 127.449 5.22 127.463 ;
     RECT  7.8 127.449 7.92 127.463 ;
     RECT  10.5 127.449 10.62 127.463 ;
     RECT  13.2 127.449 13.32 127.463 ;
     RECT  15.9 127.449 16.02 127.463 ;
     RECT  18.6 127.449 18.72 127.463 ;
     RECT  21.3 127.449 21.42 127.463 ;
     RECT  24 127.449 24.12 127.463 ;
     RECT  26.7 127.449 26.82 127.463 ;
     RECT  29.4 127.449 29.52 127.463 ;
     RECT  32.1 127.449 32.22 127.463 ;
     RECT  34.8 127.449 34.92 127.463 ;
     RECT  37.5 127.449 37.62 127.463 ;
     RECT  40.2 127.449 40.32 127.463 ;
     RECT  42.9 127.449 43.02 127.463 ;
     RECT  45.6 127.449 45.72 127.463 ;
     RECT  48.3 127.449 48.42 127.463 ;
     RECT  51 127.449 51.12 127.463 ;
     RECT  53.7 127.449 53.82 127.463 ;
     RECT  56.4 127.449 56.52 127.463 ;
     RECT  59.1 127.449 59.22 127.463 ;
     RECT  61.8 127.449 61.92 127.463 ;
     RECT  64.5 127.449 64.62 127.463 ;
     RECT  67.2 127.449 67.32 127.463 ;
     RECT  69.9 127.449 70.02 127.463 ;
     RECT  72.6 127.449 72.72 127.463 ;
     RECT  75.3 127.449 75.42 127.463 ;
     RECT  78 127.449 78.12 127.463 ;
     RECT  80.7 127.449 80.82 127.463 ;
     RECT  83.4 127.449 83.52 127.463 ;
     RECT  86.1 127.449 86.22 127.463 ;
     RECT  88.8 127.449 88.92 127.463 ;
     RECT  91.5 127.449 91.62 127.463 ;
     RECT  94.2 127.449 94.32 127.463 ;
     RECT  96.9 127.449 97.02 127.463 ;
     RECT  99.6 127.449 99.72 127.463 ;
     RECT  102.3 127.449 102.42 127.463 ;
     RECT  105 127.449 105.12 127.463 ;
     RECT  107.7 127.449 107.82 127.463 ;
     RECT  110.4 127.449 110.52 127.463 ;
     RECT  113.1 127.449 113.22 127.463 ;
     RECT  115.8 127.449 115.92 127.463 ;
     RECT  118.5 127.449 118.62 127.463 ;
     RECT  121.2 127.449 121.32 127.463 ;
     RECT  123.9 127.449 124.02 127.463 ;
     RECT  126.6 127.449 126.72 127.463 ;
     RECT  129.3 127.449 129.42 127.463 ;
     RECT  132 127.449 132.12 127.463 ;
     RECT  134.7 127.449 134.82 127.463 ;
     RECT  137.4 127.449 137.52 127.463 ;
     RECT  140.1 127.449 140.22 127.463 ;
     RECT  142.8 127.449 142.92 127.463 ;
     RECT  145.5 127.449 145.62 127.463 ;
     RECT  148.2 127.449 148.32 127.463 ;
     RECT  150.9 127.449 151.02 127.463 ;
     RECT  153.6 127.449 153.72 127.463 ;
     RECT  156.3 127.449 156.42 127.463 ;
     RECT  159 127.449 159.12 127.463 ;
     RECT  161.7 127.449 161.82 127.463 ;
     RECT  164.4 127.449 164.52 127.463 ;
     RECT  167.1 127.449 167.22 127.463 ;
     RECT  169.8 127.449 169.92 127.463 ;
     RECT  172.5 127.449 172.62 127.463 ;
     RECT  175.2 127.449 175.32 127.463 ;
     RECT  177.9 127.449 178.02 127.463 ;
     RECT  180.6 127.449 180.72 127.463 ;
     RECT  183.3 127.449 183.42 127.463 ;
     RECT  186 127.449 186.12 127.463 ;
     RECT  188.7 127.449 188.82 127.463 ;
     RECT  191.4 127.449 191.52 127.463 ;
     RECT  194.1 127.449 194.22 127.463 ;
     RECT  196.8 127.449 196.92 127.463 ;
     RECT  199.5 127.449 199.62 127.463 ;
     RECT  202.2 127.449 202.32 127.463 ;
     RECT  204.9 127.449 205.02 127.463 ;
     RECT  207.6 127.449 207.72 127.463 ;
     RECT  210.3 127.449 210.42 127.463 ;
     RECT  213 127.449 213.12 127.463 ;
  END
END qkd_d2d_cal_seq_pin_ovl_bc
END LIBRARY
